VERSION 5.8 ;
BUSBITCHARS "[]" ;
DIVIDERCHAR "/" ;
UNITS
    DATABASE MICRONS 1000 ;
END UNITS

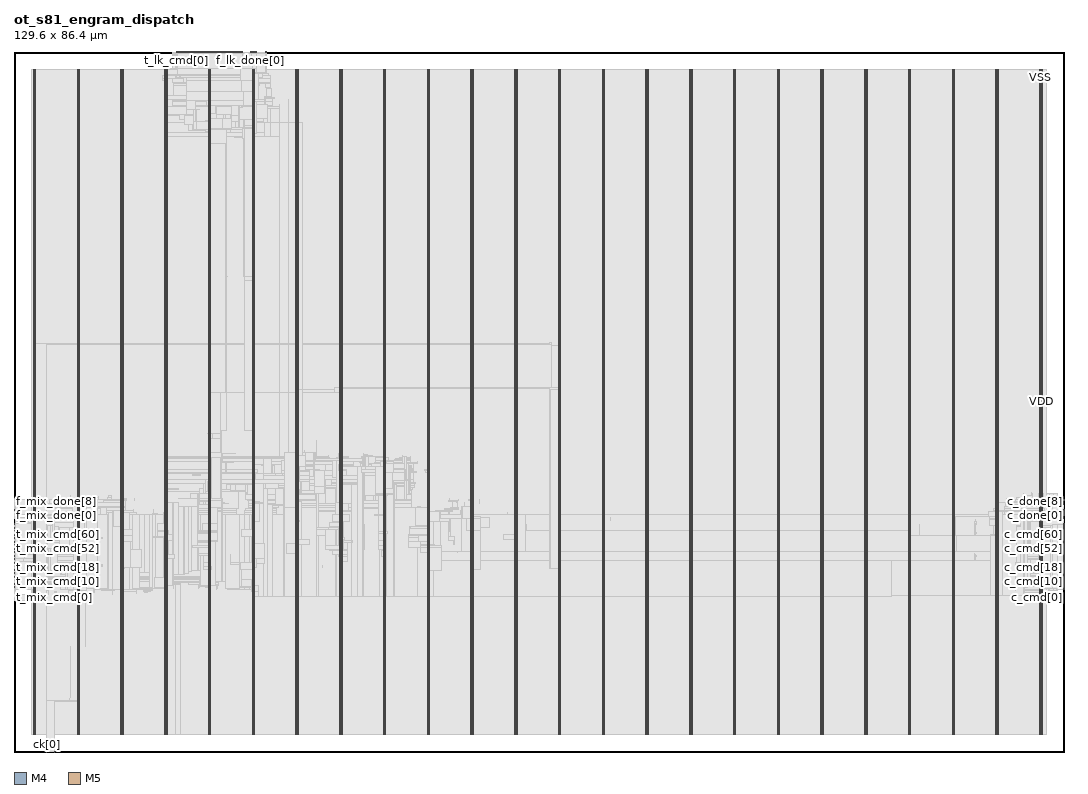
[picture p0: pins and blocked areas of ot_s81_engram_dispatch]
MACRO ot_s81_engram_dispatch
  FOREIGN ot_s81_engram_dispatch 0 0 ;
  CLASS BLOCK ;
  SIZE 129.6 BY 86.4 ;
  PIN c_cmd[0]
    DIRECTION INPUT ;
    USE SIGNAL ;
    PORT
      LAYER M4 ;
        RECT  129.516 20.064 129.6 20.088 ;
    END
  END c_cmd[0]
  PIN c_cmd[10]
    DIRECTION INPUT ;
    USE SIGNAL ;
    PORT
      LAYER M4 ;
        RECT  129.516 21.024 129.6 21.048 ;
    END
  END c_cmd[10]
  PIN c_cmd[11]
    DIRECTION INPUT ;
    USE SIGNAL ;
    PORT
      LAYER M4 ;
        RECT  129.516 21.12 129.6 21.144 ;
    END
  END c_cmd[11]
  PIN c_cmd[12]
    DIRECTION INPUT ;
    USE SIGNAL ;
    PORT
      LAYER M4 ;
        RECT  129.516 21.216 129.6 21.24 ;
    END
  END c_cmd[12]
  PIN c_cmd[13]
    DIRECTION INPUT ;
    USE SIGNAL ;
    PORT
      LAYER M4 ;
        RECT  129.516 21.312 129.6 21.336 ;
    END
  END c_cmd[13]
  PIN c_cmd[14]
    DIRECTION INPUT ;
    USE SIGNAL ;
    PORT
      LAYER M4 ;
        RECT  129.516 21.408 129.6 21.432 ;
    END
  END c_cmd[14]
  PIN c_cmd[15]
    DIRECTION INPUT ;
    USE SIGNAL ;
    PORT
      LAYER M4 ;
        RECT  129.516 21.504 129.6 21.528 ;
    END
  END c_cmd[15]
  PIN c_cmd[16]
    DIRECTION INPUT ;
    USE SIGNAL ;
    PORT
      LAYER M4 ;
        RECT  129.516 21.6 129.6 21.624 ;
    END
  END c_cmd[16]
  PIN c_cmd[17]
    DIRECTION INPUT ;
    USE SIGNAL ;
    PORT
      LAYER M4 ;
        RECT  129.516 21.696 129.6 21.72 ;
    END
  END c_cmd[17]
  PIN c_cmd[18]
    DIRECTION INPUT ;
    USE SIGNAL ;
    PORT
      LAYER M4 ;
        RECT  129.516 21.792 129.6 21.816 ;
    END
  END c_cmd[18]
  PIN c_cmd[19]
    DIRECTION INPUT ;
    USE SIGNAL ;
    PORT
      LAYER M4 ;
        RECT  129.516 21.888 129.6 21.912 ;
    END
  END c_cmd[19]
  PIN c_cmd[1]
    DIRECTION INPUT ;
    USE SIGNAL ;
    PORT
      LAYER M4 ;
        RECT  129.516 20.16 129.6 20.184 ;
    END
  END c_cmd[1]
  PIN c_cmd[20]
    DIRECTION INPUT ;
    USE SIGNAL ;
    PORT
      LAYER M4 ;
        RECT  129.516 21.984 129.6 22.008 ;
    END
  END c_cmd[20]
  PIN c_cmd[21]
    DIRECTION INPUT ;
    USE SIGNAL ;
    PORT
      LAYER M4 ;
        RECT  129.516 22.08 129.6 22.104 ;
    END
  END c_cmd[21]
  PIN c_cmd[22]
    DIRECTION INPUT ;
    USE SIGNAL ;
    PORT
      LAYER M4 ;
        RECT  129.516 22.176 129.6 22.2 ;
    END
  END c_cmd[22]
  PIN c_cmd[23]
    DIRECTION INPUT ;
    USE SIGNAL ;
    PORT
      LAYER M4 ;
        RECT  129.516 22.272 129.6 22.296 ;
    END
  END c_cmd[23]
  PIN c_cmd[24]
    DIRECTION INPUT ;
    USE SIGNAL ;
    PORT
      LAYER M4 ;
        RECT  129.516 22.368 129.6 22.392 ;
    END
  END c_cmd[24]
  PIN c_cmd[25]
    DIRECTION INPUT ;
    USE SIGNAL ;
    PORT
      LAYER M4 ;
        RECT  129.516 22.464 129.6 22.488 ;
    END
  END c_cmd[25]
  PIN c_cmd[26]
    DIRECTION INPUT ;
    USE SIGNAL ;
    PORT
      LAYER M4 ;
        RECT  129.516 22.56 129.6 22.584 ;
    END
  END c_cmd[26]
  PIN c_cmd[27]
    DIRECTION INPUT ;
    USE SIGNAL ;
    PORT
      LAYER M4 ;
        RECT  129.516 22.656 129.6 22.68 ;
    END
  END c_cmd[27]
  PIN c_cmd[28]
    DIRECTION INPUT ;
    USE SIGNAL ;
    PORT
      LAYER M4 ;
        RECT  129.516 22.752 129.6 22.776 ;
    END
  END c_cmd[28]
  PIN c_cmd[29]
    DIRECTION INPUT ;
    USE SIGNAL ;
    PORT
      LAYER M4 ;
        RECT  129.516 22.848 129.6 22.872 ;
    END
  END c_cmd[29]
  PIN c_cmd[2]
    DIRECTION INPUT ;
    USE SIGNAL ;
    PORT
      LAYER M4 ;
        RECT  129.516 20.256 129.6 20.28 ;
    END
  END c_cmd[2]
  PIN c_cmd[30]
    DIRECTION INPUT ;
    USE SIGNAL ;
    PORT
      LAYER M4 ;
        RECT  129.516 22.944 129.6 22.968 ;
    END
  END c_cmd[30]
  PIN c_cmd[31]
    DIRECTION INPUT ;
    USE SIGNAL ;
    PORT
      LAYER M4 ;
        RECT  129.516 23.04 129.6 23.064 ;
    END
  END c_cmd[31]
  PIN c_cmd[32]
    DIRECTION INPUT ;
    USE SIGNAL ;
    PORT
      LAYER M4 ;
        RECT  129.516 23.136 129.6 23.16 ;
    END
  END c_cmd[32]
  PIN c_cmd[33]
    DIRECTION INPUT ;
    USE SIGNAL ;
    PORT
      LAYER M4 ;
        RECT  129.516 23.232 129.6 23.256 ;
    END
  END c_cmd[33]
  PIN c_cmd[34]
    DIRECTION INPUT ;
    USE SIGNAL ;
    PORT
      LAYER M4 ;
        RECT  129.516 23.328 129.6 23.352 ;
    END
  END c_cmd[34]
  PIN c_cmd[35]
    DIRECTION INPUT ;
    USE SIGNAL ;
    PORT
      LAYER M4 ;
        RECT  129.516 23.424 129.6 23.448 ;
    END
  END c_cmd[35]
  PIN c_cmd[36]
    DIRECTION INPUT ;
    USE SIGNAL ;
    PORT
      LAYER M4 ;
        RECT  129.516 23.52 129.6 23.544 ;
    END
  END c_cmd[36]
  PIN c_cmd[37]
    DIRECTION INPUT ;
    USE SIGNAL ;
    PORT
      LAYER M4 ;
        RECT  129.516 23.616 129.6 23.64 ;
    END
  END c_cmd[37]
  PIN c_cmd[38]
    DIRECTION INPUT ;
    USE SIGNAL ;
    PORT
      LAYER M4 ;
        RECT  129.516 23.712 129.6 23.736 ;
    END
  END c_cmd[38]
  PIN c_cmd[39]
    DIRECTION INPUT ;
    USE SIGNAL ;
    PORT
      LAYER M4 ;
        RECT  129.516 23.808 129.6 23.832 ;
    END
  END c_cmd[39]
  PIN c_cmd[3]
    DIRECTION INPUT ;
    USE SIGNAL ;
    PORT
      LAYER M4 ;
        RECT  129.516 20.352 129.6 20.376 ;
    END
  END c_cmd[3]
  PIN c_cmd[40]
    DIRECTION INPUT ;
    USE SIGNAL ;
    PORT
      LAYER M4 ;
        RECT  129.516 23.904 129.6 23.928 ;
    END
  END c_cmd[40]
  PIN c_cmd[41]
    DIRECTION INPUT ;
    USE SIGNAL ;
    PORT
      LAYER M4 ;
        RECT  129.516 24 129.6 24.024 ;
    END
  END c_cmd[41]
  PIN c_cmd[42]
    DIRECTION INPUT ;
    USE SIGNAL ;
    PORT
      LAYER M4 ;
        RECT  129.516 24.096 129.6 24.12 ;
    END
  END c_cmd[42]
  PIN c_cmd[43]
    DIRECTION INPUT ;
    USE SIGNAL ;
    PORT
      LAYER M4 ;
        RECT  129.516 24.192 129.6 24.216 ;
    END
  END c_cmd[43]
  PIN c_cmd[44]
    DIRECTION INPUT ;
    USE SIGNAL ;
    PORT
      LAYER M4 ;
        RECT  129.516 24.288 129.6 24.312 ;
    END
  END c_cmd[44]
  PIN c_cmd[45]
    DIRECTION INPUT ;
    USE SIGNAL ;
    PORT
      LAYER M4 ;
        RECT  129.516 24.384 129.6 24.408 ;
    END
  END c_cmd[45]
  PIN c_cmd[46]
    DIRECTION INPUT ;
    USE SIGNAL ;
    PORT
      LAYER M4 ;
        RECT  129.516 24.48 129.6 24.504 ;
    END
  END c_cmd[46]
  PIN c_cmd[47]
    DIRECTION INPUT ;
    USE SIGNAL ;
    PORT
      LAYER M4 ;
        RECT  129.516 24.576 129.6 24.6 ;
    END
  END c_cmd[47]
  PIN c_cmd[48]
    DIRECTION INPUT ;
    USE SIGNAL ;
    PORT
      LAYER M4 ;
        RECT  129.516 24.672 129.6 24.696 ;
    END
  END c_cmd[48]
  PIN c_cmd[49]
    DIRECTION INPUT ;
    USE SIGNAL ;
    PORT
      LAYER M4 ;
        RECT  129.516 24.768 129.6 24.792 ;
    END
  END c_cmd[49]
  PIN c_cmd[4]
    DIRECTION INPUT ;
    USE SIGNAL ;
    PORT
      LAYER M4 ;
        RECT  129.516 20.448 129.6 20.472 ;
    END
  END c_cmd[4]
  PIN c_cmd[50]
    DIRECTION INPUT ;
    USE SIGNAL ;
    PORT
      LAYER M4 ;
        RECT  129.516 24.864 129.6 24.888 ;
    END
  END c_cmd[50]
  PIN c_cmd[51]
    DIRECTION INPUT ;
    USE SIGNAL ;
    PORT
      LAYER M4 ;
        RECT  129.516 24.96 129.6 24.984 ;
    END
  END c_cmd[51]
  PIN c_cmd[52]
    DIRECTION INPUT ;
    USE SIGNAL ;
    PORT
      LAYER M4 ;
        RECT  129.516 25.056 129.6 25.08 ;
    END
  END c_cmd[52]
  PIN c_cmd[53]
    DIRECTION INPUT ;
    USE SIGNAL ;
    PORT
      LAYER M4 ;
        RECT  129.516 25.152 129.6 25.176 ;
    END
  END c_cmd[53]
  PIN c_cmd[54]
    DIRECTION INPUT ;
    USE SIGNAL ;
    PORT
      LAYER M4 ;
        RECT  129.516 25.248 129.6 25.272 ;
    END
  END c_cmd[54]
  PIN c_cmd[55]
    DIRECTION INPUT ;
    USE SIGNAL ;
    PORT
      LAYER M4 ;
        RECT  129.516 25.344 129.6 25.368 ;
    END
  END c_cmd[55]
  PIN c_cmd[56]
    DIRECTION INPUT ;
    USE SIGNAL ;
    PORT
      LAYER M4 ;
        RECT  129.516 25.44 129.6 25.464 ;
    END
  END c_cmd[56]
  PIN c_cmd[57]
    DIRECTION INPUT ;
    USE SIGNAL ;
    PORT
      LAYER M4 ;
        RECT  129.516 25.536 129.6 25.56 ;
    END
  END c_cmd[57]
  PIN c_cmd[58]
    DIRECTION INPUT ;
    USE SIGNAL ;
    PORT
      LAYER M4 ;
        RECT  129.516 25.632 129.6 25.656 ;
    END
  END c_cmd[58]
  PIN c_cmd[59]
    DIRECTION INPUT ;
    USE SIGNAL ;
    PORT
      LAYER M4 ;
        RECT  129.516 25.728 129.6 25.752 ;
    END
  END c_cmd[59]
  PIN c_cmd[5]
    DIRECTION INPUT ;
    USE SIGNAL ;
    PORT
      LAYER M4 ;
        RECT  129.516 20.544 129.6 20.568 ;
    END
  END c_cmd[5]
  PIN c_cmd[60]
    DIRECTION INPUT ;
    USE SIGNAL ;
    PORT
      LAYER M4 ;
        RECT  129.516 25.824 129.6 25.848 ;
    END
  END c_cmd[60]
  PIN c_cmd[61]
    DIRECTION INPUT ;
    USE SIGNAL ;
    PORT
      LAYER M4 ;
        RECT  129.516 25.92 129.6 25.944 ;
    END
  END c_cmd[61]
  PIN c_cmd[62]
    DIRECTION INPUT ;
    USE SIGNAL ;
    PORT
      LAYER M4 ;
        RECT  129.516 26.016 129.6 26.04 ;
    END
  END c_cmd[62]
  PIN c_cmd[63]
    DIRECTION INPUT ;
    USE SIGNAL ;
    PORT
      LAYER M4 ;
        RECT  129.516 26.112 129.6 26.136 ;
    END
  END c_cmd[63]
  PIN c_cmd[64]
    DIRECTION INPUT ;
    USE SIGNAL ;
    PORT
      LAYER M4 ;
        RECT  129.516 26.208 129.6 26.232 ;
    END
  END c_cmd[64]
  PIN c_cmd[65]
    DIRECTION INPUT ;
    USE SIGNAL ;
    PORT
      LAYER M4 ;
        RECT  129.516 26.304 129.6 26.328 ;
    END
  END c_cmd[65]
  PIN c_cmd[66]
    DIRECTION INPUT ;
    USE SIGNAL ;
    PORT
      LAYER M4 ;
        RECT  129.516 26.4 129.6 26.424 ;
    END
  END c_cmd[66]
  PIN c_cmd[67]
    DIRECTION INPUT ;
    USE SIGNAL ;
    PORT
      LAYER M4 ;
        RECT  129.516 26.496 129.6 26.52 ;
    END
  END c_cmd[67]
  PIN c_cmd[68]
    DIRECTION INPUT ;
    USE SIGNAL ;
    PORT
      LAYER M4 ;
        RECT  129.516 26.592 129.6 26.616 ;
    END
  END c_cmd[68]
  PIN c_cmd[69]
    DIRECTION INPUT ;
    USE SIGNAL ;
    PORT
      LAYER M4 ;
        RECT  129.516 26.688 129.6 26.712 ;
    END
  END c_cmd[69]
  PIN c_cmd[6]
    DIRECTION INPUT ;
    USE SIGNAL ;
    PORT
      LAYER M4 ;
        RECT  129.516 20.64 129.6 20.664 ;
    END
  END c_cmd[6]
  PIN c_cmd[70]
    DIRECTION INPUT ;
    USE SIGNAL ;
    PORT
      LAYER M4 ;
        RECT  129.516 26.784 129.6 26.808 ;
    END
  END c_cmd[70]
  PIN c_cmd[71]
    DIRECTION INPUT ;
    USE SIGNAL ;
    PORT
      LAYER M4 ;
        RECT  129.516 26.88 129.6 26.904 ;
    END
  END c_cmd[71]
  PIN c_cmd[72]
    DIRECTION INPUT ;
    USE SIGNAL ;
    PORT
      LAYER M4 ;
        RECT  129.516 26.976 129.6 27 ;
    END
  END c_cmd[72]
  PIN c_cmd[73]
    DIRECTION INPUT ;
    USE SIGNAL ;
    PORT
      LAYER M4 ;
        RECT  129.516 27.072 129.6 27.096 ;
    END
  END c_cmd[73]
  PIN c_cmd[74]
    DIRECTION INPUT ;
    USE SIGNAL ;
    PORT
      LAYER M4 ;
        RECT  129.516 27.168 129.6 27.192 ;
    END
  END c_cmd[74]
  PIN c_cmd[75]
    DIRECTION INPUT ;
    USE SIGNAL ;
    PORT
      LAYER M4 ;
        RECT  129.516 27.264 129.6 27.288 ;
    END
  END c_cmd[75]
  PIN c_cmd[76]
    DIRECTION INPUT ;
    USE SIGNAL ;
    PORT
      LAYER M4 ;
        RECT  129.516 27.36 129.6 27.384 ;
    END
  END c_cmd[76]
  PIN c_cmd[77]
    DIRECTION INPUT ;
    USE SIGNAL ;
    PORT
      LAYER M4 ;
        RECT  129.516 27.456 129.6 27.48 ;
    END
  END c_cmd[77]
  PIN c_cmd[78]
    DIRECTION INPUT ;
    USE SIGNAL ;
    PORT
      LAYER M4 ;
        RECT  129.516 27.552 129.6 27.576 ;
    END
  END c_cmd[78]
  PIN c_cmd[79]
    DIRECTION INPUT ;
    USE SIGNAL ;
    PORT
      LAYER M4 ;
        RECT  129.516 27.648 129.6 27.672 ;
    END
  END c_cmd[79]
  PIN c_cmd[7]
    DIRECTION INPUT ;
    USE SIGNAL ;
    PORT
      LAYER M4 ;
        RECT  129.516 20.736 129.6 20.76 ;
    END
  END c_cmd[7]
  PIN c_cmd[80]
    DIRECTION INPUT ;
    USE SIGNAL ;
    PORT
      LAYER M4 ;
        RECT  129.516 27.744 129.6 27.768 ;
    END
  END c_cmd[80]
  PIN c_cmd[81]
    DIRECTION INPUT ;
    USE SIGNAL ;
    PORT
      LAYER M4 ;
        RECT  129.516 27.84 129.6 27.864 ;
    END
  END c_cmd[81]
  PIN c_cmd[82]
    DIRECTION INPUT ;
    USE SIGNAL ;
    PORT
      LAYER M4 ;
        RECT  129.516 27.936 129.6 27.96 ;
    END
  END c_cmd[82]
  PIN c_cmd[83]
    DIRECTION INPUT ;
    USE SIGNAL ;
    PORT
      LAYER M4 ;
        RECT  129.516 28.032 129.6 28.056 ;
    END
  END c_cmd[83]
  PIN c_cmd[84]
    DIRECTION INPUT ;
    USE SIGNAL ;
    PORT
      LAYER M4 ;
        RECT  129.516 28.128 129.6 28.152 ;
    END
  END c_cmd[84]
  PIN c_cmd[8]
    DIRECTION INPUT ;
    USE SIGNAL ;
    PORT
      LAYER M4 ;
        RECT  129.516 20.832 129.6 20.856 ;
    END
  END c_cmd[8]
  PIN c_cmd[9]
    DIRECTION INPUT ;
    USE SIGNAL ;
    PORT
      LAYER M4 ;
        RECT  129.516 20.928 129.6 20.952 ;
    END
  END c_cmd[9]
  PIN c_done[0]
    DIRECTION OUTPUT ;
    USE SIGNAL ;
    PORT
      LAYER M4 ;
        RECT  129.516 29.184 129.6 29.208 ;
    END
  END c_done[0]
  PIN c_done[1]
    DIRECTION OUTPUT ;
    USE SIGNAL ;
    PORT
      LAYER M4 ;
        RECT  129.516 29.28 129.6 29.304 ;
    END
  END c_done[1]
  PIN c_done[2]
    DIRECTION OUTPUT ;
    USE SIGNAL ;
    PORT
      LAYER M4 ;
        RECT  129.516 29.376 129.6 29.4 ;
    END
  END c_done[2]
  PIN c_done[3]
    DIRECTION OUTPUT ;
    USE SIGNAL ;
    PORT
      LAYER M4 ;
        RECT  129.516 29.472 129.6 29.496 ;
    END
  END c_done[3]
  PIN c_done[4]
    DIRECTION OUTPUT ;
    USE SIGNAL ;
    PORT
      LAYER M4 ;
        RECT  129.516 29.568 129.6 29.592 ;
    END
  END c_done[4]
  PIN c_done[5]
    DIRECTION OUTPUT ;
    USE SIGNAL ;
    PORT
      LAYER M4 ;
        RECT  129.516 29.664 129.6 29.688 ;
    END
  END c_done[5]
  PIN c_done[6]
    DIRECTION OUTPUT ;
    USE SIGNAL ;
    PORT
      LAYER M4 ;
        RECT  129.516 29.76 129.6 29.784 ;
    END
  END c_done[6]
  PIN c_done[7]
    DIRECTION OUTPUT ;
    USE SIGNAL ;
    PORT
      LAYER M4 ;
        RECT  129.516 29.856 129.6 29.88 ;
    END
  END c_done[7]
  PIN c_done[8]
    DIRECTION OUTPUT ;
    USE SIGNAL ;
    PORT
      LAYER M4 ;
        RECT  129.516 29.952 129.6 29.976 ;
    END
  END c_done[8]
  PIN c_st[0]
    DIRECTION OUTPUT ;
    USE SIGNAL ;
    PORT
      LAYER M4 ;
        RECT  129.516 31.008 129.6 31.032 ;
    END
  END c_st[0]
  PIN c_st[1]
    DIRECTION OUTPUT ;
    USE SIGNAL ;
    PORT
      LAYER M4 ;
        RECT  129.516 31.104 129.6 31.128 ;
    END
  END c_st[1]
  PIN ck[0]
    DIRECTION INPUT ;
    USE SIGNAL ;
    PORT
      LAYER M5 ;
        RECT  4.032 0 4.056 0.084 ;
    END
  END ck[0]
  PIN f_lk_done[0]
    DIRECTION INPUT ;
    USE SIGNAL ;
    PORT
      LAYER M5 ;
        RECT  29.184 86.316 29.208 86.4 ;
    END
  END f_lk_done[0]
  PIN f_lk_done[1]
    DIRECTION INPUT ;
    USE SIGNAL ;
    PORT
      LAYER M5 ;
        RECT  29.28 86.316 29.304 86.4 ;
    END
  END f_lk_done[1]
  PIN f_lk_done[2]
    DIRECTION INPUT ;
    USE SIGNAL ;
    PORT
      LAYER M5 ;
        RECT  29.376 86.316 29.4 86.4 ;
    END
  END f_lk_done[2]
  PIN f_lk_done[3]
    DIRECTION INPUT ;
    USE SIGNAL ;
    PORT
      LAYER M5 ;
        RECT  29.472 86.316 29.496 86.4 ;
    END
  END f_lk_done[3]
  PIN f_lk_done[4]
    DIRECTION INPUT ;
    USE SIGNAL ;
    PORT
      LAYER M5 ;
        RECT  29.568 86.316 29.592 86.4 ;
    END
  END f_lk_done[4]
  PIN f_lk_done[5]
    DIRECTION INPUT ;
    USE SIGNAL ;
    PORT
      LAYER M5 ;
        RECT  29.664 86.316 29.688 86.4 ;
    END
  END f_lk_done[5]
  PIN f_lk_done[6]
    DIRECTION INPUT ;
    USE SIGNAL ;
    PORT
      LAYER M5 ;
        RECT  29.76 86.316 29.784 86.4 ;
    END
  END f_lk_done[6]
  PIN f_lk_done[7]
    DIRECTION INPUT ;
    USE SIGNAL ;
    PORT
      LAYER M5 ;
        RECT  29.856 86.316 29.88 86.4 ;
    END
  END f_lk_done[7]
  PIN f_lk_done[8]
    DIRECTION INPUT ;
    USE SIGNAL ;
    PORT
      LAYER M5 ;
        RECT  29.952 86.316 29.976 86.4 ;
    END
  END f_lk_done[8]
  PIN f_lk_st[0]
    DIRECTION INPUT ;
    USE SIGNAL ;
    PORT
      LAYER M5 ;
        RECT  31.008 86.316 31.032 86.4 ;
    END
  END f_lk_st[0]
  PIN f_lk_st[1]
    DIRECTION INPUT ;
    USE SIGNAL ;
    PORT
      LAYER M5 ;
        RECT  31.104 86.316 31.128 86.4 ;
    END
  END f_lk_st[1]
  PIN f_mix_done[0]
    DIRECTION INPUT ;
    USE SIGNAL ;
    PORT
      LAYER M4 ;
        RECT  0 29.184 0.084 29.208 ;
    END
  END f_mix_done[0]
  PIN f_mix_done[1]
    DIRECTION INPUT ;
    USE SIGNAL ;
    PORT
      LAYER M4 ;
        RECT  0 29.28 0.084 29.304 ;
    END
  END f_mix_done[1]
  PIN f_mix_done[2]
    DIRECTION INPUT ;
    USE SIGNAL ;
    PORT
      LAYER M4 ;
        RECT  0 29.376 0.084 29.4 ;
    END
  END f_mix_done[2]
  PIN f_mix_done[3]
    DIRECTION INPUT ;
    USE SIGNAL ;
    PORT
      LAYER M4 ;
        RECT  0 29.472 0.084 29.496 ;
    END
  END f_mix_done[3]
  PIN f_mix_done[4]
    DIRECTION INPUT ;
    USE SIGNAL ;
    PORT
      LAYER M4 ;
        RECT  0 29.568 0.084 29.592 ;
    END
  END f_mix_done[4]
  PIN f_mix_done[5]
    DIRECTION INPUT ;
    USE SIGNAL ;
    PORT
      LAYER M4 ;
        RECT  0 29.664 0.084 29.688 ;
    END
  END f_mix_done[5]
  PIN f_mix_done[6]
    DIRECTION INPUT ;
    USE SIGNAL ;
    PORT
      LAYER M4 ;
        RECT  0 29.76 0.084 29.784 ;
    END
  END f_mix_done[6]
  PIN f_mix_done[7]
    DIRECTION INPUT ;
    USE SIGNAL ;
    PORT
      LAYER M4 ;
        RECT  0 29.856 0.084 29.88 ;
    END
  END f_mix_done[7]
  PIN f_mix_done[8]
    DIRECTION INPUT ;
    USE SIGNAL ;
    PORT
      LAYER M4 ;
        RECT  0 29.952 0.084 29.976 ;
    END
  END f_mix_done[8]
  PIN f_mix_st[0]
    DIRECTION INPUT ;
    USE SIGNAL ;
    PORT
      LAYER M4 ;
        RECT  0 31.008 0.084 31.032 ;
    END
  END f_mix_st[0]
  PIN f_mix_st[1]
    DIRECTION INPUT ;
    USE SIGNAL ;
    PORT
      LAYER M4 ;
        RECT  0 31.104 0.084 31.128 ;
    END
  END f_mix_st[1]
  PIN rst[0]
    DIRECTION INPUT ;
    USE SIGNAL ;
    PORT
      LAYER M5 ;
        RECT  4.992 0 5.016 0.084 ;
    END
  END rst[0]
  PIN t_lk_cmd[0]
    DIRECTION OUTPUT ;
    USE SIGNAL ;
    PORT
      LAYER M5 ;
        RECT  20.064 86.316 20.088 86.4 ;
    END
  END t_lk_cmd[0]
  PIN t_lk_cmd[10]
    DIRECTION OUTPUT ;
    USE SIGNAL ;
    PORT
      LAYER M5 ;
        RECT  21.024 86.316 21.048 86.4 ;
    END
  END t_lk_cmd[10]
  PIN t_lk_cmd[11]
    DIRECTION OUTPUT ;
    USE SIGNAL ;
    PORT
      LAYER M5 ;
        RECT  21.12 86.316 21.144 86.4 ;
    END
  END t_lk_cmd[11]
  PIN t_lk_cmd[12]
    DIRECTION OUTPUT ;
    USE SIGNAL ;
    PORT
      LAYER M5 ;
        RECT  21.216 86.316 21.24 86.4 ;
    END
  END t_lk_cmd[12]
  PIN t_lk_cmd[13]
    DIRECTION OUTPUT ;
    USE SIGNAL ;
    PORT
      LAYER M5 ;
        RECT  21.312 86.316 21.336 86.4 ;
    END
  END t_lk_cmd[13]
  PIN t_lk_cmd[14]
    DIRECTION OUTPUT ;
    USE SIGNAL ;
    PORT
      LAYER M5 ;
        RECT  21.408 86.316 21.432 86.4 ;
    END
  END t_lk_cmd[14]
  PIN t_lk_cmd[15]
    DIRECTION OUTPUT ;
    USE SIGNAL ;
    PORT
      LAYER M5 ;
        RECT  21.504 86.316 21.528 86.4 ;
    END
  END t_lk_cmd[15]
  PIN t_lk_cmd[16]
    DIRECTION OUTPUT ;
    USE SIGNAL ;
    PORT
      LAYER M5 ;
        RECT  21.6 86.316 21.624 86.4 ;
    END
  END t_lk_cmd[16]
  PIN t_lk_cmd[17]
    DIRECTION OUTPUT ;
    USE SIGNAL ;
    PORT
      LAYER M5 ;
        RECT  21.696 86.316 21.72 86.4 ;
    END
  END t_lk_cmd[17]
  PIN t_lk_cmd[18]
    DIRECTION OUTPUT ;
    USE SIGNAL ;
    PORT
      LAYER M5 ;
        RECT  21.792 86.316 21.816 86.4 ;
    END
  END t_lk_cmd[18]
  PIN t_lk_cmd[19]
    DIRECTION OUTPUT ;
    USE SIGNAL ;
    PORT
      LAYER M5 ;
        RECT  21.888 86.316 21.912 86.4 ;
    END
  END t_lk_cmd[19]
  PIN t_lk_cmd[1]
    DIRECTION OUTPUT ;
    USE SIGNAL ;
    PORT
      LAYER M5 ;
        RECT  20.16 86.316 20.184 86.4 ;
    END
  END t_lk_cmd[1]
  PIN t_lk_cmd[20]
    DIRECTION OUTPUT ;
    USE SIGNAL ;
    PORT
      LAYER M5 ;
        RECT  21.984 86.316 22.008 86.4 ;
    END
  END t_lk_cmd[20]
  PIN t_lk_cmd[21]
    DIRECTION OUTPUT ;
    USE SIGNAL ;
    PORT
      LAYER M5 ;
        RECT  22.08 86.316 22.104 86.4 ;
    END
  END t_lk_cmd[21]
  PIN t_lk_cmd[22]
    DIRECTION OUTPUT ;
    USE SIGNAL ;
    PORT
      LAYER M5 ;
        RECT  22.176 86.316 22.2 86.4 ;
    END
  END t_lk_cmd[22]
  PIN t_lk_cmd[23]
    DIRECTION OUTPUT ;
    USE SIGNAL ;
    PORT
      LAYER M5 ;
        RECT  22.272 86.316 22.296 86.4 ;
    END
  END t_lk_cmd[23]
  PIN t_lk_cmd[24]
    DIRECTION OUTPUT ;
    USE SIGNAL ;
    PORT
      LAYER M5 ;
        RECT  22.368 86.316 22.392 86.4 ;
    END
  END t_lk_cmd[24]
  PIN t_lk_cmd[25]
    DIRECTION OUTPUT ;
    USE SIGNAL ;
    PORT
      LAYER M5 ;
        RECT  22.464 86.316 22.488 86.4 ;
    END
  END t_lk_cmd[25]
  PIN t_lk_cmd[26]
    DIRECTION OUTPUT ;
    USE SIGNAL ;
    PORT
      LAYER M5 ;
        RECT  22.56 86.316 22.584 86.4 ;
    END
  END t_lk_cmd[26]
  PIN t_lk_cmd[27]
    DIRECTION OUTPUT ;
    USE SIGNAL ;
    PORT
      LAYER M5 ;
        RECT  22.656 86.316 22.68 86.4 ;
    END
  END t_lk_cmd[27]
  PIN t_lk_cmd[28]
    DIRECTION OUTPUT ;
    USE SIGNAL ;
    PORT
      LAYER M5 ;
        RECT  22.752 86.316 22.776 86.4 ;
    END
  END t_lk_cmd[28]
  PIN t_lk_cmd[29]
    DIRECTION OUTPUT ;
    USE SIGNAL ;
    PORT
      LAYER M5 ;
        RECT  22.848 86.316 22.872 86.4 ;
    END
  END t_lk_cmd[29]
  PIN t_lk_cmd[2]
    DIRECTION OUTPUT ;
    USE SIGNAL ;
    PORT
      LAYER M5 ;
        RECT  20.256 86.316 20.28 86.4 ;
    END
  END t_lk_cmd[2]
  PIN t_lk_cmd[30]
    DIRECTION OUTPUT ;
    USE SIGNAL ;
    PORT
      LAYER M5 ;
        RECT  22.944 86.316 22.968 86.4 ;
    END
  END t_lk_cmd[30]
  PIN t_lk_cmd[31]
    DIRECTION OUTPUT ;
    USE SIGNAL ;
    PORT
      LAYER M5 ;
        RECT  23.04 86.316 23.064 86.4 ;
    END
  END t_lk_cmd[31]
  PIN t_lk_cmd[32]
    DIRECTION OUTPUT ;
    USE SIGNAL ;
    PORT
      LAYER M5 ;
        RECT  23.136 86.316 23.16 86.4 ;
    END
  END t_lk_cmd[32]
  PIN t_lk_cmd[33]
    DIRECTION OUTPUT ;
    USE SIGNAL ;
    PORT
      LAYER M5 ;
        RECT  23.232 86.316 23.256 86.4 ;
    END
  END t_lk_cmd[33]
  PIN t_lk_cmd[34]
    DIRECTION OUTPUT ;
    USE SIGNAL ;
    PORT
      LAYER M5 ;
        RECT  23.328 86.316 23.352 86.4 ;
    END
  END t_lk_cmd[34]
  PIN t_lk_cmd[35]
    DIRECTION OUTPUT ;
    USE SIGNAL ;
    PORT
      LAYER M5 ;
        RECT  23.424 86.316 23.448 86.4 ;
    END
  END t_lk_cmd[35]
  PIN t_lk_cmd[36]
    DIRECTION OUTPUT ;
    USE SIGNAL ;
    PORT
      LAYER M5 ;
        RECT  23.52 86.316 23.544 86.4 ;
    END
  END t_lk_cmd[36]
  PIN t_lk_cmd[37]
    DIRECTION OUTPUT ;
    USE SIGNAL ;
    PORT
      LAYER M5 ;
        RECT  23.616 86.316 23.64 86.4 ;
    END
  END t_lk_cmd[37]
  PIN t_lk_cmd[38]
    DIRECTION OUTPUT ;
    USE SIGNAL ;
    PORT
      LAYER M5 ;
        RECT  23.712 86.316 23.736 86.4 ;
    END
  END t_lk_cmd[38]
  PIN t_lk_cmd[39]
    DIRECTION OUTPUT ;
    USE SIGNAL ;
    PORT
      LAYER M5 ;
        RECT  23.808 86.316 23.832 86.4 ;
    END
  END t_lk_cmd[39]
  PIN t_lk_cmd[3]
    DIRECTION OUTPUT ;
    USE SIGNAL ;
    PORT
      LAYER M5 ;
        RECT  20.352 86.316 20.376 86.4 ;
    END
  END t_lk_cmd[3]
  PIN t_lk_cmd[40]
    DIRECTION OUTPUT ;
    USE SIGNAL ;
    PORT
      LAYER M5 ;
        RECT  23.904 86.316 23.928 86.4 ;
    END
  END t_lk_cmd[40]
  PIN t_lk_cmd[41]
    DIRECTION OUTPUT ;
    USE SIGNAL ;
    PORT
      LAYER M5 ;
        RECT  24 86.316 24.024 86.4 ;
    END
  END t_lk_cmd[41]
  PIN t_lk_cmd[42]
    DIRECTION OUTPUT ;
    USE SIGNAL ;
    PORT
      LAYER M5 ;
        RECT  24.096 86.316 24.12 86.4 ;
    END
  END t_lk_cmd[42]
  PIN t_lk_cmd[43]
    DIRECTION OUTPUT ;
    USE SIGNAL ;
    PORT
      LAYER M5 ;
        RECT  24.192 86.316 24.216 86.4 ;
    END
  END t_lk_cmd[43]
  PIN t_lk_cmd[44]
    DIRECTION OUTPUT ;
    USE SIGNAL ;
    PORT
      LAYER M5 ;
        RECT  24.288 86.316 24.312 86.4 ;
    END
  END t_lk_cmd[44]
  PIN t_lk_cmd[45]
    DIRECTION OUTPUT ;
    USE SIGNAL ;
    PORT
      LAYER M5 ;
        RECT  24.384 86.316 24.408 86.4 ;
    END
  END t_lk_cmd[45]
  PIN t_lk_cmd[46]
    DIRECTION OUTPUT ;
    USE SIGNAL ;
    PORT
      LAYER M5 ;
        RECT  24.48 86.316 24.504 86.4 ;
    END
  END t_lk_cmd[46]
  PIN t_lk_cmd[47]
    DIRECTION OUTPUT ;
    USE SIGNAL ;
    PORT
      LAYER M5 ;
        RECT  24.576 86.316 24.6 86.4 ;
    END
  END t_lk_cmd[47]
  PIN t_lk_cmd[48]
    DIRECTION OUTPUT ;
    USE SIGNAL ;
    PORT
      LAYER M5 ;
        RECT  24.672 86.316 24.696 86.4 ;
    END
  END t_lk_cmd[48]
  PIN t_lk_cmd[49]
    DIRECTION OUTPUT ;
    USE SIGNAL ;
    PORT
      LAYER M5 ;
        RECT  24.768 86.316 24.792 86.4 ;
    END
  END t_lk_cmd[49]
  PIN t_lk_cmd[4]
    DIRECTION OUTPUT ;
    USE SIGNAL ;
    PORT
      LAYER M5 ;
        RECT  20.448 86.316 20.472 86.4 ;
    END
  END t_lk_cmd[4]
  PIN t_lk_cmd[50]
    DIRECTION OUTPUT ;
    USE SIGNAL ;
    PORT
      LAYER M5 ;
        RECT  24.864 86.316 24.888 86.4 ;
    END
  END t_lk_cmd[50]
  PIN t_lk_cmd[51]
    DIRECTION OUTPUT ;
    USE SIGNAL ;
    PORT
      LAYER M5 ;
        RECT  24.96 86.316 24.984 86.4 ;
    END
  END t_lk_cmd[51]
  PIN t_lk_cmd[52]
    DIRECTION OUTPUT ;
    USE SIGNAL ;
    PORT
      LAYER M5 ;
        RECT  25.056 86.316 25.08 86.4 ;
    END
  END t_lk_cmd[52]
  PIN t_lk_cmd[53]
    DIRECTION OUTPUT ;
    USE SIGNAL ;
    PORT
      LAYER M5 ;
        RECT  25.152 86.316 25.176 86.4 ;
    END
  END t_lk_cmd[53]
  PIN t_lk_cmd[54]
    DIRECTION OUTPUT ;
    USE SIGNAL ;
    PORT
      LAYER M5 ;
        RECT  25.248 86.316 25.272 86.4 ;
    END
  END t_lk_cmd[54]
  PIN t_lk_cmd[55]
    DIRECTION OUTPUT ;
    USE SIGNAL ;
    PORT
      LAYER M5 ;
        RECT  25.344 86.316 25.368 86.4 ;
    END
  END t_lk_cmd[55]
  PIN t_lk_cmd[56]
    DIRECTION OUTPUT ;
    USE SIGNAL ;
    PORT
      LAYER M5 ;
        RECT  25.44 86.316 25.464 86.4 ;
    END
  END t_lk_cmd[56]
  PIN t_lk_cmd[57]
    DIRECTION OUTPUT ;
    USE SIGNAL ;
    PORT
      LAYER M5 ;
        RECT  25.536 86.316 25.56 86.4 ;
    END
  END t_lk_cmd[57]
  PIN t_lk_cmd[58]
    DIRECTION OUTPUT ;
    USE SIGNAL ;
    PORT
      LAYER M5 ;
        RECT  25.632 86.316 25.656 86.4 ;
    END
  END t_lk_cmd[58]
  PIN t_lk_cmd[59]
    DIRECTION OUTPUT ;
    USE SIGNAL ;
    PORT
      LAYER M5 ;
        RECT  25.728 86.316 25.752 86.4 ;
    END
  END t_lk_cmd[59]
  PIN t_lk_cmd[5]
    DIRECTION OUTPUT ;
    USE SIGNAL ;
    PORT
      LAYER M5 ;
        RECT  20.544 86.316 20.568 86.4 ;
    END
  END t_lk_cmd[5]
  PIN t_lk_cmd[60]
    DIRECTION OUTPUT ;
    USE SIGNAL ;
    PORT
      LAYER M5 ;
        RECT  25.824 86.316 25.848 86.4 ;
    END
  END t_lk_cmd[60]
  PIN t_lk_cmd[61]
    DIRECTION OUTPUT ;
    USE SIGNAL ;
    PORT
      LAYER M5 ;
        RECT  25.92 86.316 25.944 86.4 ;
    END
  END t_lk_cmd[61]
  PIN t_lk_cmd[62]
    DIRECTION OUTPUT ;
    USE SIGNAL ;
    PORT
      LAYER M5 ;
        RECT  26.016 86.316 26.04 86.4 ;
    END
  END t_lk_cmd[62]
  PIN t_lk_cmd[63]
    DIRECTION OUTPUT ;
    USE SIGNAL ;
    PORT
      LAYER M5 ;
        RECT  26.112 86.316 26.136 86.4 ;
    END
  END t_lk_cmd[63]
  PIN t_lk_cmd[64]
    DIRECTION OUTPUT ;
    USE SIGNAL ;
    PORT
      LAYER M5 ;
        RECT  26.208 86.316 26.232 86.4 ;
    END
  END t_lk_cmd[64]
  PIN t_lk_cmd[65]
    DIRECTION OUTPUT ;
    USE SIGNAL ;
    PORT
      LAYER M5 ;
        RECT  26.304 86.316 26.328 86.4 ;
    END
  END t_lk_cmd[65]
  PIN t_lk_cmd[66]
    DIRECTION OUTPUT ;
    USE SIGNAL ;
    PORT
      LAYER M5 ;
        RECT  26.4 86.316 26.424 86.4 ;
    END
  END t_lk_cmd[66]
  PIN t_lk_cmd[67]
    DIRECTION OUTPUT ;
    USE SIGNAL ;
    PORT
      LAYER M5 ;
        RECT  26.496 86.316 26.52 86.4 ;
    END
  END t_lk_cmd[67]
  PIN t_lk_cmd[68]
    DIRECTION OUTPUT ;
    USE SIGNAL ;
    PORT
      LAYER M5 ;
        RECT  26.592 86.316 26.616 86.4 ;
    END
  END t_lk_cmd[68]
  PIN t_lk_cmd[69]
    DIRECTION OUTPUT ;
    USE SIGNAL ;
    PORT
      LAYER M5 ;
        RECT  26.688 86.316 26.712 86.4 ;
    END
  END t_lk_cmd[69]
  PIN t_lk_cmd[6]
    DIRECTION OUTPUT ;
    USE SIGNAL ;
    PORT
      LAYER M5 ;
        RECT  20.64 86.316 20.664 86.4 ;
    END
  END t_lk_cmd[6]
  PIN t_lk_cmd[70]
    DIRECTION OUTPUT ;
    USE SIGNAL ;
    PORT
      LAYER M5 ;
        RECT  26.784 86.316 26.808 86.4 ;
    END
  END t_lk_cmd[70]
  PIN t_lk_cmd[71]
    DIRECTION OUTPUT ;
    USE SIGNAL ;
    PORT
      LAYER M5 ;
        RECT  26.88 86.316 26.904 86.4 ;
    END
  END t_lk_cmd[71]
  PIN t_lk_cmd[72]
    DIRECTION OUTPUT ;
    USE SIGNAL ;
    PORT
      LAYER M5 ;
        RECT  26.976 86.316 27 86.4 ;
    END
  END t_lk_cmd[72]
  PIN t_lk_cmd[73]
    DIRECTION OUTPUT ;
    USE SIGNAL ;
    PORT
      LAYER M5 ;
        RECT  27.072 86.316 27.096 86.4 ;
    END
  END t_lk_cmd[73]
  PIN t_lk_cmd[74]
    DIRECTION OUTPUT ;
    USE SIGNAL ;
    PORT
      LAYER M5 ;
        RECT  27.168 86.316 27.192 86.4 ;
    END
  END t_lk_cmd[74]
  PIN t_lk_cmd[75]
    DIRECTION OUTPUT ;
    USE SIGNAL ;
    PORT
      LAYER M5 ;
        RECT  27.264 86.316 27.288 86.4 ;
    END
  END t_lk_cmd[75]
  PIN t_lk_cmd[76]
    DIRECTION OUTPUT ;
    USE SIGNAL ;
    PORT
      LAYER M5 ;
        RECT  27.36 86.316 27.384 86.4 ;
    END
  END t_lk_cmd[76]
  PIN t_lk_cmd[77]
    DIRECTION OUTPUT ;
    USE SIGNAL ;
    PORT
      LAYER M5 ;
        RECT  27.456 86.316 27.48 86.4 ;
    END
  END t_lk_cmd[77]
  PIN t_lk_cmd[78]
    DIRECTION OUTPUT ;
    USE SIGNAL ;
    PORT
      LAYER M5 ;
        RECT  27.552 86.316 27.576 86.4 ;
    END
  END t_lk_cmd[78]
  PIN t_lk_cmd[79]
    DIRECTION OUTPUT ;
    USE SIGNAL ;
    PORT
      LAYER M5 ;
        RECT  27.648 86.316 27.672 86.4 ;
    END
  END t_lk_cmd[79]
  PIN t_lk_cmd[7]
    DIRECTION OUTPUT ;
    USE SIGNAL ;
    PORT
      LAYER M5 ;
        RECT  20.736 86.316 20.76 86.4 ;
    END
  END t_lk_cmd[7]
  PIN t_lk_cmd[80]
    DIRECTION OUTPUT ;
    USE SIGNAL ;
    PORT
      LAYER M5 ;
        RECT  27.744 86.316 27.768 86.4 ;
    END
  END t_lk_cmd[80]
  PIN t_lk_cmd[81]
    DIRECTION OUTPUT ;
    USE SIGNAL ;
    PORT
      LAYER M5 ;
        RECT  27.84 86.316 27.864 86.4 ;
    END
  END t_lk_cmd[81]
  PIN t_lk_cmd[82]
    DIRECTION OUTPUT ;
    USE SIGNAL ;
    PORT
      LAYER M5 ;
        RECT  27.936 86.316 27.96 86.4 ;
    END
  END t_lk_cmd[82]
  PIN t_lk_cmd[83]
    DIRECTION OUTPUT ;
    USE SIGNAL ;
    PORT
      LAYER M5 ;
        RECT  28.032 86.316 28.056 86.4 ;
    END
  END t_lk_cmd[83]
  PIN t_lk_cmd[84]
    DIRECTION OUTPUT ;
    USE SIGNAL ;
    PORT
      LAYER M5 ;
        RECT  28.128 86.316 28.152 86.4 ;
    END
  END t_lk_cmd[84]
  PIN t_lk_cmd[8]
    DIRECTION OUTPUT ;
    USE SIGNAL ;
    PORT
      LAYER M5 ;
        RECT  20.832 86.316 20.856 86.4 ;
    END
  END t_lk_cmd[8]
  PIN t_lk_cmd[9]
    DIRECTION OUTPUT ;
    USE SIGNAL ;
    PORT
      LAYER M5 ;
        RECT  20.928 86.316 20.952 86.4 ;
    END
  END t_lk_cmd[9]
  PIN t_mix_cmd[0]
    DIRECTION OUTPUT ;
    USE SIGNAL ;
    PORT
      LAYER M4 ;
        RECT  0 20.064 0.084 20.088 ;
    END
  END t_mix_cmd[0]
  PIN t_mix_cmd[10]
    DIRECTION OUTPUT ;
    USE SIGNAL ;
    PORT
      LAYER M4 ;
        RECT  0 21.024 0.084 21.048 ;
    END
  END t_mix_cmd[10]
  PIN t_mix_cmd[11]
    DIRECTION OUTPUT ;
    USE SIGNAL ;
    PORT
      LAYER M4 ;
        RECT  0 21.12 0.084 21.144 ;
    END
  END t_mix_cmd[11]
  PIN t_mix_cmd[12]
    DIRECTION OUTPUT ;
    USE SIGNAL ;
    PORT
      LAYER M4 ;
        RECT  0 21.216 0.084 21.24 ;
    END
  END t_mix_cmd[12]
  PIN t_mix_cmd[13]
    DIRECTION OUTPUT ;
    USE SIGNAL ;
    PORT
      LAYER M4 ;
        RECT  0 21.312 0.084 21.336 ;
    END
  END t_mix_cmd[13]
  PIN t_mix_cmd[14]
    DIRECTION OUTPUT ;
    USE SIGNAL ;
    PORT
      LAYER M4 ;
        RECT  0 21.408 0.084 21.432 ;
    END
  END t_mix_cmd[14]
  PIN t_mix_cmd[15]
    DIRECTION OUTPUT ;
    USE SIGNAL ;
    PORT
      LAYER M4 ;
        RECT  0 21.504 0.084 21.528 ;
    END
  END t_mix_cmd[15]
  PIN t_mix_cmd[16]
    DIRECTION OUTPUT ;
    USE SIGNAL ;
    PORT
      LAYER M4 ;
        RECT  0 21.6 0.084 21.624 ;
    END
  END t_mix_cmd[16]
  PIN t_mix_cmd[17]
    DIRECTION OUTPUT ;
    USE SIGNAL ;
    PORT
      LAYER M4 ;
        RECT  0 21.696 0.084 21.72 ;
    END
  END t_mix_cmd[17]
  PIN t_mix_cmd[18]
    DIRECTION OUTPUT ;
    USE SIGNAL ;
    PORT
      LAYER M4 ;
        RECT  0 21.792 0.084 21.816 ;
    END
  END t_mix_cmd[18]
  PIN t_mix_cmd[19]
    DIRECTION OUTPUT ;
    USE SIGNAL ;
    PORT
      LAYER M4 ;
        RECT  0 21.888 0.084 21.912 ;
    END
  END t_mix_cmd[19]
  PIN t_mix_cmd[1]
    DIRECTION OUTPUT ;
    USE SIGNAL ;
    PORT
      LAYER M4 ;
        RECT  0 20.16 0.084 20.184 ;
    END
  END t_mix_cmd[1]
  PIN t_mix_cmd[20]
    DIRECTION OUTPUT ;
    USE SIGNAL ;
    PORT
      LAYER M4 ;
        RECT  0 21.984 0.084 22.008 ;
    END
  END t_mix_cmd[20]
  PIN t_mix_cmd[21]
    DIRECTION OUTPUT ;
    USE SIGNAL ;
    PORT
      LAYER M4 ;
        RECT  0 22.08 0.084 22.104 ;
    END
  END t_mix_cmd[21]
  PIN t_mix_cmd[22]
    DIRECTION OUTPUT ;
    USE SIGNAL ;
    PORT
      LAYER M4 ;
        RECT  0 22.176 0.084 22.2 ;
    END
  END t_mix_cmd[22]
  PIN t_mix_cmd[23]
    DIRECTION OUTPUT ;
    USE SIGNAL ;
    PORT
      LAYER M4 ;
        RECT  0 22.272 0.084 22.296 ;
    END
  END t_mix_cmd[23]
  PIN t_mix_cmd[24]
    DIRECTION OUTPUT ;
    USE SIGNAL ;
    PORT
      LAYER M4 ;
        RECT  0 22.368 0.084 22.392 ;
    END
  END t_mix_cmd[24]
  PIN t_mix_cmd[25]
    DIRECTION OUTPUT ;
    USE SIGNAL ;
    PORT
      LAYER M4 ;
        RECT  0 22.464 0.084 22.488 ;
    END
  END t_mix_cmd[25]
  PIN t_mix_cmd[26]
    DIRECTION OUTPUT ;
    USE SIGNAL ;
    PORT
      LAYER M4 ;
        RECT  0 22.56 0.084 22.584 ;
    END
  END t_mix_cmd[26]
  PIN t_mix_cmd[27]
    DIRECTION OUTPUT ;
    USE SIGNAL ;
    PORT
      LAYER M4 ;
        RECT  0 22.656 0.084 22.68 ;
    END
  END t_mix_cmd[27]
  PIN t_mix_cmd[28]
    DIRECTION OUTPUT ;
    USE SIGNAL ;
    PORT
      LAYER M4 ;
        RECT  0 22.752 0.084 22.776 ;
    END
  END t_mix_cmd[28]
  PIN t_mix_cmd[29]
    DIRECTION OUTPUT ;
    USE SIGNAL ;
    PORT
      LAYER M4 ;
        RECT  0 22.848 0.084 22.872 ;
    END
  END t_mix_cmd[29]
  PIN t_mix_cmd[2]
    DIRECTION OUTPUT ;
    USE SIGNAL ;
    PORT
      LAYER M4 ;
        RECT  0 20.256 0.084 20.28 ;
    END
  END t_mix_cmd[2]
  PIN t_mix_cmd[30]
    DIRECTION OUTPUT ;
    USE SIGNAL ;
    PORT
      LAYER M4 ;
        RECT  0 22.944 0.084 22.968 ;
    END
  END t_mix_cmd[30]
  PIN t_mix_cmd[31]
    DIRECTION OUTPUT ;
    USE SIGNAL ;
    PORT
      LAYER M4 ;
        RECT  0 23.04 0.084 23.064 ;
    END
  END t_mix_cmd[31]
  PIN t_mix_cmd[32]
    DIRECTION OUTPUT ;
    USE SIGNAL ;
    PORT
      LAYER M4 ;
        RECT  0 23.136 0.084 23.16 ;
    END
  END t_mix_cmd[32]
  PIN t_mix_cmd[33]
    DIRECTION OUTPUT ;
    USE SIGNAL ;
    PORT
      LAYER M4 ;
        RECT  0 23.232 0.084 23.256 ;
    END
  END t_mix_cmd[33]
  PIN t_mix_cmd[34]
    DIRECTION OUTPUT ;
    USE SIGNAL ;
    PORT
      LAYER M4 ;
        RECT  0 23.328 0.084 23.352 ;
    END
  END t_mix_cmd[34]
  PIN t_mix_cmd[35]
    DIRECTION OUTPUT ;
    USE SIGNAL ;
    PORT
      LAYER M4 ;
        RECT  0 23.424 0.084 23.448 ;
    END
  END t_mix_cmd[35]
  PIN t_mix_cmd[36]
    DIRECTION OUTPUT ;
    USE SIGNAL ;
    PORT
      LAYER M4 ;
        RECT  0 23.52 0.084 23.544 ;
    END
  END t_mix_cmd[36]
  PIN t_mix_cmd[37]
    DIRECTION OUTPUT ;
    USE SIGNAL ;
    PORT
      LAYER M4 ;
        RECT  0 23.616 0.084 23.64 ;
    END
  END t_mix_cmd[37]
  PIN t_mix_cmd[38]
    DIRECTION OUTPUT ;
    USE SIGNAL ;
    PORT
      LAYER M4 ;
        RECT  0 23.712 0.084 23.736 ;
    END
  END t_mix_cmd[38]
  PIN t_mix_cmd[39]
    DIRECTION OUTPUT ;
    USE SIGNAL ;
    PORT
      LAYER M4 ;
        RECT  0 23.808 0.084 23.832 ;
    END
  END t_mix_cmd[39]
  PIN t_mix_cmd[3]
    DIRECTION OUTPUT ;
    USE SIGNAL ;
    PORT
      LAYER M4 ;
        RECT  0 20.352 0.084 20.376 ;
    END
  END t_mix_cmd[3]
  PIN t_mix_cmd[40]
    DIRECTION OUTPUT ;
    USE SIGNAL ;
    PORT
      LAYER M4 ;
        RECT  0 23.904 0.084 23.928 ;
    END
  END t_mix_cmd[40]
  PIN t_mix_cmd[41]
    DIRECTION OUTPUT ;
    USE SIGNAL ;
    PORT
      LAYER M4 ;
        RECT  0 24 0.084 24.024 ;
    END
  END t_mix_cmd[41]
  PIN t_mix_cmd[42]
    DIRECTION OUTPUT ;
    USE SIGNAL ;
    PORT
      LAYER M4 ;
        RECT  0 24.096 0.084 24.12 ;
    END
  END t_mix_cmd[42]
  PIN t_mix_cmd[43]
    DIRECTION OUTPUT ;
    USE SIGNAL ;
    PORT
      LAYER M4 ;
        RECT  0 24.192 0.084 24.216 ;
    END
  END t_mix_cmd[43]
  PIN t_mix_cmd[44]
    DIRECTION OUTPUT ;
    USE SIGNAL ;
    PORT
      LAYER M4 ;
        RECT  0 24.288 0.084 24.312 ;
    END
  END t_mix_cmd[44]
  PIN t_mix_cmd[45]
    DIRECTION OUTPUT ;
    USE SIGNAL ;
    PORT
      LAYER M4 ;
        RECT  0 24.384 0.084 24.408 ;
    END
  END t_mix_cmd[45]
  PIN t_mix_cmd[46]
    DIRECTION OUTPUT ;
    USE SIGNAL ;
    PORT
      LAYER M4 ;
        RECT  0 24.48 0.084 24.504 ;
    END
  END t_mix_cmd[46]
  PIN t_mix_cmd[47]
    DIRECTION OUTPUT ;
    USE SIGNAL ;
    PORT
      LAYER M4 ;
        RECT  0 24.576 0.084 24.6 ;
    END
  END t_mix_cmd[47]
  PIN t_mix_cmd[48]
    DIRECTION OUTPUT ;
    USE SIGNAL ;
    PORT
      LAYER M4 ;
        RECT  0 24.672 0.084 24.696 ;
    END
  END t_mix_cmd[48]
  PIN t_mix_cmd[49]
    DIRECTION OUTPUT ;
    USE SIGNAL ;
    PORT
      LAYER M4 ;
        RECT  0 24.768 0.084 24.792 ;
    END
  END t_mix_cmd[49]
  PIN t_mix_cmd[4]
    DIRECTION OUTPUT ;
    USE SIGNAL ;
    PORT
      LAYER M4 ;
        RECT  0 20.448 0.084 20.472 ;
    END
  END t_mix_cmd[4]
  PIN t_mix_cmd[50]
    DIRECTION OUTPUT ;
    USE SIGNAL ;
    PORT
      LAYER M4 ;
        RECT  0 24.864 0.084 24.888 ;
    END
  END t_mix_cmd[50]
  PIN t_mix_cmd[51]
    DIRECTION OUTPUT ;
    USE SIGNAL ;
    PORT
      LAYER M4 ;
        RECT  0 24.96 0.084 24.984 ;
    END
  END t_mix_cmd[51]
  PIN t_mix_cmd[52]
    DIRECTION OUTPUT ;
    USE SIGNAL ;
    PORT
      LAYER M4 ;
        RECT  0 25.056 0.084 25.08 ;
    END
  END t_mix_cmd[52]
  PIN t_mix_cmd[53]
    DIRECTION OUTPUT ;
    USE SIGNAL ;
    PORT
      LAYER M4 ;
        RECT  0 25.152 0.084 25.176 ;
    END
  END t_mix_cmd[53]
  PIN t_mix_cmd[54]
    DIRECTION OUTPUT ;
    USE SIGNAL ;
    PORT
      LAYER M4 ;
        RECT  0 25.248 0.084 25.272 ;
    END
  END t_mix_cmd[54]
  PIN t_mix_cmd[55]
    DIRECTION OUTPUT ;
    USE SIGNAL ;
    PORT
      LAYER M4 ;
        RECT  0 25.344 0.084 25.368 ;
    END
  END t_mix_cmd[55]
  PIN t_mix_cmd[56]
    DIRECTION OUTPUT ;
    USE SIGNAL ;
    PORT
      LAYER M4 ;
        RECT  0 25.44 0.084 25.464 ;
    END
  END t_mix_cmd[56]
  PIN t_mix_cmd[57]
    DIRECTION OUTPUT ;
    USE SIGNAL ;
    PORT
      LAYER M4 ;
        RECT  0 25.536 0.084 25.56 ;
    END
  END t_mix_cmd[57]
  PIN t_mix_cmd[58]
    DIRECTION OUTPUT ;
    USE SIGNAL ;
    PORT
      LAYER M4 ;
        RECT  0 25.632 0.084 25.656 ;
    END
  END t_mix_cmd[58]
  PIN t_mix_cmd[59]
    DIRECTION OUTPUT ;
    USE SIGNAL ;
    PORT
      LAYER M4 ;
        RECT  0 25.728 0.084 25.752 ;
    END
  END t_mix_cmd[59]
  PIN t_mix_cmd[5]
    DIRECTION OUTPUT ;
    USE SIGNAL ;
    PORT
      LAYER M4 ;
        RECT  0 20.544 0.084 20.568 ;
    END
  END t_mix_cmd[5]
  PIN t_mix_cmd[60]
    DIRECTION OUTPUT ;
    USE SIGNAL ;
    PORT
      LAYER M4 ;
        RECT  0 25.824 0.084 25.848 ;
    END
  END t_mix_cmd[60]
  PIN t_mix_cmd[61]
    DIRECTION OUTPUT ;
    USE SIGNAL ;
    PORT
      LAYER M4 ;
        RECT  0 25.92 0.084 25.944 ;
    END
  END t_mix_cmd[61]
  PIN t_mix_cmd[62]
    DIRECTION OUTPUT ;
    USE SIGNAL ;
    PORT
      LAYER M4 ;
        RECT  0 26.016 0.084 26.04 ;
    END
  END t_mix_cmd[62]
  PIN t_mix_cmd[63]
    DIRECTION OUTPUT ;
    USE SIGNAL ;
    PORT
      LAYER M4 ;
        RECT  0 26.112 0.084 26.136 ;
    END
  END t_mix_cmd[63]
  PIN t_mix_cmd[64]
    DIRECTION OUTPUT ;
    USE SIGNAL ;
    PORT
      LAYER M4 ;
        RECT  0 26.208 0.084 26.232 ;
    END
  END t_mix_cmd[64]
  PIN t_mix_cmd[65]
    DIRECTION OUTPUT ;
    USE SIGNAL ;
    PORT
      LAYER M4 ;
        RECT  0 26.304 0.084 26.328 ;
    END
  END t_mix_cmd[65]
  PIN t_mix_cmd[66]
    DIRECTION OUTPUT ;
    USE SIGNAL ;
    PORT
      LAYER M4 ;
        RECT  0 26.4 0.084 26.424 ;
    END
  END t_mix_cmd[66]
  PIN t_mix_cmd[67]
    DIRECTION OUTPUT ;
    USE SIGNAL ;
    PORT
      LAYER M4 ;
        RECT  0 26.496 0.084 26.52 ;
    END
  END t_mix_cmd[67]
  PIN t_mix_cmd[68]
    DIRECTION OUTPUT ;
    USE SIGNAL ;
    PORT
      LAYER M4 ;
        RECT  0 26.592 0.084 26.616 ;
    END
  END t_mix_cmd[68]
  PIN t_mix_cmd[69]
    DIRECTION OUTPUT ;
    USE SIGNAL ;
    PORT
      LAYER M4 ;
        RECT  0 26.688 0.084 26.712 ;
    END
  END t_mix_cmd[69]
  PIN t_mix_cmd[6]
    DIRECTION OUTPUT ;
    USE SIGNAL ;
    PORT
      LAYER M4 ;
        RECT  0 20.64 0.084 20.664 ;
    END
  END t_mix_cmd[6]
  PIN t_mix_cmd[70]
    DIRECTION OUTPUT ;
    USE SIGNAL ;
    PORT
      LAYER M4 ;
        RECT  0 26.784 0.084 26.808 ;
    END
  END t_mix_cmd[70]
  PIN t_mix_cmd[71]
    DIRECTION OUTPUT ;
    USE SIGNAL ;
    PORT
      LAYER M4 ;
        RECT  0 26.88 0.084 26.904 ;
    END
  END t_mix_cmd[71]
  PIN t_mix_cmd[72]
    DIRECTION OUTPUT ;
    USE SIGNAL ;
    PORT
      LAYER M4 ;
        RECT  0 26.976 0.084 27 ;
    END
  END t_mix_cmd[72]
  PIN t_mix_cmd[73]
    DIRECTION OUTPUT ;
    USE SIGNAL ;
    PORT
      LAYER M4 ;
        RECT  0 27.072 0.084 27.096 ;
    END
  END t_mix_cmd[73]
  PIN t_mix_cmd[74]
    DIRECTION OUTPUT ;
    USE SIGNAL ;
    PORT
      LAYER M4 ;
        RECT  0 27.168 0.084 27.192 ;
    END
  END t_mix_cmd[74]
  PIN t_mix_cmd[75]
    DIRECTION OUTPUT ;
    USE SIGNAL ;
    PORT
      LAYER M4 ;
        RECT  0 27.264 0.084 27.288 ;
    END
  END t_mix_cmd[75]
  PIN t_mix_cmd[76]
    DIRECTION OUTPUT ;
    USE SIGNAL ;
    PORT
      LAYER M4 ;
        RECT  0 27.36 0.084 27.384 ;
    END
  END t_mix_cmd[76]
  PIN t_mix_cmd[77]
    DIRECTION OUTPUT ;
    USE SIGNAL ;
    PORT
      LAYER M4 ;
        RECT  0 27.456 0.084 27.48 ;
    END
  END t_mix_cmd[77]
  PIN t_mix_cmd[78]
    DIRECTION OUTPUT ;
    USE SIGNAL ;
    PORT
      LAYER M4 ;
        RECT  0 27.552 0.084 27.576 ;
    END
  END t_mix_cmd[78]
  PIN t_mix_cmd[79]
    DIRECTION OUTPUT ;
    USE SIGNAL ;
    PORT
      LAYER M4 ;
        RECT  0 27.648 0.084 27.672 ;
    END
  END t_mix_cmd[79]
  PIN t_mix_cmd[7]
    DIRECTION OUTPUT ;
    USE SIGNAL ;
    PORT
      LAYER M4 ;
        RECT  0 20.736 0.084 20.76 ;
    END
  END t_mix_cmd[7]
  PIN t_mix_cmd[80]
    DIRECTION OUTPUT ;
    USE SIGNAL ;
    PORT
      LAYER M4 ;
        RECT  0 27.744 0.084 27.768 ;
    END
  END t_mix_cmd[80]
  PIN t_mix_cmd[81]
    DIRECTION OUTPUT ;
    USE SIGNAL ;
    PORT
      LAYER M4 ;
        RECT  0 27.84 0.084 27.864 ;
    END
  END t_mix_cmd[81]
  PIN t_mix_cmd[82]
    DIRECTION OUTPUT ;
    USE SIGNAL ;
    PORT
      LAYER M4 ;
        RECT  0 27.936 0.084 27.96 ;
    END
  END t_mix_cmd[82]
  PIN t_mix_cmd[83]
    DIRECTION OUTPUT ;
    USE SIGNAL ;
    PORT
      LAYER M4 ;
        RECT  0 28.032 0.084 28.056 ;
    END
  END t_mix_cmd[83]
  PIN t_mix_cmd[84]
    DIRECTION OUTPUT ;
    USE SIGNAL ;
    PORT
      LAYER M4 ;
        RECT  0 28.128 0.084 28.152 ;
    END
  END t_mix_cmd[84]
  PIN t_mix_cmd[8]
    DIRECTION OUTPUT ;
    USE SIGNAL ;
    PORT
      LAYER M4 ;
        RECT  0 20.832 0.084 20.856 ;
    END
  END t_mix_cmd[8]
  PIN t_mix_cmd[9]
    DIRECTION OUTPUT ;
    USE SIGNAL ;
    PORT
      LAYER M4 ;
        RECT  0 20.928 0.084 20.952 ;
    END
  END t_mix_cmd[9]
  PIN VDD
    DIRECTION INOUT ;
    USE POWER ;
    PORT
      LAYER M5 ;
        RECT  126.792 2.151 126.912 84.249 ;
        RECT  121.392 2.151 121.512 84.249 ;
        RECT  115.992 2.151 116.112 84.249 ;
        RECT  110.592 2.151 110.712 84.249 ;
        RECT  105.192 2.151 105.312 84.249 ;
        RECT  99.792 2.151 99.912 84.249 ;
        RECT  94.392 2.151 94.512 84.249 ;
        RECT  88.992 2.151 89.112 84.249 ;
        RECT  83.592 2.151 83.712 84.249 ;
        RECT  78.192 2.151 78.312 84.249 ;
        RECT  72.792 2.151 72.912 84.249 ;
        RECT  67.392 2.151 67.512 84.249 ;
        RECT  61.992 2.151 62.112 84.249 ;
        RECT  56.592 2.151 56.712 84.249 ;
        RECT  51.192 2.151 51.312 84.249 ;
        RECT  45.792 2.151 45.912 84.249 ;
        RECT  40.392 2.151 40.512 84.249 ;
        RECT  34.992 2.151 35.112 84.249 ;
        RECT  29.592 2.151 29.712 84.249 ;
        RECT  24.192 2.151 24.312 84.249 ;
        RECT  18.792 2.151 18.912 84.249 ;
        RECT  13.392 2.151 13.512 84.249 ;
        RECT  7.992 2.151 8.112 84.249 ;
        RECT  2.592 2.151 2.712 84.249 ;
    END
  END VDD
  PIN VSS
    DIRECTION INOUT ;
    USE GROUND ;
    PORT
      LAYER M5 ;
        RECT  126.6 2.137 126.72 84.263 ;
        RECT  121.2 2.137 121.32 84.263 ;
        RECT  115.8 2.137 115.92 84.263 ;
        RECT  110.4 2.137 110.52 84.263 ;
        RECT  105 2.137 105.12 84.263 ;
        RECT  99.6 2.137 99.72 84.263 ;
        RECT  94.2 2.137 94.32 84.263 ;
        RECT  88.8 2.137 88.92 84.263 ;
        RECT  83.4 2.137 83.52 84.263 ;
        RECT  78 2.137 78.12 84.263 ;
        RECT  72.6 2.137 72.72 84.263 ;
        RECT  67.2 2.137 67.32 84.263 ;
        RECT  61.8 2.137 61.92 84.263 ;
        RECT  56.4 2.137 56.52 84.263 ;
        RECT  51 2.137 51.12 84.263 ;
        RECT  45.6 2.137 45.72 84.263 ;
        RECT  40.2 2.137 40.32 84.263 ;
        RECT  34.8 2.137 34.92 84.263 ;
        RECT  29.4 2.137 29.52 84.263 ;
        RECT  24 2.137 24.12 84.263 ;
        RECT  18.6 2.137 18.72 84.263 ;
        RECT  13.2 2.137 13.32 84.263 ;
        RECT  7.8 2.137 7.92 84.263 ;
        RECT  2.4 2.137 2.52 84.263 ;
    END
  END VSS
  # OT_OBS_CLOSED layer=M5 d_um=1.536 added=100
  OBS
    LAYER RVTN ;
     RECT  2.16 2.16 127.44 2.295 ;
     RECT  2.16 2.565 127.44 2.835 ;
     RECT  2.16 3.105 127.44 3.375 ;
     RECT  2.16 3.645 127.44 3.915 ;
     RECT  2.16 4.185 127.44 4.455 ;
     RECT  2.16 4.725 127.44 4.995 ;
     RECT  2.16 5.265 127.44 5.535 ;
     RECT  2.16 5.805 127.44 6.075 ;
     RECT  2.16 6.345 127.44 6.615 ;
     RECT  2.16 6.885 127.44 7.155 ;
     RECT  2.16 7.425 127.44 7.695 ;
     RECT  2.16 7.965 127.44 8.235 ;
     RECT  2.16 8.505 127.44 8.775 ;
     RECT  2.16 9.045 127.44 9.315 ;
     RECT  2.16 9.585 127.44 9.855 ;
     RECT  2.16 10.125 127.44 10.395 ;
     RECT  2.16 10.665 127.44 10.935 ;
     RECT  2.16 11.205 127.44 11.475 ;
     RECT  2.16 11.745 127.44 12.015 ;
     RECT  2.16 12.285 127.44 12.555 ;
     RECT  2.16 12.825 127.44 13.095 ;
     RECT  2.16 13.365 127.44 13.635 ;
     RECT  2.16 13.905 127.44 14.175 ;
     RECT  2.16 14.445 127.44 14.715 ;
     RECT  2.16 14.985 127.44 15.255 ;
     RECT  2.16 15.525 127.44 15.795 ;
     RECT  2.16 16.065 127.44 16.335 ;
     RECT  2.16 16.605 127.44 16.875 ;
     RECT  2.16 17.145 127.44 17.415 ;
     RECT  2.16 17.685 127.44 17.955 ;
     RECT  2.16 18.225 127.44 18.495 ;
     RECT  2.16 18.765 127.44 19.035 ;
     RECT  2.16 19.305 127.44 19.575 ;
     RECT  2.16 19.845 127.44 20.115 ;
     RECT  2.16 20.385 127.44 20.655 ;
     RECT  2.16 20.925 127.44 21.195 ;
     RECT  2.16 21.465 127.44 21.735 ;
     RECT  2.16 22.005 127.44 22.275 ;
     RECT  2.16 22.545 127.44 22.815 ;
     RECT  2.16 23.085 127.44 23.355 ;
     RECT  2.16 23.625 127.44 23.895 ;
     RECT  2.16 24.165 127.44 24.435 ;
     RECT  2.16 24.705 127.44 24.975 ;
     RECT  2.16 25.245 127.44 25.515 ;
     RECT  2.16 25.785 127.44 26.055 ;
     RECT  2.16 26.325 127.44 26.595 ;
     RECT  2.16 26.865 127.44 27.135 ;
     RECT  2.16 27.405 127.44 27.675 ;
     RECT  2.16 27.945 127.44 28.215 ;
     RECT  2.16 28.485 127.44 28.755 ;
     RECT  2.16 29.025 127.44 29.295 ;
     RECT  2.16 29.565 127.44 29.835 ;
     RECT  2.16 30.105 127.44 30.375 ;
     RECT  2.16 30.645 127.44 30.915 ;
     RECT  2.16 31.185 127.44 31.455 ;
     RECT  2.16 31.725 127.44 31.995 ;
     RECT  2.16 32.265 127.44 32.535 ;
     RECT  2.16 32.805 127.44 33.075 ;
     RECT  2.16 33.345 127.44 33.615 ;
     RECT  2.16 33.885 127.44 34.155 ;
     RECT  2.16 34.425 127.44 34.695 ;
     RECT  2.16 34.965 127.44 35.235 ;
     RECT  2.16 35.505 127.44 35.775 ;
     RECT  2.16 36.045 127.44 36.315 ;
     RECT  2.16 36.585 127.44 36.855 ;
     RECT  2.16 37.125 127.44 37.395 ;
     RECT  2.16 37.665 127.44 37.935 ;
     RECT  2.16 38.205 127.44 38.475 ;
     RECT  2.16 38.745 127.44 39.015 ;
     RECT  2.16 39.285 127.44 39.555 ;
     RECT  2.16 39.825 127.44 40.095 ;
     RECT  2.16 40.365 127.44 40.635 ;
     RECT  2.16 40.905 127.44 41.175 ;
     RECT  2.16 41.445 127.44 41.715 ;
     RECT  2.16 41.985 127.44 42.255 ;
     RECT  2.16 42.525 127.44 42.795 ;
     RECT  2.16 43.065 127.44 43.335 ;
     RECT  2.16 43.605 127.44 43.875 ;
     RECT  2.16 44.145 127.44 44.415 ;
     RECT  2.16 44.685 127.44 44.955 ;
     RECT  2.16 45.225 127.44 45.495 ;
     RECT  2.16 45.765 127.44 46.035 ;
     RECT  2.16 46.305 127.44 46.575 ;
     RECT  2.16 46.845 127.44 47.115 ;
     RECT  2.16 47.385 127.44 47.655 ;
     RECT  2.16 47.925 127.44 48.195 ;
     RECT  2.16 48.465 127.44 48.735 ;
     RECT  2.16 49.005 127.44 49.275 ;
     RECT  2.16 49.545 127.44 49.815 ;
     RECT  2.16 50.085 127.44 50.355 ;
     RECT  2.16 50.625 127.44 50.895 ;
     RECT  2.16 51.165 127.44 51.435 ;
     RECT  2.16 51.705 127.44 51.975 ;
     RECT  2.16 52.245 127.44 52.515 ;
     RECT  2.16 52.785 127.44 53.055 ;
     RECT  2.16 53.325 127.44 53.595 ;
     RECT  2.16 53.865 127.44 54.135 ;
     RECT  2.16 54.405 127.44 54.675 ;
     RECT  2.16 54.945 127.44 55.215 ;
     RECT  2.16 55.485 127.44 55.755 ;
     RECT  2.16 56.025 127.44 56.295 ;
     RECT  2.16 56.565 127.44 56.835 ;
     RECT  2.16 57.105 127.44 57.375 ;
     RECT  2.16 57.645 127.44 57.915 ;
     RECT  2.16 58.185 127.44 58.455 ;
     RECT  2.16 58.725 127.44 58.995 ;
     RECT  2.16 59.265 127.44 59.535 ;
     RECT  2.16 59.805 127.44 60.075 ;
     RECT  2.16 60.345 127.44 60.615 ;
     RECT  2.16 60.885 127.44 61.155 ;
     RECT  2.16 61.425 127.44 61.695 ;
     RECT  2.16 61.965 127.44 62.235 ;
     RECT  2.16 62.505 127.44 62.775 ;
     RECT  2.16 63.045 127.44 63.315 ;
     RECT  2.16 63.585 127.44 63.855 ;
     RECT  2.16 64.125 127.44 64.395 ;
     RECT  2.16 64.665 127.44 64.935 ;
     RECT  2.16 65.205 127.44 65.475 ;
     RECT  2.16 65.745 127.44 66.015 ;
     RECT  2.16 66.285 127.44 66.555 ;
     RECT  2.16 66.825 127.44 67.095 ;
     RECT  2.16 67.365 127.44 67.635 ;
     RECT  2.16 67.905 127.44 68.175 ;
     RECT  2.16 68.445 127.44 68.715 ;
     RECT  2.16 68.985 127.44 69.255 ;
     RECT  2.16 69.525 127.44 69.795 ;
     RECT  2.16 70.065 127.44 70.335 ;
     RECT  2.16 70.605 127.44 70.875 ;
     RECT  2.16 71.145 127.44 71.415 ;
     RECT  2.16 71.685 127.44 71.955 ;
     RECT  2.16 72.225 127.44 72.495 ;
     RECT  2.16 72.765 127.44 73.035 ;
     RECT  2.16 73.305 127.44 73.575 ;
     RECT  2.16 73.845 127.44 74.115 ;
     RECT  2.16 74.385 127.44 74.655 ;
     RECT  2.16 74.925 127.44 75.195 ;
     RECT  2.16 75.465 127.44 75.735 ;
     RECT  2.16 76.005 127.44 76.275 ;
     RECT  2.16 76.545 127.44 76.815 ;
     RECT  2.16 77.085 127.44 77.355 ;
     RECT  2.16 77.625 127.44 77.895 ;
     RECT  2.16 78.165 127.44 78.435 ;
     RECT  2.16 78.705 127.44 78.975 ;
     RECT  2.16 79.245 127.44 79.515 ;
     RECT  2.16 79.785 127.44 80.055 ;
     RECT  2.16 80.325 127.44 80.595 ;
     RECT  2.16 80.865 127.44 81.135 ;
     RECT  2.16 81.405 127.44 81.675 ;
     RECT  2.16 81.945 127.44 82.215 ;
     RECT  2.16 82.485 127.44 82.755 ;
     RECT  2.16 83.025 127.44 83.295 ;
     RECT  2.16 83.565 127.44 83.835 ;
     RECT  2.16 84.105 127.44 84.24 ;
    LAYER RVTP ;
     RECT  2.16 2.295 127.44 2.565 ;
     RECT  2.16 2.835 127.44 3.105 ;
     RECT  2.16 3.375 127.44 3.645 ;
     RECT  2.16 3.915 127.44 4.185 ;
     RECT  2.16 4.455 127.44 4.725 ;
     RECT  2.16 4.995 127.44 5.265 ;
     RECT  2.16 5.535 127.44 5.805 ;
     RECT  2.16 6.075 127.44 6.345 ;
     RECT  2.16 6.615 127.44 6.885 ;
     RECT  2.16 7.155 127.44 7.425 ;
     RECT  2.16 7.695 127.44 7.965 ;
     RECT  2.16 8.235 127.44 8.505 ;
     RECT  2.16 8.775 127.44 9.045 ;
     RECT  2.16 9.315 127.44 9.585 ;
     RECT  2.16 9.855 127.44 10.125 ;
     RECT  2.16 10.395 127.44 10.665 ;
     RECT  2.16 10.935 127.44 11.205 ;
     RECT  2.16 11.475 127.44 11.745 ;
     RECT  2.16 12.015 127.44 12.285 ;
     RECT  2.16 12.555 127.44 12.825 ;
     RECT  2.16 13.095 127.44 13.365 ;
     RECT  2.16 13.635 127.44 13.905 ;
     RECT  2.16 14.175 127.44 14.445 ;
     RECT  2.16 14.715 127.44 14.985 ;
     RECT  2.16 15.255 127.44 15.525 ;
     RECT  2.16 15.795 127.44 16.065 ;
     RECT  2.16 16.335 127.44 16.605 ;
     RECT  2.16 16.875 127.44 17.145 ;
     RECT  2.16 17.415 127.44 17.685 ;
     RECT  2.16 17.955 127.44 18.225 ;
     RECT  2.16 18.495 127.44 18.765 ;
     RECT  2.16 19.035 127.44 19.305 ;
     RECT  2.16 19.575 127.44 19.845 ;
     RECT  2.16 20.115 127.44 20.385 ;
     RECT  2.16 20.655 127.44 20.925 ;
     RECT  2.16 21.195 127.44 21.465 ;
     RECT  2.16 21.735 127.44 22.005 ;
     RECT  2.16 22.275 127.44 22.545 ;
     RECT  2.16 22.815 127.44 23.085 ;
     RECT  2.16 23.355 127.44 23.625 ;
     RECT  2.16 23.895 127.44 24.165 ;
     RECT  2.16 24.435 127.44 24.705 ;
     RECT  2.16 24.975 127.44 25.245 ;
     RECT  2.16 25.515 127.44 25.785 ;
     RECT  2.16 26.055 127.44 26.325 ;
     RECT  2.16 26.595 127.44 26.865 ;
     RECT  2.16 27.135 127.44 27.405 ;
     RECT  2.16 27.675 127.44 27.945 ;
     RECT  2.16 28.215 127.44 28.485 ;
     RECT  2.16 28.755 127.44 29.025 ;
     RECT  2.16 29.295 127.44 29.565 ;
     RECT  2.16 29.835 127.44 30.105 ;
     RECT  2.16 30.375 127.44 30.645 ;
     RECT  2.16 30.915 127.44 31.185 ;
     RECT  2.16 31.455 127.44 31.725 ;
     RECT  2.16 31.995 127.44 32.265 ;
     RECT  2.16 32.535 127.44 32.805 ;
     RECT  2.16 33.075 127.44 33.345 ;
     RECT  2.16 33.615 127.44 33.885 ;
     RECT  2.16 34.155 127.44 34.425 ;
     RECT  2.16 34.695 127.44 34.965 ;
     RECT  2.16 35.235 127.44 35.505 ;
     RECT  2.16 35.775 127.44 36.045 ;
     RECT  2.16 36.315 127.44 36.585 ;
     RECT  2.16 36.855 127.44 37.125 ;
     RECT  2.16 37.395 127.44 37.665 ;
     RECT  2.16 37.935 127.44 38.205 ;
     RECT  2.16 38.475 127.44 38.745 ;
     RECT  2.16 39.015 127.44 39.285 ;
     RECT  2.16 39.555 127.44 39.825 ;
     RECT  2.16 40.095 127.44 40.365 ;
     RECT  2.16 40.635 127.44 40.905 ;
     RECT  2.16 41.175 127.44 41.445 ;
     RECT  2.16 41.715 127.44 41.985 ;
     RECT  2.16 42.255 127.44 42.525 ;
     RECT  2.16 42.795 127.44 43.065 ;
     RECT  2.16 43.335 127.44 43.605 ;
     RECT  2.16 43.875 127.44 44.145 ;
     RECT  2.16 44.415 127.44 44.685 ;
     RECT  2.16 44.955 127.44 45.225 ;
     RECT  2.16 45.495 127.44 45.765 ;
     RECT  2.16 46.035 127.44 46.305 ;
     RECT  2.16 46.575 127.44 46.845 ;
     RECT  2.16 47.115 127.44 47.385 ;
     RECT  2.16 47.655 127.44 47.925 ;
     RECT  2.16 48.195 127.44 48.465 ;
     RECT  2.16 48.735 127.44 49.005 ;
     RECT  2.16 49.275 127.44 49.545 ;
     RECT  2.16 49.815 127.44 50.085 ;
     RECT  2.16 50.355 127.44 50.625 ;
     RECT  2.16 50.895 127.44 51.165 ;
     RECT  2.16 51.435 127.44 51.705 ;
     RECT  2.16 51.975 127.44 52.245 ;
     RECT  2.16 52.515 127.44 52.785 ;
     RECT  2.16 53.055 127.44 53.325 ;
     RECT  2.16 53.595 127.44 53.865 ;
     RECT  2.16 54.135 127.44 54.405 ;
     RECT  2.16 54.675 127.44 54.945 ;
     RECT  2.16 55.215 127.44 55.485 ;
     RECT  2.16 55.755 127.44 56.025 ;
     RECT  2.16 56.295 127.44 56.565 ;
     RECT  2.16 56.835 127.44 57.105 ;
     RECT  2.16 57.375 127.44 57.645 ;
     RECT  2.16 57.915 127.44 58.185 ;
     RECT  2.16 58.455 127.44 58.725 ;
     RECT  2.16 58.995 127.44 59.265 ;
     RECT  2.16 59.535 127.44 59.805 ;
     RECT  2.16 60.075 127.44 60.345 ;
     RECT  2.16 60.615 127.44 60.885 ;
     RECT  2.16 61.155 127.44 61.425 ;
     RECT  2.16 61.695 127.44 61.965 ;
     RECT  2.16 62.235 127.44 62.505 ;
     RECT  2.16 62.775 127.44 63.045 ;
     RECT  2.16 63.315 127.44 63.585 ;
     RECT  2.16 63.855 127.44 64.125 ;
     RECT  2.16 64.395 127.44 64.665 ;
     RECT  2.16 64.935 127.44 65.205 ;
     RECT  2.16 65.475 127.44 65.745 ;
     RECT  2.16 66.015 127.44 66.285 ;
     RECT  2.16 66.555 127.44 66.825 ;
     RECT  2.16 67.095 127.44 67.365 ;
     RECT  2.16 67.635 127.44 67.905 ;
     RECT  2.16 68.175 127.44 68.445 ;
     RECT  2.16 68.715 127.44 68.985 ;
     RECT  2.16 69.255 127.44 69.525 ;
     RECT  2.16 69.795 127.44 70.065 ;
     RECT  2.16 70.335 127.44 70.605 ;
     RECT  2.16 70.875 127.44 71.145 ;
     RECT  2.16 71.415 127.44 71.685 ;
     RECT  2.16 71.955 127.44 72.225 ;
     RECT  2.16 72.495 127.44 72.765 ;
     RECT  2.16 73.035 127.44 73.305 ;
     RECT  2.16 73.575 127.44 73.845 ;
     RECT  2.16 74.115 127.44 74.385 ;
     RECT  2.16 74.655 127.44 74.925 ;
     RECT  2.16 75.195 127.44 75.465 ;
     RECT  2.16 75.735 127.44 76.005 ;
     RECT  2.16 76.275 127.44 76.545 ;
     RECT  2.16 76.815 127.44 77.085 ;
     RECT  2.16 77.355 127.44 77.625 ;
     RECT  2.16 77.895 127.44 78.165 ;
     RECT  2.16 78.435 127.44 78.705 ;
     RECT  2.16 78.975 127.44 79.245 ;
     RECT  2.16 79.515 127.44 79.785 ;
     RECT  2.16 80.055 127.44 80.325 ;
     RECT  2.16 80.595 127.44 80.865 ;
     RECT  2.16 81.135 127.44 81.405 ;
     RECT  2.16 81.675 127.44 81.945 ;
     RECT  2.16 82.215 127.44 82.485 ;
     RECT  2.16 82.755 127.44 83.025 ;
     RECT  2.16 83.295 127.44 83.565 ;
     RECT  2.16 83.835 127.44 84.105 ;
    LAYER M1 ;
     RECT  2.16 2.151 127.44 84.249 ;
    LAYER M2 ;
     RECT  0.031 18.666 0.103 18.684 ;
     RECT  0.103 18.666 0.139 19.224 ;
     RECT  0.103 28.8 0.139 28.818 ;
     RECT  0.139 28.422 0.175 28.818 ;
     RECT  0.103 21.636 0.203 23.346 ;
     RECT  0.103 25.326 0.203 25.47 ;
     RECT  0.103 27.306 0.203 27.324 ;
     RECT  0.203 21.636 0.211 22.734 ;
     RECT  0.203 25.326 0.347 25.344 ;
     RECT  0.175 28.422 1.399 28.98 ;
     RECT  1.399 28.296 1.723 28.98 ;
     RECT  1.723 27.954 1.975 28.98 ;
     RECT  1.975 27.954 2.011 29.052 ;
     RECT  0.139 18.666 2.16 19.494 ;
     RECT  0.103 20.358 2.16 20.376 ;
     RECT  0.211 21.366 2.16 22.734 ;
     RECT  1.759 23.706 2.16 23.724 ;
     RECT  1.723 26.334 2.16 26.352 ;
     RECT  2.011 27.954 2.16 29.214 ;
     RECT  1.759 30.006 2.16 30.024 ;
     RECT  2.16 2.151 18.571 84.249 ;
     RECT  18.571 2.151 19.967 84.366 ;
     RECT  19.967 2.151 20.543 84.294 ;
     RECT  20.543 2.151 127.44 84.249 ;
     RECT  127.44 19.818 127.751 31.914 ;
     RECT  127.751 19.89 128.255 31.914 ;
     RECT  128.255 19.89 128.291 30.564 ;
     RECT  128.291 19.89 128.687 25.272 ;
     RECT  128.291 26.1 128.723 28.854 ;
     RECT  128.687 19.89 128.795 22.914 ;
     RECT  128.723 28.026 128.795 28.854 ;
     RECT  128.291 29.61 128.795 30.564 ;
     RECT  128.255 31.626 128.795 31.914 ;
     RECT  128.795 19.89 128.831 22.878 ;
     RECT  128.687 23.67 128.831 25.272 ;
     RECT  128.723 26.1 128.831 27.234 ;
     RECT  128.795 29.736 128.831 30.564 ;
     RECT  128.795 31.896 128.831 31.914 ;
     RECT  128.831 20.898 128.867 22.878 ;
     RECT  128.867 22.86 128.903 22.878 ;
     RECT  128.831 26.37 129.443 27.234 ;
     RECT  128.831 24.21 129.479 25.002 ;
     RECT  128.867 20.898 129.515 21.834 ;
     RECT  129.479 24.21 129.515 24.228 ;
     RECT  129.479 24.984 129.515 25.002 ;
     RECT  129.443 26.64 129.515 27.234 ;
     RECT  128.795 28.026 129.515 28.674 ;
     RECT  128.831 30.456 129.515 30.474 ;
    LAYER M3 ;
     RECT  2.415 2.143 2.505 2.413 ;
     RECT  7.815 2.143 7.905 2.413 ;
     RECT  13.215 2.143 13.305 2.413 ;
     RECT  18.615 2.143 18.705 2.413 ;
     RECT  24.015 2.143 24.105 2.413 ;
     RECT  29.415 2.143 29.505 2.413 ;
     RECT  34.815 2.143 34.905 2.413 ;
     RECT  40.215 2.143 40.305 2.413 ;
     RECT  45.615 2.143 45.705 2.413 ;
     RECT  51.015 2.143 51.105 2.413 ;
     RECT  56.415 2.143 56.505 2.413 ;
     RECT  61.815 2.143 61.905 2.413 ;
     RECT  67.215 2.143 67.305 2.413 ;
     RECT  72.615 2.143 72.705 2.413 ;
     RECT  78.015 2.143 78.105 2.413 ;
     RECT  83.415 2.143 83.505 2.413 ;
     RECT  88.815 2.143 88.905 2.413 ;
     RECT  94.215 2.143 94.305 2.413 ;
     RECT  99.615 2.143 99.705 2.413 ;
     RECT  105.015 2.143 105.105 2.413 ;
     RECT  110.415 2.143 110.505 2.413 ;
     RECT  115.815 2.143 115.905 2.413 ;
     RECT  121.215 2.143 121.305 2.413 ;
     RECT  126.615 2.143 126.705 2.413 ;
     RECT  6.84 6.283 6.858 6.575 ;
     RECT  6.948 6.691 6.966 13.055 ;
     RECT  2.415 2.413 2.697 18.805 ;
     RECT  0.036 18.661 0.054 18.931 ;
     RECT  7.815 2.413 8.097 18.931 ;
     RECT  8.82 13.063 8.838 18.931 ;
     RECT  2.415 18.805 2.754 19.075 ;
     RECT  6.804 18.931 6.822 19.103 ;
     RECT  2.415 19.075 2.862 19.111 ;
     RECT  4.032 18.931 4.05 19.111 ;
     RECT  108.144 19.201 108.342 19.277 ;
     RECT  108.144 19.277 108.162 19.325 ;
     RECT  2.376 19.111 4.05 19.345 ;
     RECT  124.56 19.201 124.578 19.345 ;
     RECT  2.304 19.345 4.05 19.471 ;
     RECT  13.215 2.413 13.497 19.579 ;
     RECT  125.352 19.291 125.37 19.579 ;
     RECT  124.2 19.345 124.578 19.651 ;
     RECT  125.316 19.579 125.37 19.651 ;
     RECT  126.615 2.413 126.897 19.651 ;
     RECT  5.04 19.651 5.058 19.741 ;
     RECT  16.236 19.651 16.434 19.741 ;
     RECT  5.04 19.741 5.238 19.769 ;
     RECT  13.215 19.579 13.554 19.777 ;
     RECT  16.128 19.741 16.434 19.777 ;
     RECT  107.604 19.741 107.802 19.805 ;
     RECT  13.215 19.777 14.13 19.813 ;
     RECT  15.12 19.579 15.138 19.813 ;
     RECT  16.128 19.777 16.83 19.813 ;
     RECT  5.22 19.769 5.238 19.841 ;
     RECT  107.604 19.805 107.622 19.853 ;
     RECT  2.304 19.471 4.266 19.885 ;
     RECT  6.768 19.471 6.786 19.885 ;
     RECT  7.815 18.931 8.838 19.885 ;
     RECT  12.168 19.471 12.186 19.885 ;
     RECT  123.768 19.651 126.897 19.912 ;
     RECT  11.88 19.885 12.402 19.921 ;
     RECT  16.02 19.813 16.83 19.921 ;
     RECT  0.036 18.931 0.234 19.997 ;
     RECT  16.02 19.921 17.118 20.011 ;
     RECT  6.768 19.885 8.838 20.047 ;
     RECT  9.864 19.651 9.882 20.047 ;
     RECT  10.8 19.921 12.402 20.047 ;
     RECT  13.215 19.813 15.138 20.047 ;
     RECT  16.02 20.011 17.154 20.047 ;
     RECT  123.696 19.912 126.897 20.083 ;
     RECT  6.732 20.047 8.838 20.107 ;
     RECT  26.316 20.047 27.378 20.107 ;
     RECT  9.864 20.047 12.402 20.119 ;
     RECT  13.215 20.047 17.154 20.119 ;
     RECT  26.316 20.107 27.81 20.119 ;
     RECT  127.728 19.813 127.746 20.149 ;
     RECT  5.724 20.107 8.838 20.155 ;
     RECT  9.864 20.119 17.19 20.155 ;
     RECT  26.316 20.119 27.882 20.155 ;
     RECT  28.62 20.047 28.638 20.155 ;
     RECT  105.015 2.413 105.297 20.155 ;
     RECT  9.864 20.155 17.478 20.191 ;
     RECT  18.615 2.413 18.897 20.191 ;
     RECT  25.02 20.011 25.038 20.191 ;
     RECT  26.064 20.155 28.638 20.191 ;
     RECT  29.415 2.413 29.697 20.191 ;
     RECT  5.724 20.155 9.09 20.281 ;
     RECT  9.864 20.191 18.897 20.281 ;
     RECT  106.344 20.155 106.362 20.281 ;
     RECT  105.015 20.155 105.462 20.309 ;
     RECT  107.496 20.107 107.514 20.309 ;
     RECT  22.788 20.191 22.806 20.317 ;
     RECT  24.015 2.413 24.297 20.317 ;
     RECT  109.044 20.299 109.062 20.345 ;
     RECT  122.544 20.047 122.562 20.389 ;
     RECT  123.408 20.083 126.897 20.389 ;
     RECT  34.815 2.413 35.097 20.443 ;
     RECT  45.615 2.413 45.897 20.443 ;
     RECT  56.415 2.413 56.697 20.443 ;
     RECT  67.215 2.413 67.497 20.443 ;
     RECT  78.015 2.413 78.297 20.443 ;
     RECT  88.815 2.413 89.097 20.443 ;
     RECT  99.615 2.413 99.897 20.443 ;
     RECT  22.788 20.317 22.842 20.461 ;
     RECT  23.58 20.317 24.297 20.461 ;
     RECT  102.6 20.299 102.618 20.477 ;
     RECT  127.692 20.149 127.746 20.477 ;
     RECT  34.704 20.443 35.097 20.489 ;
     RECT  45.504 20.443 45.897 20.489 ;
     RECT  56.304 20.443 56.697 20.489 ;
     RECT  67.104 20.443 67.497 20.489 ;
     RECT  77.904 20.443 78.297 20.489 ;
     RECT  88.704 20.443 89.097 20.489 ;
     RECT  99.504 20.443 99.897 20.489 ;
     RECT  109.224 20.395 109.242 20.489 ;
     RECT  0.108 19.997 0.234 20.539 ;
     RECT  26.064 20.191 29.697 20.539 ;
     RECT  30.744 20.347 30.762 20.539 ;
     RECT  2.268 19.885 4.266 20.551 ;
     RECT  5.724 20.281 18.897 20.551 ;
     RECT  19.728 20.119 19.746 20.551 ;
     RECT  22.788 20.461 24.297 20.551 ;
     RECT  25.02 20.191 25.11 20.551 ;
     RECT  106.344 20.281 106.542 20.551 ;
     RECT  107.316 20.461 107.334 20.551 ;
     RECT  127.728 20.477 127.746 20.573 ;
     RECT  2.268 20.551 4.59 20.587 ;
     RECT  22.788 20.551 25.11 20.587 ;
     RECT  121.215 2.413 121.497 20.587 ;
     RECT  122.544 20.389 126.897 20.587 ;
     RECT  128.808 19.885 128.826 20.635 ;
     RECT  2.268 20.587 4.662 20.659 ;
     RECT  22.788 20.587 25.254 20.659 ;
     RECT  0.108 20.539 0.342 20.669 ;
     RECT  106.344 20.551 107.334 20.669 ;
     RECT  22.428 20.659 25.254 20.695 ;
     RECT  121.215 20.587 126.897 20.695 ;
     RECT  2.268 20.659 4.914 20.731 ;
     RECT  5.724 20.551 19.746 20.731 ;
     RECT  128.232 20.635 128.826 20.731 ;
     RECT  2.268 20.731 4.986 20.821 ;
     RECT  5.724 20.731 20.43 20.821 ;
     RECT  106.344 20.669 106.614 20.821 ;
     RECT  106.2 20.821 106.614 20.861 ;
     RECT  2.268 20.821 20.43 20.893 ;
     RECT  118.62 20.827 118.638 20.929 ;
     RECT  121.14 20.695 126.897 20.957 ;
     RECT  2.268 20.893 20.502 20.965 ;
     RECT  21.528 20.695 25.254 20.965 ;
     RECT  26.064 20.539 30.762 20.965 ;
     RECT  2.268 20.965 25.254 21.001 ;
     RECT  26.064 20.965 30.978 21.001 ;
     RECT  106.596 20.861 106.614 21.029 ;
     RECT  118.584 20.929 118.638 21.029 ;
     RECT  128.232 20.731 129.51 21.245 ;
     RECT  129.42 21.245 129.51 21.263 ;
     RECT  2.268 21.001 30.978 21.271 ;
     RECT  108.72 21.271 108.738 21.361 ;
     RECT  115.815 2.413 116.097 21.361 ;
     RECT  121.14 20.957 121.734 21.361 ;
     RECT  108.72 21.361 108.918 21.389 ;
     RECT  2.268 21.271 31.446 21.397 ;
     RECT  128.232 21.245 128.25 21.403 ;
     RECT  2.268 21.397 31.518 21.433 ;
     RECT  110.415 2.413 110.697 21.433 ;
     RECT  115.812 21.361 116.097 21.433 ;
     RECT  107.424 21.199 107.442 21.469 ;
     RECT  108.9 21.389 108.918 21.485 ;
     RECT  115.632 21.433 116.097 21.485 ;
     RECT  2.268 21.433 31.59 21.496 ;
     RECT  110.415 21.433 110.826 21.505 ;
     RECT  2.268 21.496 31.662 21.533 ;
     RECT  120.348 21.361 121.734 21.533 ;
     RECT  109.044 21.505 110.826 21.541 ;
     RECT  128.196 21.403 128.25 21.595 ;
     RECT  2.268 21.533 31.374 21.629 ;
     RECT  2.34 21.629 31.374 21.659 ;
     RECT  102.672 21.541 102.69 21.659 ;
     RECT  107.424 21.469 107.622 21.659 ;
     RECT  109.044 21.541 111.402 21.659 ;
     RECT  118.62 21.029 118.638 21.659 ;
     RECT  121.104 21.533 121.734 21.811 ;
     RECT  122.508 20.957 126.897 21.811 ;
     RECT  109.044 21.659 109.638 21.839 ;
     RECT  129.492 21.263 129.51 21.839 ;
     RECT  128.16 21.595 128.25 21.883 ;
     RECT  106.2 21.739 106.218 21.929 ;
     RECT  109.044 21.839 109.53 21.929 ;
     RECT  120.348 21.533 120.366 21.965 ;
     RECT  127.656 21.883 128.25 21.979 ;
     RECT  112.464 21.901 112.878 22.013 ;
     RECT  112.464 22.013 112.482 22.061 ;
     RECT  34.815 20.489 35.097 22.072 ;
     RECT  45.615 20.489 45.897 22.072 ;
     RECT  56.415 20.489 56.697 22.072 ;
     RECT  67.215 20.489 67.497 22.072 ;
     RECT  78.015 20.489 78.297 22.072 ;
     RECT  88.815 20.489 89.097 22.072 ;
     RECT  99.615 20.489 99.897 22.072 ;
     RECT  121.104 21.811 126.897 22.075 ;
     RECT  127.62 21.979 128.25 22.075 ;
     RECT  109.224 21.929 109.53 22.109 ;
     RECT  121.104 22.075 128.25 22.109 ;
     RECT  118.584 22.081 118.602 22.199 ;
     RECT  106.596 22.081 106.614 22.205 ;
     RECT  45.504 22.072 45.897 22.208 ;
     RECT  56.304 22.072 56.697 22.208 ;
     RECT  67.104 22.072 67.497 22.208 ;
     RECT  77.904 22.072 78.297 22.208 ;
     RECT  88.704 22.072 89.097 22.208 ;
     RECT  99.504 22.072 99.897 22.208 ;
     RECT  121.215 22.109 128.25 22.267 ;
     RECT  109.332 22.109 109.53 22.469 ;
     RECT  110.415 21.659 111.186 22.469 ;
     RECT  34.704 22.072 35.097 22.477 ;
     RECT  0.108 20.669 0.234 22.493 ;
     RECT  110.415 22.469 111.006 22.505 ;
     RECT  109.512 22.469 109.53 22.541 ;
     RECT  2.34 21.659 31.122 22.549 ;
     RECT  31.86 22.513 31.878 22.549 ;
     RECT  72.615 2.413 72.897 22.549 ;
     RECT  33.12 22.513 33.138 22.585 ;
     RECT  34.632 22.477 35.097 22.621 ;
     RECT  36.396 22.477 36.414 22.621 ;
     RECT  2.34 22.549 31.878 22.651 ;
     RECT  65.16 22.441 65.61 22.685 ;
     RECT  65.592 22.685 65.61 22.739 ;
     RECT  72.36 22.549 72.897 22.739 ;
     RECT  38.268 22.711 38.286 22.783 ;
     RECT  70.128 22.747 70.146 22.784 ;
     RECT  33.12 22.585 33.318 22.819 ;
     RECT  34.632 22.621 36.414 22.819 ;
     RECT  38.088 22.783 38.286 22.819 ;
     RECT  39.384 22.549 39.402 22.819 ;
     RECT  32.688 22.819 36.414 22.855 ;
     RECT  121.215 22.267 128.862 22.855 ;
     RECT  32.652 22.855 36.414 22.891 ;
     RECT  2.304 22.651 31.878 23.017 ;
     RECT  32.652 22.891 37.062 23.017 ;
     RECT  38.088 22.819 39.402 23.053 ;
     RECT  121.215 22.855 128.898 23.069 ;
     RECT  43.596 21.127 43.614 23.089 ;
     RECT  38.088 23.053 39.474 23.125 ;
     RECT  40.215 2.413 40.497 23.125 ;
     RECT  112.14 23.083 112.158 23.131 ;
     RECT  43.596 23.089 43.722 23.161 ;
     RECT  2.304 23.017 37.242 23.251 ;
     RECT  38.088 23.125 40.497 23.251 ;
     RECT  0.108 22.493 0.162 23.275 ;
     RECT  42.084 23.089 42.102 23.279 ;
     RECT  112.14 23.131 112.338 23.279 ;
     RECT  121.215 23.069 128.826 23.287 ;
     RECT  2.304 23.251 40.497 23.323 ;
     RECT  41.256 23.251 41.274 23.323 ;
     RECT  0.108 23.275 0.198 23.351 ;
     RECT  43.2 23.161 43.722 23.359 ;
     RECT  51.015 2.413 51.297 23.359 ;
     RECT  2.304 23.323 41.274 23.395 ;
     RECT  45.615 22.208 45.897 23.395 ;
     RECT  45.576 23.395 46.206 23.431 ;
     RECT  50.76 23.359 51.297 23.431 ;
     RECT  50.616 23.431 51.297 23.521 ;
     RECT  0.144 23.351 0.198 23.549 ;
     RECT  45.576 23.431 46.782 23.557 ;
     RECT  118.62 22.891 118.638 23.557 ;
     RECT  1.26 23.419 1.278 23.611 ;
     RECT  2.304 23.395 41.958 23.611 ;
     RECT  1.26 23.611 41.958 23.621 ;
     RECT  42.732 23.359 43.722 23.621 ;
     RECT  48.456 23.359 48.474 23.629 ;
     RECT  50.112 23.521 51.297 23.629 ;
     RECT  42.876 23.621 43.722 23.693 ;
     RECT  120.564 23.287 128.826 23.693 ;
     RECT  45.576 23.557 46.854 23.701 ;
     RECT  118.584 23.557 118.638 23.701 ;
     RECT  48.456 23.629 51.297 23.819 ;
     RECT  120.564 23.693 128.718 23.891 ;
     RECT  42.912 23.693 43.722 23.899 ;
     RECT  45.18 23.701 46.854 23.899 ;
     RECT  47.664 23.791 47.682 23.899 ;
     RECT  0.324 23.803 0.342 23.933 ;
     RECT  42.912 23.899 43.83 23.935 ;
     RECT  45 23.899 47.682 23.935 ;
     RECT  48.456 23.819 49.05 23.935 ;
     RECT  37.44 23.621 41.958 24.061 ;
     RECT  52.02 23.935 52.038 24.089 ;
     RECT  49.86 23.819 51.297 24.097 ;
     RECT  120.564 23.891 128.25 24.125 ;
     RECT  1.26 23.621 36.378 24.139 ;
     RECT  118.584 23.701 118.674 24.169 ;
     RECT  42.912 23.935 43.938 24.187 ;
     RECT  49.86 24.097 51.93 24.233 ;
     RECT  118.584 24.169 118.746 24.269 ;
     RECT  118.584 24.269 118.674 24.395 ;
     RECT  37.44 24.061 42.102 24.403 ;
     RECT  37.44 24.403 42.174 24.439 ;
     RECT  37.26 24.439 42.174 24.475 ;
     RECT  129.492 23.803 129.51 24.475 ;
     RECT  118.584 24.395 118.602 24.503 ;
     RECT  121.068 24.125 128.25 24.503 ;
     RECT  1.152 24.139 36.378 24.511 ;
     RECT  37.188 24.475 42.174 24.511 ;
     RECT  42.912 24.187 44.01 24.511 ;
     RECT  45 23.935 49.05 24.511 ;
     RECT  49.86 24.233 51.858 24.665 ;
     RECT  129.456 24.475 129.51 24.667 ;
     RECT  56.415 22.208 56.697 24.763 ;
     RECT  67.215 22.208 67.497 24.763 ;
     RECT  78.015 22.208 78.297 24.763 ;
     RECT  88.815 22.208 89.097 24.763 ;
     RECT  99.615 22.208 99.897 24.763 ;
     RECT  110.415 22.505 110.697 24.763 ;
     RECT  121.104 24.503 128.25 24.763 ;
     RECT  129.42 24.667 129.51 24.763 ;
     RECT  1.152 24.511 49.05 24.781 ;
     RECT  54.72 24.601 54.738 24.809 ;
     RECT  56.304 24.763 56.697 24.809 ;
     RECT  67.104 24.763 67.497 24.809 ;
     RECT  77.904 24.763 78.297 24.809 ;
     RECT  88.704 24.763 89.097 24.809 ;
     RECT  99.504 24.763 99.897 24.809 ;
     RECT  110.304 24.763 110.697 24.809 ;
     RECT  121.104 24.763 129.51 24.809 ;
     RECT  1.152 24.781 49.194 24.899 ;
     RECT  1.152 24.899 48.942 24.941 ;
     RECT  113.436 24.871 113.454 24.941 ;
     RECT  113.256 24.955 113.274 25.007 ;
     RECT  121.215 24.809 129.51 25.007 ;
     RECT  49.968 24.665 51.858 25.037 ;
     RECT  49.968 25.037 51.297 25.043 ;
     RECT  54.684 24.943 54.702 25.043 ;
     RECT  0.324 25.147 0.342 25.243 ;
     RECT  52.776 25.321 52.794 25.387 ;
     RECT  52.74 25.387 52.794 25.411 ;
     RECT  0.108 25.243 0.342 25.469 ;
     RECT  0.108 25.469 0.27 25.475 ;
     RECT  0.18 25.475 0.27 25.613 ;
     RECT  0.252 25.613 0.27 25.661 ;
     RECT  54.288 25.555 54.306 25.681 ;
     RECT  121.215 25.007 129.438 25.681 ;
     RECT  118.62 25.249 118.638 25.717 ;
     RECT  61.815 2.413 62.097 25.753 ;
     RECT  118.62 25.717 118.674 25.789 ;
     RECT  118.62 25.789 118.746 25.819 ;
     RECT  53.82 25.681 54.306 25.825 ;
     RECT  59.652 25.753 59.67 25.825 ;
     RECT  1.728 24.941 48.942 25.861 ;
     RECT  50.004 25.043 51.297 25.861 ;
     RECT  52.272 25.411 52.794 25.861 ;
     RECT  53.82 25.825 54.954 25.861 ;
     RECT  59.652 25.825 60.102 25.861 ;
     RECT  61.2 25.753 62.097 25.861 ;
     RECT  118.584 25.819 118.746 25.889 ;
     RECT  1.728 25.861 51.297 25.915 ;
     RECT  112.896 25.819 112.914 25.951 ;
     RECT  52.272 25.861 54.954 25.979 ;
     RECT  59.652 25.861 62.097 25.979 ;
     RECT  61.596 25.979 62.097 25.987 ;
     RECT  112.716 25.951 112.914 25.987 ;
     RECT  112.716 25.987 112.986 25.997 ;
     RECT  112.968 25.997 112.986 26.087 ;
     RECT  1.404 25.915 51.297 26.131 ;
     RECT  59.652 25.979 60.678 26.131 ;
     RECT  52.272 25.979 54.738 26.141 ;
     RECT  120.492 25.681 129.438 26.203 ;
     RECT  52.272 26.141 53.37 26.221 ;
     RECT  59.508 26.131 60.678 26.221 ;
     RECT  1.404 26.131 51.354 26.293 ;
     RECT  52.092 26.221 53.37 26.293 ;
     RECT  58.248 26.203 58.266 26.293 ;
     RECT  58.248 26.293 58.482 26.329 ;
     RECT  59.256 26.221 60.678 26.329 ;
     RECT  61.596 25.987 62.73 26.365 ;
     RECT  67.215 24.809 67.497 26.392 ;
     RECT  78.015 24.809 78.297 26.392 ;
     RECT  88.815 24.809 89.097 26.392 ;
     RECT  99.615 24.809 99.897 26.392 ;
     RECT  110.415 24.809 110.697 26.485 ;
     RECT  0.144 26.395 0.162 26.491 ;
     RECT  56.415 24.809 56.697 26.491 ;
     RECT  115.815 21.485 116.097 26.491 ;
     RECT  110.304 26.485 110.697 26.525 ;
     RECT  77.904 26.392 78.297 26.528 ;
     RECT  88.704 26.392 89.097 26.528 ;
     RECT  99.504 26.392 99.897 26.528 ;
     RECT  115.815 26.491 116.334 26.573 ;
     RECT  1.404 26.293 53.37 26.591 ;
     RECT  106.596 26.395 106.614 26.621 ;
     RECT  53.244 26.591 53.37 26.663 ;
     RECT  58.248 26.329 60.678 26.663 ;
     RECT  0.144 26.491 0.234 26.669 ;
     RECT  56.304 26.491 56.697 26.671 ;
     RECT  53.316 26.663 53.37 26.699 ;
     RECT  114.588 26.599 114.606 26.699 ;
     RECT  115.815 26.573 116.298 26.699 ;
     RECT  115.815 26.699 116.226 26.765 ;
     RECT  61.596 26.365 62.946 26.779 ;
     RECT  120.492 26.203 129.51 26.789 ;
     RECT  56.304 26.671 57.186 26.797 ;
     RECT  58.248 26.663 58.734 26.797 ;
     RECT  118.584 25.889 118.638 26.797 ;
     RECT  54.108 26.141 54.738 26.869 ;
     RECT  61.524 26.779 62.946 26.941 ;
     RECT  67.104 26.392 67.497 26.941 ;
     RECT  118.584 26.797 118.71 26.941 ;
     RECT  66.6 26.941 67.497 27.131 ;
     RECT  118.584 26.941 118.746 27.131 ;
     RECT  59.472 26.663 60.678 27.139 ;
     RECT  61.524 26.941 63.378 27.139 ;
     RECT  1.404 26.591 52.038 27.203 ;
     RECT  56.304 26.797 58.734 27.211 ;
     RECT  59.472 27.139 63.378 27.239 ;
     RECT  53.388 26.869 54.738 27.245 ;
     RECT  0.144 26.669 0.198 27.292 ;
     RECT  55.656 27.211 58.734 27.301 ;
     RECT  110.376 26.525 110.697 27.341 ;
     RECT  53.856 27.245 54.738 27.451 ;
     RECT  55.512 27.301 58.734 27.451 ;
     RECT  53.856 27.451 58.734 27.481 ;
     RECT  59.472 27.239 63.198 27.481 ;
     RECT  30.672 27.203 52.038 27.485 ;
     RECT  0.108 27.292 0.198 27.581 ;
     RECT  1.404 27.203 29.79 27.599 ;
     RECT  30.744 27.485 52.038 27.679 ;
     RECT  27.792 27.599 29.79 27.779 ;
     RECT  53.856 27.481 63.198 27.869 ;
     RECT  56.088 27.869 63.198 27.917 ;
     RECT  53.856 27.869 55.206 27.941 ;
     RECT  120.852 26.789 129.51 27.949 ;
     RECT  118.584 27.131 118.71 28.021 ;
     RECT  56.415 27.917 63.198 28.049 ;
     RECT  0.144 27.581 0.198 28.123 ;
     RECT  56.415 28.049 63.162 28.139 ;
     RECT  111.708 26.587 111.726 28.139 ;
     RECT  67.215 27.131 67.497 28.147 ;
     RECT  61.632 28.139 63.162 28.157 ;
     RECT  118.584 28.021 118.818 28.211 ;
     RECT  111.78 28.147 111.798 28.247 ;
     RECT  0.144 28.123 0.234 28.253 ;
     RECT  53.064 27.841 53.082 28.255 ;
     RECT  28.224 27.779 29.79 28.291 ;
     RECT  30.744 27.679 52.11 28.291 ;
     RECT  1.404 27.599 27.054 28.319 ;
     RECT  66.672 28.147 67.497 28.319 ;
     RECT  28.224 28.291 52.11 28.397 ;
     RECT  52.956 28.255 53.082 28.409 ;
     RECT  118.584 28.211 118.782 28.409 ;
     RECT  33.624 28.397 52.11 28.411 ;
     RECT  61.632 28.157 63.126 28.445 ;
     RECT  33.624 28.411 52.254 28.451 ;
     RECT  53.856 27.941 54.738 28.453 ;
     RECT  33.624 28.451 51.93 28.481 ;
     RECT  118.62 28.409 118.71 28.481 ;
     RECT  28.224 28.397 32.526 28.589 ;
     RECT  56.415 28.139 60.57 28.651 ;
     RECT  120.456 27.949 129.51 28.679 ;
     RECT  118.62 28.481 118.638 28.715 ;
     RECT  53.1 28.453 54.738 28.789 ;
     RECT  55.8 28.651 60.57 28.789 ;
     RECT  0.144 28.253 0.198 28.795 ;
     RECT  1.764 28.319 27.054 28.795 ;
     RECT  53.1 28.789 60.57 28.823 ;
     RECT  61.815 28.445 63.126 28.823 ;
     RECT  53.1 28.823 53.694 28.829 ;
     RECT  28.332 28.589 32.382 28.859 ;
     RECT  61.815 28.823 62.874 28.859 ;
     RECT  120.456 28.679 128.826 28.859 ;
     RECT  54.468 28.823 60.57 28.949 ;
     RECT  62.856 28.859 62.874 28.949 ;
     RECT  73.62 28.561 73.638 28.949 ;
     RECT  1.764 28.795 27.414 28.985 ;
     RECT  58.392 28.949 60.57 29.021 ;
     RECT  59.616 29.021 60.57 29.027 ;
     RECT  18.468 28.985 27.414 29.029 ;
     RECT  54.468 28.949 55.386 29.057 ;
     RECT  56.268 28.949 57.51 29.057 ;
     RECT  120.456 28.859 122.238 29.065 ;
     RECT  56.415 29.057 57.51 29.069 ;
     RECT  0.108 28.795 0.198 29.213 ;
     RECT  123.12 28.859 128.826 29.213 ;
     RECT  1.764 28.985 17.658 29.219 ;
     RECT  57.492 29.069 57.51 29.219 ;
     RECT  60.192 29.027 60.57 29.219 ;
     RECT  58.716 29.021 58.734 29.327 ;
     RECT  1.764 29.219 15.066 29.363 ;
     RECT  15.84 29.219 16.146 29.363 ;
     RECT  16.92 29.219 17.658 29.363 ;
     RECT  60.408 29.219 60.57 29.363 ;
     RECT  52.128 29.299 52.146 29.371 ;
     RECT  17.064 29.363 17.658 29.489 ;
     RECT  0.144 29.213 0.198 29.501 ;
     RECT  28.404 28.859 32.382 29.525 ;
     RECT  18.468 29.029 27.486 29.549 ;
     RECT  11.376 29.363 15.066 29.561 ;
     RECT  60.876 29.371 60.894 29.597 ;
     RECT  52.092 29.371 52.146 29.605 ;
     RECT  52.02 29.605 52.146 29.611 ;
     RECT  52.02 29.611 52.578 29.641 ;
     RECT  53.676 28.829 53.694 29.641 ;
     RECT  120.312 29.065 122.238 29.641 ;
     RECT  123.12 29.213 127.206 29.641 ;
     RECT  120.312 29.641 127.206 29.645 ;
     RECT  128.232 29.213 128.826 29.755 ;
     RECT  18.54 29.549 27.486 29.759 ;
     RECT  33.624 28.481 51.297 29.759 ;
     RECT  55.152 29.057 55.314 29.759 ;
     RECT  11.376 29.561 14.742 29.795 ;
     RECT  120.852 29.645 127.206 29.795 ;
     RECT  33.624 29.759 40.497 29.803 ;
     RECT  28.476 29.525 32.382 29.831 ;
     RECT  52.02 29.641 54.162 29.831 ;
     RECT  28.548 29.831 32.382 29.867 ;
     RECT  53.136 29.831 54.162 29.875 ;
     RECT  14.724 29.795 14.742 29.903 ;
     RECT  17.172 29.489 17.19 29.939 ;
     RECT  56.415 29.069 56.697 30.001 ;
     RECT  1.764 29.363 10.638 30.029 ;
     RECT  28.62 29.867 32.382 30.029 ;
     RECT  53.136 29.875 54.81 30.029 ;
     RECT  120.852 29.795 121.497 30.029 ;
     RECT  122.22 29.795 127.206 30.029 ;
     RECT  18.615 29.759 27.486 30.037 ;
     RECT  53.856 30.029 54.81 30.065 ;
     RECT  0.108 29.947 0.126 30.077 ;
     RECT  2.304 30.029 10.638 30.101 ;
     RECT  28.692 30.029 32.382 30.101 ;
     RECT  2.304 30.101 8.946 30.137 ;
     RECT  53.928 30.065 54.81 30.137 ;
     RECT  28.944 30.101 32.382 30.145 ;
     RECT  9.792 30.101 10.638 30.181 ;
     RECT  11.376 29.795 13.77 30.181 ;
     RECT  33.588 29.803 40.497 30.181 ;
     RECT  41.256 29.759 51.297 30.209 ;
     RECT  41.256 30.209 50.166 30.221 ;
     RECT  49.86 30.221 50.166 30.299 ;
     RECT  9.792 30.181 13.77 30.335 ;
     RECT  122.22 30.029 127.098 30.335 ;
     RECT  2.34 30.137 8.946 30.365 ;
     RECT  28.944 30.145 32.598 30.379 ;
     RECT  33.336 30.181 40.497 30.379 ;
     RECT  2.34 30.365 8.766 30.407 ;
     RECT  128.232 29.755 129.51 30.479 ;
     RECT  122.436 30.335 127.026 30.605 ;
     RECT  41.256 30.221 49.05 30.641 ;
     RECT  28.944 30.379 40.497 30.649 ;
     RECT  41.256 30.641 49.014 30.649 ;
     RECT  2.34 30.407 5.13 30.713 ;
     RECT  122.436 30.605 126.99 30.797 ;
     RECT  6.012 30.407 8.766 30.839 ;
     RECT  55.584 30.235 55.602 30.839 ;
     RECT  122.508 30.797 126.99 30.839 ;
     RECT  54.144 30.137 54.738 30.859 ;
     RECT  6.84 30.839 8.766 30.875 ;
     RECT  122.544 30.839 126.99 30.893 ;
     RECT  2.34 30.713 3.546 30.911 ;
     RECT  122.544 30.893 122.706 30.911 ;
     RECT  53.604 30.859 54.738 30.983 ;
     RECT  9.9 30.335 13.77 30.991 ;
     RECT  28.944 30.649 49.014 30.991 ;
     RECT  56.34 30.001 56.697 30.991 ;
     RECT  2.34 30.911 2.697 31.003 ;
     RECT  6.012 30.839 6.03 31.019 ;
     RECT  7.815 30.875 8.766 31.019 ;
     RECT  4.356 30.713 5.13 31.109 ;
     RECT  9.9 30.991 13.914 31.109 ;
     RECT  56.124 30.991 56.697 31.109 ;
     RECT  123.552 30.893 126.99 31.109 ;
     RECT  128.232 30.479 128.826 31.109 ;
     RECT  2.304 31.003 2.697 31.145 ;
     RECT  4.356 31.109 4.374 31.145 ;
     RECT  7.815 31.019 8.73 31.145 ;
     RECT  54.864 30.991 54.882 31.145 ;
     RECT  57.492 30.721 57.51 31.145 ;
     RECT  28.836 30.991 49.014 31.153 ;
     RECT  9.9 31.109 12.078 31.181 ;
     RECT  13.215 31.109 13.914 31.289 ;
     RECT  14.832 30.991 14.85 31.289 ;
     RECT  53.748 30.983 53.766 31.289 ;
     RECT  122.544 30.911 122.562 31.289 ;
     RECT  6.84 30.875 7.002 31.379 ;
     RECT  9.9 31.181 10.458 31.379 ;
     RECT  123.696 31.109 126.99 31.379 ;
     RECT  2.34 31.145 2.697 31.415 ;
     RECT  5.148 31.261 5.166 31.415 ;
     RECT  9.9 31.379 10.422 31.415 ;
     RECT  11.484 31.181 12.078 31.415 ;
     RECT  123.696 31.379 125.658 31.415 ;
     RECT  10.404 31.415 10.422 31.487 ;
     RECT  126.504 31.379 126.99 31.531 ;
     RECT  6.984 31.379 7.002 31.649 ;
     RECT  11.628 31.415 12.078 31.649 ;
     RECT  124.488 31.415 125.658 31.649 ;
     RECT  128.772 31.109 128.826 31.649 ;
     RECT  3.564 31.531 3.582 31.685 ;
     RECT  11.628 31.649 11.646 31.685 ;
     RECT  124.488 31.649 124.578 31.685 ;
     RECT  28.548 31.153 49.014 31.801 ;
     RECT  124.56 31.685 124.578 31.919 ;
     RECT  125.568 31.649 125.658 31.919 ;
     RECT  126.504 31.531 127.098 31.919 ;
     RECT  128.808 31.649 128.826 31.919 ;
     RECT  28.512 31.801 49.014 31.955 ;
     RECT  126.615 31.919 127.098 31.955 ;
     RECT  125.568 31.919 125.586 31.991 ;
     RECT  28.512 31.955 31.158 32.027 ;
     RECT  18.615 30.037 27.738 32.197 ;
     RECT  28.512 32.027 31.014 32.197 ;
     RECT  32.508 31.955 49.014 32.225 ;
     RECT  32.652 32.225 49.014 32.341 ;
     RECT  32.652 32.341 49.23 32.611 ;
     RECT  32.652 32.611 49.374 32.909 ;
     RECT  18.615 32.197 31.014 33.079 ;
     RECT  18.615 33.079 31.374 33.115 ;
     RECT  18.615 33.115 31.662 33.151 ;
     RECT  32.652 32.909 38.466 33.151 ;
     RECT  39.24 32.909 49.374 33.151 ;
     RECT  39.24 33.151 49.518 33.305 ;
     RECT  18.615 33.151 38.466 33.575 ;
     RECT  39.24 33.305 49.266 33.611 ;
     RECT  30.852 33.575 38.466 33.691 ;
     RECT  39.24 33.611 46.026 33.691 ;
     RECT  30.852 33.691 46.026 34.079 ;
     RECT  30.852 34.079 32.31 34.349 ;
     RECT  18.615 33.575 29.754 34.357 ;
     RECT  18.615 34.357 29.79 34.501 ;
     RECT  51.015 30.209 51.297 34.501 ;
     RECT  46.8 33.611 49.266 34.507 ;
     RECT  33.084 34.079 46.026 34.619 ;
     RECT  46.8 34.507 49.662 34.655 ;
     RECT  46.8 34.655 49.302 34.735 ;
     RECT  50.76 34.501 51.297 34.771 ;
     RECT  33.084 34.619 38.502 34.781 ;
     RECT  18.615 34.501 30.114 34.889 ;
     RECT  39.348 34.619 46.026 34.897 ;
     RECT  46.764 34.735 49.302 34.897 ;
     RECT  50.616 34.771 51.297 34.925 ;
     RECT  39.348 34.897 49.302 35.033 ;
     RECT  30.852 34.349 32.166 35.323 ;
     RECT  30.528 35.323 32.166 35.401 ;
     RECT  39.348 35.033 41.958 35.401 ;
     RECT  33.084 34.781 38.466 35.437 ;
     RECT  30.528 35.401 32.202 35.473 ;
     RECT  33.012 35.437 38.466 35.473 ;
     RECT  30.528 35.473 38.466 35.545 ;
     RECT  39.312 35.401 41.958 35.545 ;
     RECT  42.768 35.033 49.302 35.581 ;
     RECT  42.768 35.581 49.77 35.609 ;
     RECT  44.532 35.609 49.77 35.699 ;
     RECT  44.676 35.699 49.77 35.735 ;
     RECT  42.768 35.609 43.686 35.779 ;
     RECT  18.615 34.889 29.697 35.815 ;
     RECT  30.528 35.545 41.958 35.815 ;
     RECT  42.696 35.779 43.686 35.815 ;
     RECT  49.752 35.735 49.77 35.879 ;
     RECT  44.676 35.735 48.942 36.005 ;
     RECT  46.98 36.005 48.942 36.077 ;
     RECT  18.615 35.815 43.686 36.239 ;
     RECT  39.816 36.239 41.85 36.275 ;
     RECT  47.052 36.077 48.942 36.275 ;
     RECT  39.816 36.275 41.346 36.311 ;
     RECT  47.628 36.275 48.942 36.311 ;
     RECT  40.032 36.311 41.346 36.347 ;
     RECT  44.676 36.005 46.242 36.347 ;
     RECT  18.615 36.239 38.934 36.383 ;
     RECT  47.988 36.311 48.942 36.383 ;
     RECT  18.615 36.383 38.826 36.419 ;
     RECT  40.068 36.347 41.346 36.419 ;
     RECT  42.912 36.239 43.686 36.475 ;
     RECT  44.676 36.347 45.897 36.475 ;
     RECT  33.696 36.419 38.826 36.509 ;
     RECT  42.912 36.475 45.897 36.509 ;
     RECT  47.988 36.383 48.15 36.509 ;
     RECT  48.924 36.383 48.942 36.509 ;
     RECT  43.164 36.509 44.262 36.545 ;
     RECT  47.988 36.509 48.006 36.545 ;
     RECT  33.696 36.509 37.35 36.557 ;
     RECT  33.84 36.557 37.35 36.581 ;
     RECT  38.772 36.509 38.79 36.617 ;
     RECT  43.164 36.545 43.686 36.689 ;
     RECT  34.815 36.581 35.946 36.779 ;
     RECT  43.164 36.689 43.362 36.779 ;
     RECT  43.164 36.779 43.182 36.815 ;
     RECT  40.068 36.419 40.497 36.851 ;
     RECT  34.815 36.779 35.91 36.941 ;
     RECT  37.224 36.581 37.35 36.941 ;
     RECT  35.892 36.941 35.91 37.229 ;
     RECT  37.332 36.941 37.35 38.471 ;
     RECT  40.215 36.851 40.497 44.311 ;
     RECT  39.924 44.311 40.497 44.455 ;
     RECT  34.815 36.941 35.097 44.731 ;
     RECT  39.6 44.455 40.497 44.957 ;
     RECT  34.815 44.731 35.622 45.005 ;
     RECT  66.384 50.155 66.402 50.347 ;
     RECT  66.06 50.347 66.402 50.549 ;
     RECT  18.615 36.419 32.778 75.929 ;
     RECT  18.615 75.929 30.942 76.469 ;
     RECT  18.615 76.469 30.87 77.729 ;
     RECT  30.78 77.729 30.87 78.269 ;
     RECT  30.852 78.269 30.87 79.387 ;
     RECT  31.68 75.929 32.778 79.387 ;
     RECT  18.615 77.729 30.006 79.709 ;
     RECT  30.852 79.387 32.778 79.709 ;
     RECT  19.62 79.709 30.006 79.819 ;
     RECT  30.852 79.709 31.95 79.819 ;
     RECT  32.76 79.709 32.778 79.979 ;
     RECT  19.62 79.819 31.95 80.249 ;
     RECT  19.62 80.249 30.186 80.381 ;
     RECT  33.84 36.581 33.858 80.519 ;
     RECT  18.615 79.709 18.897 80.527 ;
     RECT  19.62 80.381 30.15 80.527 ;
     RECT  30.924 80.249 31.95 80.671 ;
     RECT  30.924 80.671 32.13 80.789 ;
     RECT  30.924 80.789 31.806 80.933 ;
     RECT  18.615 80.527 30.15 81.059 ;
     RECT  31.104 80.933 31.806 81.869 ;
     RECT  31.104 81.869 31.698 81.985 ;
     RECT  19.728 81.059 30.15 82.291 ;
     RECT  31.032 81.985 31.698 82.525 ;
     RECT  19.728 82.291 30.258 82.561 ;
     RECT  30.996 82.525 31.698 82.561 ;
     RECT  19.728 82.561 31.698 82.651 ;
     RECT  18.615 81.059 18.897 82.921 ;
     RECT  18.36 82.921 18.897 83.101 ;
     RECT  19.62 82.651 31.698 83.101 ;
     RECT  18.36 83.101 31.698 83.489 ;
     RECT  18.36 83.489 31.41 83.561 ;
     RECT  18.576 83.561 31.41 83.759 ;
     RECT  18.576 83.759 31.194 83.939 ;
     RECT  2.415 31.415 2.697 83.987 ;
     RECT  7.815 31.145 8.097 83.987 ;
     RECT  13.215 31.289 13.497 83.987 ;
     RECT  34.815 45.005 35.097 83.987 ;
     RECT  40.215 44.957 40.497 83.987 ;
     RECT  45.615 36.509 45.897 83.987 ;
     RECT  51.015 34.925 51.297 83.987 ;
     RECT  56.415 31.109 56.697 83.987 ;
     RECT  61.815 28.859 62.097 83.987 ;
     RECT  67.215 28.319 67.497 83.987 ;
     RECT  72.615 22.739 72.897 83.987 ;
     RECT  78.015 26.528 78.297 83.987 ;
     RECT  83.415 2.413 83.697 83.987 ;
     RECT  88.815 26.528 89.097 83.987 ;
     RECT  94.215 2.413 94.497 83.987 ;
     RECT  99.615 26.528 99.897 83.987 ;
     RECT  105.015 20.309 105.297 83.987 ;
     RECT  110.415 27.341 110.697 83.987 ;
     RECT  115.815 26.765 116.097 83.987 ;
     RECT  121.215 30.029 121.497 83.987 ;
     RECT  126.615 31.955 126.897 83.987 ;
     RECT  18.576 83.939 22.842 84.029 ;
     RECT  23.58 83.939 31.194 84.029 ;
     RECT  18.576 84.029 20.718 84.173 ;
     RECT  21.456 84.029 22.23 84.209 ;
     RECT  24.015 84.029 30.186 84.209 ;
     RECT  21.816 84.209 22.23 84.221 ;
     RECT  25.452 84.209 30.186 84.221 ;
     RECT  30.96 84.029 30.978 84.221 ;
     RECT  2.415 83.987 2.505 84.257 ;
     RECT  7.815 83.987 7.905 84.257 ;
     RECT  13.215 83.987 13.305 84.257 ;
     RECT  24.015 84.209 24.498 84.257 ;
     RECT  34.815 83.987 34.905 84.257 ;
     RECT  40.215 83.987 40.305 84.257 ;
     RECT  45.615 83.987 45.705 84.257 ;
     RECT  51.015 83.987 51.105 84.257 ;
     RECT  56.415 83.987 56.505 84.257 ;
     RECT  61.815 83.987 61.905 84.257 ;
     RECT  67.215 83.987 67.305 84.257 ;
     RECT  72.615 83.987 72.705 84.257 ;
     RECT  78.015 83.987 78.105 84.257 ;
     RECT  83.415 83.987 83.505 84.257 ;
     RECT  88.815 83.987 88.905 84.257 ;
     RECT  94.215 83.987 94.305 84.257 ;
     RECT  99.615 83.987 99.705 84.257 ;
     RECT  105.015 83.987 105.105 84.257 ;
     RECT  110.415 83.987 110.505 84.257 ;
     RECT  115.815 83.987 115.905 84.257 ;
     RECT  121.215 83.987 121.305 84.257 ;
     RECT  126.615 83.987 126.705 84.257 ;
     RECT  26.892 84.221 30.186 84.269 ;
     RECT  18.576 84.173 20.538 84.299 ;
     RECT  26.028 84.221 26.046 84.317 ;
     RECT  26.892 84.269 27.09 84.365 ;
     RECT  28.404 84.269 30.114 84.365 ;
     RECT  18.576 84.299 18.594 84.371 ;
     RECT  19.584 84.299 20.538 84.413 ;
     RECT  24.444 84.257 24.498 84.413 ;
     RECT  28.44 84.365 29.754 84.413 ;
     RECT  26.928 84.365 27.09 84.461 ;
     RECT  28.44 84.413 29.286 84.461 ;
     RECT  24.48 84.413 24.498 84.509 ;
     RECT  19.584 84.413 19.962 84.941 ;
     RECT  27.072 84.461 27.09 84.941 ;
     RECT  19.62 84.941 19.962 84.989 ;
     RECT  21.816 84.221 21.834 84.989 ;
     RECT  19.62 84.989 19.89 85.517 ;
     RECT  19.62 85.517 19.638 86.285 ;
     RECT  28.44 84.461 28.998 86.285 ;
    LAYER M4 ;
     RECT  0.025 19.968 0.06 19.992 ;
     RECT  0.084 29.184 0.097 29.208 ;
     RECT  0.06 29.208 0.097 29.28 ;
     RECT  0.084 29.28 0.097 29.304 ;
     RECT  0.06 29.304 0.097 29.376 ;
     RECT  0.084 29.376 0.097 29.4 ;
     RECT  0.06 29.4 0.097 29.472 ;
     RECT  0.084 29.472 0.097 29.496 ;
     RECT  0.06 29.496 0.097 29.568 ;
     RECT  0.084 29.568 0.097 29.592 ;
     RECT  0.06 29.592 0.097 29.664 ;
     RECT  0.084 29.664 0.097 29.688 ;
     RECT  0.06 29.688 0.097 29.76 ;
     RECT  0.084 29.76 0.097 29.784 ;
     RECT  0.06 29.784 0.097 29.856 ;
     RECT  0.084 29.856 0.097 29.88 ;
     RECT  0.06 29.88 0.097 29.952 ;
     RECT  0.084 29.952 0.097 29.976 ;
     RECT  0.084 31.008 0.097 31.032 ;
     RECT  0.06 31.032 0.097 31.104 ;
     RECT  0.084 31.104 0.097 31.128 ;
     RECT  0.06 19.968 0.133 20.064 ;
     RECT  0.084 20.064 0.133 20.088 ;
     RECT  0.06 20.088 0.133 20.16 ;
     RECT  0.084 20.16 0.133 20.184 ;
     RECT  0.06 20.184 0.133 20.256 ;
     RECT  0.084 20.256 0.133 20.28 ;
     RECT  0.06 20.28 0.133 20.352 ;
     RECT  0.084 20.352 0.133 20.376 ;
     RECT  0.06 20.376 0.133 20.448 ;
     RECT  0.084 20.448 0.133 20.472 ;
     RECT  0.06 20.472 0.133 20.544 ;
     RECT  0.084 20.544 0.133 20.568 ;
     RECT  0.06 20.568 0.133 20.64 ;
     RECT  0.084 20.64 0.133 20.664 ;
     RECT  0.06 20.664 0.133 20.736 ;
     RECT  0.084 20.736 0.133 20.76 ;
     RECT  0.06 20.76 0.133 20.832 ;
     RECT  0.084 20.832 0.133 20.856 ;
     RECT  0.06 20.856 0.133 20.928 ;
     RECT  0.084 20.928 0.133 20.952 ;
     RECT  0.06 20.952 0.133 21.024 ;
     RECT  0.084 21.024 0.133 21.048 ;
     RECT  0.06 21.048 0.133 21.12 ;
     RECT  0.084 21.12 0.133 21.144 ;
     RECT  0.06 21.144 0.133 21.216 ;
     RECT  0.084 21.216 0.133 21.24 ;
     RECT  0.06 21.24 0.133 21.312 ;
     RECT  0.084 21.312 0.133 21.336 ;
     RECT  0.06 21.336 0.133 21.408 ;
     RECT  0.084 21.408 0.133 21.432 ;
     RECT  0.06 21.432 0.133 21.504 ;
     RECT  0.084 21.504 0.133 21.528 ;
     RECT  0.06 21.528 0.133 21.6 ;
     RECT  0.084 21.6 0.133 21.624 ;
     RECT  0.06 21.624 0.133 21.696 ;
     RECT  0.084 21.696 0.133 21.72 ;
     RECT  0.06 21.72 0.133 21.792 ;
     RECT  0.084 21.792 0.133 21.816 ;
     RECT  0.06 21.816 0.133 21.888 ;
     RECT  0.084 21.888 0.133 21.912 ;
     RECT  0.06 21.912 0.133 21.984 ;
     RECT  0.084 21.984 0.133 22.008 ;
     RECT  0.06 22.008 0.133 22.08 ;
     RECT  0.084 22.08 0.133 22.104 ;
     RECT  0.06 22.104 0.133 22.176 ;
     RECT  0.084 22.176 0.133 22.2 ;
     RECT  0.06 22.2 0.133 22.272 ;
     RECT  0.084 22.272 0.133 22.296 ;
     RECT  0.06 22.296 0.133 22.368 ;
     RECT  0.084 22.368 0.133 22.392 ;
     RECT  0.06 22.392 0.133 22.464 ;
     RECT  0.084 22.464 0.133 22.488 ;
     RECT  0.06 22.488 0.133 22.56 ;
     RECT  0.084 22.56 0.133 22.584 ;
     RECT  0.06 22.584 0.133 22.656 ;
     RECT  0.084 22.656 0.133 22.68 ;
     RECT  0.06 22.68 0.133 22.752 ;
     RECT  0.084 22.752 0.133 22.776 ;
     RECT  0.06 22.776 0.133 22.848 ;
     RECT  0.084 22.848 0.133 22.872 ;
     RECT  0.06 22.872 0.133 22.944 ;
     RECT  0.084 22.944 0.133 22.968 ;
     RECT  0.06 22.968 0.133 23.04 ;
     RECT  0.084 23.04 0.133 23.064 ;
     RECT  0.06 23.064 0.133 23.136 ;
     RECT  0.084 23.136 0.133 23.16 ;
     RECT  0.06 23.16 0.133 23.232 ;
     RECT  0.084 23.232 0.133 23.256 ;
     RECT  0.06 23.256 0.133 23.328 ;
     RECT  0.084 23.328 0.133 23.352 ;
     RECT  0.06 23.352 0.133 23.424 ;
     RECT  0.084 23.424 0.133 23.448 ;
     RECT  0.06 23.448 0.133 23.52 ;
     RECT  0.084 23.52 0.133 23.544 ;
     RECT  0.06 23.544 0.133 23.616 ;
     RECT  0.084 23.616 0.133 23.64 ;
     RECT  0.06 23.64 0.133 23.712 ;
     RECT  0.084 23.712 0.133 23.736 ;
     RECT  0.06 23.736 0.133 23.808 ;
     RECT  0.084 23.808 0.133 23.832 ;
     RECT  0.06 23.832 0.133 23.904 ;
     RECT  0.084 23.904 0.133 23.928 ;
     RECT  0.06 23.928 0.133 24 ;
     RECT  0.084 24 0.133 24.024 ;
     RECT  0.06 24.024 0.133 24.096 ;
     RECT  0.084 24.096 0.133 24.12 ;
     RECT  0.06 24.12 0.133 24.192 ;
     RECT  0.084 24.192 0.133 24.216 ;
     RECT  0.06 24.216 0.133 24.288 ;
     RECT  0.084 24.288 0.133 24.312 ;
     RECT  0.06 24.312 0.133 24.384 ;
     RECT  0.084 24.384 0.133 24.408 ;
     RECT  0.06 24.408 0.133 24.48 ;
     RECT  0.084 24.48 0.133 24.504 ;
     RECT  0.06 24.504 0.133 24.576 ;
     RECT  0.084 24.576 0.133 24.6 ;
     RECT  0.06 24.6 0.133 24.672 ;
     RECT  0.084 24.672 0.133 24.696 ;
     RECT  0.06 24.696 0.133 24.768 ;
     RECT  0.084 24.768 0.133 24.792 ;
     RECT  0.06 24.792 0.133 24.864 ;
     RECT  0.084 24.864 0.133 24.888 ;
     RECT  0.06 24.888 0.133 24.96 ;
     RECT  0.084 24.96 0.133 24.984 ;
     RECT  0.06 24.984 0.133 25.056 ;
     RECT  0.084 25.056 0.133 25.08 ;
     RECT  0.06 25.08 0.133 25.152 ;
     RECT  0.084 25.152 0.133 25.176 ;
     RECT  0.06 25.176 0.133 25.248 ;
     RECT  0.084 25.248 0.133 25.272 ;
     RECT  0.06 25.272 0.133 25.344 ;
     RECT  0.084 25.344 0.133 25.368 ;
     RECT  0.06 25.368 0.133 25.44 ;
     RECT  0.084 25.44 0.133 25.464 ;
     RECT  0.06 25.464 0.133 25.536 ;
     RECT  0.084 25.536 0.133 25.56 ;
     RECT  0.06 25.56 0.133 25.632 ;
     RECT  0.084 25.632 0.133 25.656 ;
     RECT  0.06 25.656 0.133 25.728 ;
     RECT  0.084 25.728 0.133 25.752 ;
     RECT  0.06 25.752 0.133 25.824 ;
     RECT  0.084 25.824 0.133 25.848 ;
     RECT  0.06 25.848 0.133 25.92 ;
     RECT  0.084 25.92 0.133 25.944 ;
     RECT  0.06 25.944 0.133 26.016 ;
     RECT  0.084 26.016 0.133 26.04 ;
     RECT  0.06 26.04 0.133 26.112 ;
     RECT  0.084 26.112 0.133 26.136 ;
     RECT  0.06 26.136 0.133 26.208 ;
     RECT  0.084 26.208 0.133 26.232 ;
     RECT  0.06 26.232 0.133 26.304 ;
     RECT  0.084 26.304 0.133 26.328 ;
     RECT  0.06 26.328 0.133 26.4 ;
     RECT  0.084 26.4 0.133 26.424 ;
     RECT  0.06 26.424 0.133 26.496 ;
     RECT  0.084 26.496 0.133 26.52 ;
     RECT  0.06 26.52 0.133 26.592 ;
     RECT  0.084 26.592 0.133 26.616 ;
     RECT  0.06 26.616 0.133 26.688 ;
     RECT  0.084 26.688 0.133 26.712 ;
     RECT  0.06 26.712 0.133 26.784 ;
     RECT  0.084 26.784 0.133 26.808 ;
     RECT  0.06 26.808 0.133 26.88 ;
     RECT  0.084 26.88 0.133 26.904 ;
     RECT  0.06 26.904 0.133 26.976 ;
     RECT  0.084 26.976 0.133 27 ;
     RECT  0.06 27 0.133 27.072 ;
     RECT  0.084 27.072 0.133 27.096 ;
     RECT  0.06 27.096 0.133 27.168 ;
     RECT  0.084 27.168 0.133 27.192 ;
     RECT  0.06 27.192 0.133 27.264 ;
     RECT  0.084 27.264 0.133 27.288 ;
     RECT  0.06 27.288 0.133 27.36 ;
     RECT  0.084 27.36 0.133 27.384 ;
     RECT  0.06 27.384 0.133 27.456 ;
     RECT  0.084 27.456 0.133 27.48 ;
     RECT  0.06 27.48 0.133 27.552 ;
     RECT  0.084 27.552 0.133 27.576 ;
     RECT  0.06 27.576 0.133 27.648 ;
     RECT  0.084 27.648 0.133 27.672 ;
     RECT  0.06 27.672 0.133 27.744 ;
     RECT  0.084 27.744 0.133 27.768 ;
     RECT  0.06 27.768 0.133 27.84 ;
     RECT  0.084 27.84 0.133 27.864 ;
     RECT  0.06 27.864 0.133 27.936 ;
     RECT  0.084 27.936 0.133 27.96 ;
     RECT  0.06 27.96 0.133 28.032 ;
     RECT  0.084 28.032 0.133 28.056 ;
     RECT  0.06 28.056 0.133 28.128 ;
     RECT  0.084 28.128 0.133 28.152 ;
     RECT  0.097 29.184 0.137 31.128 ;
     RECT  0.137 29.28 0.173 31.128 ;
     RECT  0.133 19.968 0.205 28.2 ;
     RECT  0.205 19.968 0.209 28.248 ;
     RECT  0.209 20.064 2.221 28.248 ;
     RECT  0.173 29.376 2.221 31.128 ;
     RECT  2.221 20.064 2.408 31.128 ;
     RECT  2.408 2.148 2.512 84.252 ;
     RECT  2.512 2.418 2.704 83.982 ;
     RECT  2.704 20.064 2.729 28.488 ;
     RECT  2.704 29.76 3.017 30.072 ;
     RECT  2.729 20.064 3.053 28.248 ;
     RECT  3.017 29.76 3.341 29.784 ;
     RECT  3.053 20.064 3.377 28.2 ;
     RECT  3.377 20.064 4.025 28.008 ;
     RECT  4.025 20.64 4.061 20.664 ;
     RECT  4.025 21.984 4.097 28.008 ;
     RECT  4.097 22.032 4.169 28.008 ;
     RECT  4.169 22.032 4.277 25.176 ;
     RECT  4.277 22.032 4.457 25.08 ;
     RECT  4.169 26.256 4.565 28.008 ;
     RECT  4.565 26.304 4.813 28.008 ;
     RECT  4.813 26.304 4.997 28.872 ;
     RECT  4.457 22.368 5.357 25.08 ;
     RECT  5.357 22.368 5.465 23.256 ;
     RECT  4.997 28.848 5.465 28.872 ;
     RECT  4.997 26.304 5.537 27.864 ;
     RECT  5.357 24.432 5.605 25.08 ;
     RECT  5.537 26.304 5.605 27.672 ;
     RECT  5.641 20.832 5.749 20.856 ;
     RECT  5.465 22.368 5.785 23.016 ;
     RECT  5.785 21.936 5.893 23.016 ;
     RECT  5.749 20.112 6.361 20.856 ;
     RECT  5.893 21.888 6.361 23.016 ;
     RECT  6.361 20.112 6.649 23.016 ;
     RECT  5.605 24.432 6.829 27.672 ;
     RECT  6.181 29.664 6.865 29.688 ;
     RECT  6.865 29.232 7.189 29.688 ;
     RECT  7.189 29.232 7.196 30.36 ;
     RECT  6.649 20.112 7.333 23.352 ;
     RECT  6.829 24.336 7.333 27.672 ;
     RECT  7.333 20.112 7.369 27.672 ;
     RECT  7.196 29.232 7.369 30.552 ;
     RECT  4.981 6.288 7.808 6.312 ;
     RECT  7.369 20.112 7.808 30.552 ;
     RECT  4.021 50.352 7.808 50.376 ;
     RECT  7.808 2.148 7.912 84.252 ;
     RECT  7.912 2.418 8.104 83.982 ;
     RECT  8.104 19.92 8.915 30.36 ;
     RECT  8.915 20.16 8.957 30.36 ;
     RECT  8.957 20.16 10.285 30.216 ;
     RECT  10.285 20.16 10.325 31.176 ;
     RECT  10.325 30.816 11.009 31.176 ;
     RECT  10.325 20.16 11.509 29.256 ;
     RECT  11.509 20.064 11.653 29.256 ;
     RECT  11.653 20.064 12.168 29.592 ;
     RECT  12.168 20.064 13.208 29.784 ;
     RECT  11.009 30.816 13.208 30.84 ;
     RECT  8.104 50.352 13.208 50.376 ;
     RECT  13.208 2.148 13.312 84.252 ;
     RECT  13.312 2.418 13.504 83.982 ;
     RECT  13.504 20.064 14.285 29.592 ;
     RECT  14.285 20.064 14.645 29.256 ;
     RECT  14.645 20.16 15.473 29.256 ;
     RECT  15.473 20.304 15.545 29.256 ;
     RECT  15.545 22.176 16.076 29.256 ;
     RECT  16.076 22.176 16.163 29.352 ;
     RECT  15.545 20.304 16.729 21.048 ;
     RECT  16.163 22.176 16.729 29.256 ;
     RECT  16.729 20.304 17.053 29.256 ;
     RECT  17.053 20.16 17.489 29.256 ;
     RECT  17.489 20.304 18.457 29.256 ;
     RECT  18.457 20.304 18.608 29.544 ;
     RECT  13.504 50.352 18.608 50.376 ;
     RECT  18.608 2.148 18.712 84.252 ;
     RECT  18.712 2.418 18.904 84.252 ;
     RECT  18.904 20.592 18.965 31.128 ;
     RECT  18.965 20.592 19.613 30.84 ;
     RECT  19.613 21.216 19.721 30.84 ;
     RECT  19.573 84.912 19.861 84.936 ;
     RECT  19.609 86.256 19.861 86.28 ;
     RECT  18.904 83.664 19.897 83.88 ;
     RECT  19.897 83.232 19.969 83.88 ;
     RECT  19.861 84.912 19.969 86.28 ;
     RECT  19.969 83.232 20.099 86.28 ;
     RECT  19.721 21.888 20.261 30.84 ;
     RECT  18.904 32.448 20.261 32.472 ;
     RECT  20.099 83.232 20.387 85.512 ;
     RECT  18.904 78.624 20.401 78.648 ;
     RECT  20.387 83.232 20.905 84.984 ;
     RECT  20.261 21.888 20.981 30.312 ;
     RECT  20.401 78.048 21.061 78.648 ;
     RECT  20.981 21.936 21.089 30.312 ;
     RECT  21.061 77.52 21.253 78.648 ;
     RECT  20.905 82.608 21.373 84.984 ;
     RECT  21.089 22.08 21.485 30.312 ;
     RECT  21.253 77.52 21.589 79.224 ;
     RECT  21.373 82.464 21.589 84.984 ;
     RECT  20.329 31.296 21.841 31.32 ;
     RECT  21.485 22.224 21.881 30.312 ;
     RECT  21.589 82.08 21.923 84.984 ;
     RECT  21.589 76.704 22.021 79.224 ;
     RECT  21.697 80.352 22.021 80.376 ;
     RECT  21.829 86.208 22.115 86.232 ;
     RECT  21.923 82.08 22.252 84.216 ;
     RECT  22.021 76.704 22.421 80.376 ;
     RECT  22.252 82.08 22.453 83.352 ;
     RECT  22.421 76.704 22.493 79.32 ;
     RECT  22.493 76.704 22.529 78.024 ;
     RECT  22.421 80.352 22.633 80.376 ;
     RECT  22.453 81.936 22.633 83.352 ;
     RECT  21.881 22.464 22.705 30.312 ;
     RECT  21.841 31.296 22.705 31.896 ;
     RECT  22.705 22.464 22.745 31.896 ;
     RECT  22.813 20.496 22.849 20.52 ;
     RECT  22.493 79.296 22.853 79.32 ;
     RECT  22.633 80.352 22.925 83.352 ;
     RECT  22.745 30.576 22.957 31.896 ;
     RECT  22.093 34.176 22.997 34.2 ;
     RECT  22.849 20.496 23.029 21.432 ;
     RECT  22.745 22.464 23.029 29.256 ;
     RECT  22.957 30.576 23.425 32.52 ;
     RECT  23.425 30.576 23.605 33.096 ;
     RECT  22.529 76.704 23.605 77.784 ;
     RECT  23.605 76.56 23.677 77.784 ;
     RECT  22.925 80.352 23.785 82.776 ;
     RECT  23.413 83.808 23.989 83.832 ;
     RECT  23.029 20.496 24.008 29.256 ;
     RECT  23.605 30.576 24.008 33.576 ;
     RECT  23.857 39.312 24.008 39.336 ;
     RECT  18.904 50.352 24.008 50.376 ;
     RECT  23.677 76.56 24.008 77.976 ;
     RECT  23.785 79.776 24.008 82.776 ;
     RECT  23.989 83.808 24.008 84.408 ;
     RECT  24.008 2.148 24.085 84.408 ;
     RECT  24.085 2.148 24.112 84.504 ;
     RECT  23.557 86.208 24.181 86.232 ;
     RECT  24.112 2.418 24.304 84.504 ;
     RECT  24.304 30.624 24.365 33.144 ;
     RECT  24.304 35.76 24.419 36.936 ;
     RECT  24.181 86.16 24.467 86.232 ;
     RECT  24.304 80.832 24.509 84.504 ;
     RECT  24.365 30.624 24.581 33.096 ;
     RECT  24.509 80.832 24.659 84.36 ;
     RECT  24.304 20.592 24.869 29.64 ;
     RECT  24.304 75.168 24.869 78.744 ;
     RECT  24.304 38.736 24.941 39.336 ;
     RECT  24.304 34.128 25.013 34.392 ;
     RECT  24.869 77.808 25.043 78.744 ;
     RECT  25.013 34.272 25.085 34.392 ;
     RECT  24.419 35.808 25.121 36.936 ;
     RECT  24.869 75.168 25.157 76.584 ;
     RECT  25.157 75.168 25.283 76.488 ;
     RECT  24.581 30.624 25.549 31.32 ;
     RECT  25.484 38.544 25.571 38.568 ;
     RECT  25.283 75.552 25.612 76.488 ;
     RECT  24.869 21.072 25.621 29.64 ;
     RECT  25.549 30.624 25.621 31.416 ;
     RECT  25.085 34.368 25.621 34.392 ;
     RECT  25.621 21.072 25.661 31.416 ;
     RECT  25.661 21.072 25.705 31.272 ;
     RECT  25.121 35.808 25.729 36.888 ;
     RECT  25.705 30.624 25.769 31.272 ;
     RECT  25.729 35.712 25.769 36.888 ;
     RECT  25.621 34.368 25.805 34.44 ;
     RECT  24.304 79.776 25.861 79.848 ;
     RECT  24.659 80.88 25.861 84.36 ;
     RECT  25.043 77.808 25.909 78.648 ;
     RECT  25.612 75.792 25.913 76.488 ;
     RECT  25.769 30.624 25.949 30.84 ;
     RECT  25.705 21.072 26.053 29.256 ;
     RECT  25.805 34.416 26.057 34.44 ;
     RECT  25.769 35.712 26.089 35.736 ;
     RECT  25.861 79.776 26.137 84.36 ;
     RECT  25.913 76.464 26.149 76.488 ;
     RECT  25.909 77.568 26.149 78.648 ;
     RECT  26.089 34.656 26.237 35.736 ;
     RECT  26.149 39.648 26.237 39.672 ;
     RECT  26.149 58.128 26.237 58.68 ;
     RECT  24.581 32.4 26.273 33.096 ;
     RECT  26.237 58.656 26.381 58.68 ;
     RECT  25.949 30.624 26.489 30.648 ;
     RECT  24.467 86.208 26.579 86.232 ;
     RECT  26.149 76.464 26.741 78.648 ;
     RECT  26.273 32.4 26.773 33.048 ;
     RECT  26.137 79.824 26.773 84.36 ;
     RECT  26.741 76.8 26.867 77.832 ;
     RECT  26.237 35.712 27.101 35.736 ;
     RECT  26.773 79.824 27.101 84.936 ;
     RECT  27.101 79.824 27.133 84.456 ;
     RECT  27.133 79.152 27.203 84.456 ;
     RECT  26.773 32.304 27.313 33.048 ;
     RECT  25.769 36.864 27.317 36.888 ;
     RECT  26.867 76.896 27.317 77.832 ;
     RECT  27.317 76.992 27.709 77.832 ;
     RECT  27.203 79.152 27.709 84.36 ;
     RECT  26.053 20.16 27.781 29.256 ;
     RECT  27.709 76.992 27.821 84.36 ;
     RECT  27.821 79.584 28.019 84.36 ;
     RECT  28.019 80.928 28.145 84.36 ;
     RECT  27.277 75.792 28.211 75.816 ;
     RECT  28.019 79.584 28.217 79.848 ;
     RECT  28.145 81.504 28.307 84.36 ;
     RECT  28.217 79.824 28.348 79.848 ;
     RECT  27.821 76.992 28.357 78.12 ;
     RECT  27.781 20.112 28.393 29.256 ;
     RECT  28.357 58.656 28.421 58.68 ;
     RECT  28.357 76.944 28.441 78.12 ;
     RECT  27.313 32.256 28.537 33.048 ;
     RECT  28.021 86.256 28.573 86.28 ;
     RECT  28.537 31.968 28.789 33.048 ;
     RECT  28.393 20.112 29.113 29.304 ;
     RECT  28.573 85.488 29.219 86.28 ;
     RECT  28.307 82.032 29.257 84.36 ;
     RECT  29.113 20.112 29.269 29.352 ;
     RECT  29.219 85.488 29.315 85.512 ;
     RECT  29.269 19.776 29.408 29.352 ;
     RECT  28.789 31.776 29.408 33.048 ;
     RECT  28.453 39.648 29.408 39.672 ;
     RECT  25.525 44.352 29.408 44.376 ;
     RECT  24.304 50.352 29.408 50.376 ;
     RECT  28.421 58.128 29.408 58.68 ;
     RECT  28.441 77.28 29.408 78.12 ;
     RECT  29.257 82.032 29.408 84.456 ;
     RECT  29.408 2.148 29.507 84.456 ;
     RECT  29.507 2.148 29.512 84.408 ;
     RECT  29.512 2.418 29.704 84.408 ;
     RECT  29.704 83.232 29.765 84.408 ;
     RECT  29.704 76.368 29.891 76.392 ;
     RECT  29.765 83.232 30.125 84.36 ;
     RECT  30.125 83.232 30.197 84.264 ;
     RECT  30.197 83.232 30.701 84.216 ;
     RECT  29.704 34.368 30.769 34.392 ;
     RECT  29.704 35.424 30.769 36.168 ;
     RECT  29.704 77.808 30.769 78.264 ;
     RECT  29.704 19.248 30.845 33.144 ;
     RECT  29.704 79.824 30.901 80.376 ;
     RECT  30.901 79.824 30.988 80.52 ;
     RECT  30.701 83.808 31.043 84.216 ;
     RECT  31.043 83.808 31.139 83.832 ;
     RECT  30.988 79.824 31.196 79.944 ;
     RECT  30.845 19.248 31.277 32.472 ;
     RECT  30.769 77.664 31.283 78.264 ;
     RECT  31.196 79.392 31.283 79.944 ;
     RECT  31.283 79.392 31.493 79.416 ;
     RECT  30.769 34.368 31.781 36.168 ;
     RECT  31.277 19.248 31.925 30.6 ;
     RECT  31.781 34.368 31.961 35.448 ;
     RECT  31.925 30.48 32.033 30.6 ;
     RECT  32.033 30.528 32.317 30.6 ;
     RECT  31.277 31.776 32.317 32.472 ;
     RECT  31.961 34.368 33.061 34.392 ;
     RECT  31.961 35.424 33.061 35.448 ;
     RECT  31.925 19.248 33.308 29.256 ;
     RECT  32.317 30.528 33.308 32.472 ;
     RECT  33.061 34.368 33.349 35.976 ;
     RECT  33.308 19.248 33.388 32.472 ;
     RECT  33.349 34.368 33.395 36.936 ;
     RECT  33.395 35.28 33.437 36.936 ;
     RECT  33.388 31.632 34.009 32.472 ;
     RECT  34.009 31.632 34.045 32.568 ;
     RECT  34.045 31.632 34.261 32.808 ;
     RECT  33.388 19.248 34.693 30.6 ;
     RECT  34.261 31.632 34.693 33.096 ;
     RECT  34.693 19.248 34.729 33.096 ;
     RECT  34.693 34.128 34.729 34.152 ;
     RECT  34.729 19.248 34.808 34.152 ;
     RECT  33.437 35.28 34.808 35.304 ;
     RECT  33.437 36.528 34.808 36.936 ;
     RECT  29.704 44.352 34.808 44.376 ;
     RECT  29.704 50.352 34.808 50.376 ;
     RECT  31.283 77.664 34.808 77.688 ;
     RECT  34.808 2.148 34.912 84.252 ;
     RECT  34.912 2.418 35.104 83.982 ;
     RECT  35.104 31.968 35.219 36.936 ;
     RECT  35.219 31.968 35.363 33.432 ;
     RECT  35.104 19.248 35.453 30.888 ;
     RECT  35.363 31.968 35.525 33.384 ;
     RECT  35.104 77.664 35.603 77.688 ;
     RECT  35.104 44.352 35.633 45 ;
     RECT  35.219 34.8 36.028 36.936 ;
     RECT  35.525 32.256 36.421 33.384 ;
     RECT  36.028 34.8 36.421 34.824 ;
     RECT  36.421 32.256 36.533 34.824 ;
     RECT  36.533 34.032 36.997 34.824 ;
     RECT  36.028 36 36.997 36.936 ;
     RECT  36.533 32.256 37.093 32.904 ;
     RECT  36.997 34.032 37.139 36.936 ;
     RECT  37.093 31.824 37.177 32.904 ;
     RECT  37.139 36 37.253 36.936 ;
     RECT  37.139 34.032 37.289 34.824 ;
     RECT  35.453 19.248 37.357 30.216 ;
     RECT  37.177 31.248 37.357 32.904 ;
     RECT  37.357 19.248 37.541 32.904 ;
     RECT  37.289 34.128 37.715 34.824 ;
     RECT  37.541 30.672 38.477 32.904 ;
     RECT  37.253 36 38.761 36.024 ;
     RECT  37.715 34.128 39.301 34.776 ;
     RECT  38.761 35.952 39.301 36.024 ;
     RECT  39.301 34.128 39.337 36.024 ;
     RECT  35.633 44.352 39.589 44.76 ;
     RECT  37.541 19.248 39.637 29.64 ;
     RECT  38.477 30.672 39.637 32.472 ;
     RECT  39.637 19.248 39.841 32.472 ;
     RECT  39.337 33.936 39.841 36.024 ;
     RECT  39.841 19.248 40.208 36.024 ;
     RECT  39.589 44.352 40.208 44.952 ;
     RECT  35.104 50.352 40.208 50.376 ;
     RECT  40.208 2.148 40.312 84.252 ;
     RECT  40.312 2.418 40.504 83.982 ;
     RECT  40.504 30.672 40.601 35.256 ;
     RECT  40.504 19.248 41.605 29.64 ;
     RECT  40.601 30.672 41.605 33.048 ;
     RECT  41.605 19.248 42.397 33.048 ;
     RECT  40.601 34.08 42.397 35.256 ;
     RECT  41.821 36.24 42.901 36.264 ;
     RECT  42.397 19.248 43.009 35.256 ;
     RECT  42.901 36.24 43.009 36.504 ;
     RECT  43.009 19.248 43.157 36.504 ;
     RECT  43.157 31.104 43.373 36.504 ;
     RECT  43.373 34.08 43.733 36.504 ;
     RECT  43.733 34.08 44.093 35.496 ;
     RECT  44.093 34.08 44.137 35.256 ;
     RECT  43.733 36.48 44.273 36.504 ;
     RECT  43.373 31.104 44.413 32.856 ;
     RECT  44.413 31.104 44.627 33.288 ;
     RECT  43.157 19.248 45.097 30.072 ;
     RECT  44.627 31.104 45.097 31.992 ;
     RECT  44.137 34.416 45.241 35.256 ;
     RECT  44.627 33.264 45.421 33.288 ;
     RECT  45.097 19.248 45.608 31.992 ;
     RECT  45.421 33.264 45.608 33.384 ;
     RECT  45.241 34.416 45.608 35.832 ;
     RECT  40.504 44.928 45.608 44.952 ;
     RECT  40.504 50.352 45.608 50.376 ;
     RECT  45.608 2.148 45.712 84.252 ;
     RECT  45.712 2.418 45.904 83.982 ;
     RECT  45.904 19.248 46.001 35.832 ;
     RECT  46.001 19.248 46.787 34.536 ;
     RECT  46.001 35.568 46.793 35.832 ;
     RECT  46.787 34.224 46.835 34.536 ;
     RECT  46.787 19.248 46.973 33.144 ;
     RECT  46.973 31.2 47.153 33 ;
     RECT  46.793 35.568 47.977 35.592 ;
     RECT  46.835 34.224 48.188 34.488 ;
     RECT  47.977 35.568 48.188 36.504 ;
     RECT  47.153 31.2 48.229 32.76 ;
     RECT  48.188 34.224 48.229 36.504 ;
     RECT  48.229 31.2 48.467 36.504 ;
     RECT  48.467 31.2 48.485 35.592 ;
     RECT  48.485 31.824 48.665 35.592 ;
     RECT  48.665 31.968 48.851 35.304 ;
     RECT  48.851 32.448 48.917 35.304 ;
     RECT  48.917 32.448 48.947 32.472 ;
     RECT  48.917 33.552 48.988 35.304 ;
     RECT  48.988 34.512 49.061 35.304 ;
     RECT  49.061 34.512 49.673 34.536 ;
     RECT  46.973 19.248 49.745 30.216 ;
     RECT  49.745 19.248 51.008 29.592 ;
     RECT  45.904 44.928 51.008 44.952 ;
     RECT  45.904 50.352 51.008 50.376 ;
     RECT  51.008 2.148 51.112 84.252 ;
     RECT  51.112 2.418 51.304 83.982 ;
     RECT  51.304 19.248 51.833 29.64 ;
     RECT  51.833 24.72 52.589 29.64 ;
     RECT  53.593 30.864 54.601 30.888 ;
     RECT  54.601 30.768 54.709 30.888 ;
     RECT  54.709 30.672 54.713 30.888 ;
     RECT  54.713 30.672 54.755 30.792 ;
     RECT  54.755 30.672 54.793 30.696 ;
     RECT  52.589 24.72 55.285 29.352 ;
     RECT  51.833 19.248 56.408 23.688 ;
     RECT  55.285 24.72 56.408 30.264 ;
     RECT  51.304 44.928 56.408 44.952 ;
     RECT  51.304 50.352 56.408 50.376 ;
     RECT  56.408 2.148 56.512 84.252 ;
     RECT  56.512 2.418 56.704 83.982 ;
     RECT  56.704 19.248 61.808 23.688 ;
     RECT  56.704 24.72 61.808 29.352 ;
     RECT  56.704 44.928 61.808 44.952 ;
     RECT  56.704 50.352 61.808 50.376 ;
     RECT  61.808 2.148 61.912 84.252 ;
     RECT  61.912 2.418 62.104 83.982 ;
     RECT  62.104 24.72 63.101 29.352 ;
     RECT  63.101 24.72 63.173 28.152 ;
     RECT  62.104 50.352 66.089 50.376 ;
     RECT  62.104 44.928 66.133 44.952 ;
     RECT  66.133 44.784 66.179 44.952 ;
     RECT  62.104 19.248 67.208 23.688 ;
     RECT  63.173 24.72 67.208 27.336 ;
     RECT  63.101 29.28 67.208 29.352 ;
     RECT  66.179 44.784 67.208 44.808 ;
     RECT  66.373 50.16 67.208 50.184 ;
     RECT  67.208 2.148 67.312 84.252 ;
     RECT  67.312 2.418 67.504 83.982 ;
     RECT  67.504 19.248 72.608 23.688 ;
     RECT  67.504 24.72 72.608 27.336 ;
     RECT  67.504 29.28 72.608 29.352 ;
     RECT  72.608 2.148 72.712 84.252 ;
     RECT  72.712 2.418 72.904 83.982 ;
     RECT  72.904 19.248 78.008 23.688 ;
     RECT  72.904 24.72 78.008 27.336 ;
     RECT  72.904 29.28 78.008 29.352 ;
     RECT  78.008 2.148 78.112 84.252 ;
     RECT  78.112 2.418 78.304 83.982 ;
     RECT  78.304 19.248 83.408 23.688 ;
     RECT  78.304 24.72 83.408 27.336 ;
     RECT  78.304 29.28 83.408 29.352 ;
     RECT  83.408 2.148 83.512 84.252 ;
     RECT  83.512 2.418 83.704 83.982 ;
     RECT  83.704 19.248 88.808 23.688 ;
     RECT  83.704 24.72 88.808 27.336 ;
     RECT  83.704 29.28 88.808 29.352 ;
     RECT  88.808 2.148 88.912 84.252 ;
     RECT  88.912 2.418 89.104 83.982 ;
     RECT  89.104 19.248 94.208 23.688 ;
     RECT  89.104 24.72 94.208 27.336 ;
     RECT  89.104 29.28 94.208 29.352 ;
     RECT  94.208 2.148 94.312 84.252 ;
     RECT  94.312 2.418 94.504 83.982 ;
     RECT  94.504 19.248 99.608 23.688 ;
     RECT  94.504 24.72 99.608 27.336 ;
     RECT  94.504 29.28 99.608 29.352 ;
     RECT  99.608 2.148 99.712 84.252 ;
     RECT  99.712 2.418 99.904 83.982 ;
     RECT  99.904 19.248 105.008 23.688 ;
     RECT  99.904 24.72 105.008 27.336 ;
     RECT  99.904 29.28 105.008 29.352 ;
     RECT  105.008 2.148 105.112 84.252 ;
     RECT  105.112 2.418 105.304 83.982 ;
     RECT  105.304 19.248 108.353 23.688 ;
     RECT  108.353 19.296 110.408 23.688 ;
     RECT  105.304 24.72 110.408 27.336 ;
     RECT  105.304 29.28 110.408 29.352 ;
     RECT  110.408 2.148 110.512 84.252 ;
     RECT  110.512 2.418 110.704 83.982 ;
     RECT  110.704 19.296 115.808 23.688 ;
     RECT  110.704 24.72 115.808 26.664 ;
     RECT  110.704 29.28 115.808 29.352 ;
     RECT  115.808 2.148 115.912 84.252 ;
     RECT  115.912 2.418 116.104 83.982 ;
     RECT  116.104 24.72 116.281 26.76 ;
     RECT  116.104 29.088 120.301 29.352 ;
     RECT  116.104 19.296 120.553 23.688 ;
     RECT  116.281 24.72 120.553 26.664 ;
     RECT  120.553 19.296 121.208 26.664 ;
     RECT  120.301 29.088 121.208 29.64 ;
     RECT  121.208 2.148 121.312 84.252 ;
     RECT  121.312 2.418 121.504 83.982 ;
     RECT  121.504 19.296 122.033 29.64 ;
     RECT  121.504 30.768 122.533 30.792 ;
     RECT  122.533 30.768 122.573 30.888 ;
     RECT  122.573 30.864 123.329 30.888 ;
     RECT  122.033 19.296 124.657 29.304 ;
     RECT  124.657 19.296 124.733 29.736 ;
     RECT  124.733 20.304 125.057 29.736 ;
     RECT  125.057 20.304 125.093 23.736 ;
     RECT  125.057 24.72 125.165 29.736 ;
     RECT  125.165 24.72 125.201 29.112 ;
     RECT  125.201 24.864 125.345 29.112 ;
     RECT  124.733 19.296 125.381 19.32 ;
     RECT  125.093 20.592 125.489 23.736 ;
     RECT  125.345 25.44 125.489 29.112 ;
     RECT  125.489 22.704 126.421 23.736 ;
     RECT  125.489 20.592 126.608 21.72 ;
     RECT  126.421 22.704 126.608 24.456 ;
     RECT  125.489 25.44 126.608 28.488 ;
     RECT  126.608 2.148 126.712 84.252 ;
     RECT  126.712 2.418 126.904 83.982 ;
     RECT  126.904 21.696 127.969 27.72 ;
     RECT  127.969 21.696 128.149 27.96 ;
     RECT  126.904 20.16 128.185 20.568 ;
     RECT  128.149 21.6 128.185 27.96 ;
     RECT  128.185 20.16 128.221 27.96 ;
     RECT  126.904 29.184 128.221 29.592 ;
     RECT  128.221 20.16 128.797 28.056 ;
     RECT  128.761 31.104 128.797 31.128 ;
     RECT  128.797 20.064 129.481 28.056 ;
     RECT  129.481 20.064 129.516 20.088 ;
     RECT  129.481 20.088 129.564 20.16 ;
     RECT  129.481 20.16 129.516 20.184 ;
     RECT  129.481 20.184 129.564 20.256 ;
     RECT  129.481 20.256 129.516 20.28 ;
     RECT  129.481 20.28 129.564 20.352 ;
     RECT  129.481 20.352 129.516 20.376 ;
     RECT  129.481 20.376 129.564 20.448 ;
     RECT  129.481 20.448 129.516 20.472 ;
     RECT  129.481 20.472 129.564 20.544 ;
     RECT  129.481 20.544 129.516 20.568 ;
     RECT  129.481 20.568 129.564 20.64 ;
     RECT  129.481 20.64 129.516 20.664 ;
     RECT  129.481 20.664 129.564 20.736 ;
     RECT  129.481 20.736 129.516 20.76 ;
     RECT  129.481 20.76 129.564 20.832 ;
     RECT  129.481 20.832 129.516 20.856 ;
     RECT  129.481 20.856 129.564 20.928 ;
     RECT  129.481 20.928 129.516 20.952 ;
     RECT  129.481 20.952 129.564 21.024 ;
     RECT  129.481 21.024 129.516 21.048 ;
     RECT  129.481 21.048 129.564 21.12 ;
     RECT  129.481 21.12 129.516 21.144 ;
     RECT  129.481 21.144 129.564 21.216 ;
     RECT  129.481 21.216 129.516 21.24 ;
     RECT  129.481 21.24 129.564 21.312 ;
     RECT  129.481 21.312 129.516 21.336 ;
     RECT  129.481 21.336 129.564 21.408 ;
     RECT  129.481 21.408 129.516 21.432 ;
     RECT  129.481 21.432 129.564 21.504 ;
     RECT  129.481 21.504 129.516 21.528 ;
     RECT  129.481 21.528 129.564 21.6 ;
     RECT  129.481 21.6 129.516 21.624 ;
     RECT  129.481 21.624 129.564 21.696 ;
     RECT  129.481 21.696 129.516 21.72 ;
     RECT  129.481 21.72 129.564 21.792 ;
     RECT  129.481 21.792 129.516 21.816 ;
     RECT  129.481 21.816 129.564 21.888 ;
     RECT  129.481 21.888 129.516 21.912 ;
     RECT  129.481 21.912 129.564 21.984 ;
     RECT  129.481 21.984 129.516 22.008 ;
     RECT  129.481 22.008 129.564 22.08 ;
     RECT  129.481 22.08 129.516 22.104 ;
     RECT  129.481 22.104 129.564 22.176 ;
     RECT  129.481 22.176 129.516 22.2 ;
     RECT  129.481 22.2 129.564 22.272 ;
     RECT  129.481 22.272 129.516 22.296 ;
     RECT  129.481 22.296 129.564 22.368 ;
     RECT  129.481 22.368 129.516 22.392 ;
     RECT  129.481 22.392 129.564 22.464 ;
     RECT  129.481 22.464 129.516 22.488 ;
     RECT  129.481 22.488 129.564 22.56 ;
     RECT  129.481 22.56 129.516 22.584 ;
     RECT  129.481 22.584 129.564 22.656 ;
     RECT  129.481 22.656 129.516 22.68 ;
     RECT  129.481 22.68 129.564 22.752 ;
     RECT  129.481 22.752 129.516 22.776 ;
     RECT  129.481 22.776 129.564 22.848 ;
     RECT  129.481 22.848 129.516 22.872 ;
     RECT  129.481 22.872 129.564 22.944 ;
     RECT  129.481 22.944 129.516 22.968 ;
     RECT  129.481 22.968 129.564 23.04 ;
     RECT  129.481 23.04 129.516 23.064 ;
     RECT  129.481 23.064 129.564 23.136 ;
     RECT  129.481 23.136 129.516 23.16 ;
     RECT  129.481 23.16 129.564 23.232 ;
     RECT  129.481 23.232 129.516 23.256 ;
     RECT  129.481 23.256 129.564 23.328 ;
     RECT  129.481 23.328 129.516 23.352 ;
     RECT  129.481 23.352 129.564 23.424 ;
     RECT  129.481 23.424 129.516 23.448 ;
     RECT  129.481 23.448 129.564 23.52 ;
     RECT  129.481 23.52 129.516 23.544 ;
     RECT  129.481 23.544 129.564 23.616 ;
     RECT  129.481 23.616 129.516 23.64 ;
     RECT  129.481 23.64 129.564 23.712 ;
     RECT  129.481 23.712 129.516 23.736 ;
     RECT  129.481 23.736 129.564 23.808 ;
     RECT  129.481 23.808 129.516 23.832 ;
     RECT  129.481 23.832 129.564 23.904 ;
     RECT  129.481 23.904 129.516 23.928 ;
     RECT  129.481 23.928 129.564 24 ;
     RECT  129.481 24 129.516 24.024 ;
     RECT  129.481 24.024 129.564 24.096 ;
     RECT  129.481 24.096 129.516 24.12 ;
     RECT  129.481 24.12 129.564 24.192 ;
     RECT  129.481 24.192 129.516 24.216 ;
     RECT  129.481 24.216 129.564 24.288 ;
     RECT  129.481 24.288 129.516 24.312 ;
     RECT  129.481 24.312 129.564 24.384 ;
     RECT  129.481 24.384 129.516 24.408 ;
     RECT  129.481 24.408 129.564 24.48 ;
     RECT  129.481 24.48 129.516 24.504 ;
     RECT  129.481 24.504 129.564 24.576 ;
     RECT  129.481 24.576 129.516 24.6 ;
     RECT  129.481 24.6 129.564 24.672 ;
     RECT  129.481 24.672 129.516 24.696 ;
     RECT  129.481 24.696 129.564 24.768 ;
     RECT  129.481 24.768 129.516 24.792 ;
     RECT  129.481 24.792 129.564 24.864 ;
     RECT  129.481 24.864 129.516 24.888 ;
     RECT  129.481 24.888 129.564 24.96 ;
     RECT  129.481 24.96 129.516 24.984 ;
     RECT  129.481 24.984 129.564 25.056 ;
     RECT  129.481 25.056 129.516 25.08 ;
     RECT  129.481 25.08 129.564 25.152 ;
     RECT  129.481 25.152 129.516 25.176 ;
     RECT  129.481 25.176 129.564 25.248 ;
     RECT  129.481 25.248 129.516 25.272 ;
     RECT  129.481 25.272 129.564 25.344 ;
     RECT  129.481 25.344 129.516 25.368 ;
     RECT  129.481 25.368 129.564 25.44 ;
     RECT  129.481 25.44 129.516 25.464 ;
     RECT  129.481 25.464 129.564 25.536 ;
     RECT  129.481 25.536 129.516 25.56 ;
     RECT  129.481 25.56 129.564 25.632 ;
     RECT  129.481 25.632 129.516 25.656 ;
     RECT  129.481 25.656 129.564 25.728 ;
     RECT  129.481 25.728 129.516 25.752 ;
     RECT  129.481 25.752 129.564 25.824 ;
     RECT  129.481 25.824 129.516 25.848 ;
     RECT  129.481 25.848 129.564 25.92 ;
     RECT  129.481 25.92 129.516 25.944 ;
     RECT  129.481 25.944 129.564 26.016 ;
     RECT  129.481 26.016 129.516 26.04 ;
     RECT  129.481 26.04 129.564 26.112 ;
     RECT  129.481 26.112 129.516 26.136 ;
     RECT  129.481 26.136 129.564 26.208 ;
     RECT  129.481 26.208 129.516 26.232 ;
     RECT  129.481 26.232 129.564 26.304 ;
     RECT  129.481 26.304 129.516 26.328 ;
     RECT  129.481 26.328 129.564 26.4 ;
     RECT  129.481 26.4 129.516 26.424 ;
     RECT  129.481 26.424 129.564 26.496 ;
     RECT  129.481 26.496 129.516 26.52 ;
     RECT  129.481 26.52 129.564 26.592 ;
     RECT  129.481 26.592 129.516 26.616 ;
     RECT  129.481 26.616 129.564 26.688 ;
     RECT  129.481 26.688 129.516 26.712 ;
     RECT  129.481 26.712 129.564 26.784 ;
     RECT  129.481 26.784 129.516 26.808 ;
     RECT  129.481 26.808 129.564 26.88 ;
     RECT  129.481 26.88 129.516 26.904 ;
     RECT  129.481 26.904 129.564 26.976 ;
     RECT  129.481 26.976 129.516 27 ;
     RECT  129.481 27 129.564 27.072 ;
     RECT  129.481 27.072 129.516 27.096 ;
     RECT  129.481 27.096 129.564 27.168 ;
     RECT  129.481 27.168 129.516 27.192 ;
     RECT  129.481 27.192 129.564 27.264 ;
     RECT  129.481 27.264 129.516 27.288 ;
     RECT  129.481 27.288 129.564 27.36 ;
     RECT  129.481 27.36 129.516 27.384 ;
     RECT  129.481 27.384 129.564 27.456 ;
     RECT  129.481 27.456 129.516 27.48 ;
     RECT  129.481 27.48 129.564 27.552 ;
     RECT  129.481 27.552 129.516 27.576 ;
     RECT  129.481 27.576 129.564 27.648 ;
     RECT  129.481 27.648 129.516 27.672 ;
     RECT  129.481 27.672 129.564 27.744 ;
     RECT  129.481 27.744 129.516 27.768 ;
     RECT  129.481 27.768 129.564 27.84 ;
     RECT  129.481 27.84 129.516 27.864 ;
     RECT  129.481 27.864 129.564 27.936 ;
     RECT  129.481 27.936 129.516 27.96 ;
     RECT  129.481 27.96 129.564 28.032 ;
     RECT  129.481 28.032 129.516 28.056 ;
     RECT  129.481 28.056 129.564 28.128 ;
     RECT  129.481 28.128 129.516 28.152 ;
     RECT  128.221 29.184 129.516 29.208 ;
     RECT  128.221 29.208 129.564 29.28 ;
     RECT  128.221 29.28 129.516 29.304 ;
     RECT  128.221 29.304 129.564 29.376 ;
     RECT  128.221 29.376 129.516 29.4 ;
     RECT  128.221 29.4 129.564 29.472 ;
     RECT  128.221 29.472 129.516 29.496 ;
     RECT  128.221 29.496 129.564 29.568 ;
     RECT  128.221 29.568 129.516 29.592 ;
     RECT  128.221 29.592 129.564 29.664 ;
     RECT  128.221 29.664 129.516 29.688 ;
     RECT  128.221 29.688 129.564 29.76 ;
     RECT  128.221 29.76 129.516 29.784 ;
     RECT  128.221 29.784 129.564 29.856 ;
     RECT  128.221 29.856 129.516 29.88 ;
     RECT  128.221 29.88 129.564 29.952 ;
     RECT  128.221 29.952 129.516 29.976 ;
     RECT  128.797 31.008 129.516 31.032 ;
     RECT  128.797 31.032 129.564 31.104 ;
     RECT  128.797 31.104 129.516 31.128 ;
    LAYER M5 ;
     RECT  2.4 2.137 2.52 2.151 ;
     RECT  7.8 2.137 7.92 2.151 ;
     RECT  13.2 2.137 13.32 2.151 ;
     RECT  18.6 2.137 18.72 2.151 ;
     RECT  24 2.137 24.12 2.151 ;
     RECT  29.4 2.137 29.52 2.151 ;
     RECT  34.8 2.137 34.92 2.151 ;
     RECT  40.2 2.137 40.32 2.151 ;
     RECT  45.6 2.137 45.72 2.151 ;
     RECT  51 2.137 51.12 2.151 ;
     RECT  56.4 2.137 56.52 2.151 ;
     RECT  61.8 2.137 61.92 2.151 ;
     RECT  67.2 2.137 67.32 2.151 ;
     RECT  72.6 2.137 72.72 2.151 ;
     RECT  78 2.137 78.12 2.151 ;
     RECT  83.4 2.137 83.52 2.151 ;
     RECT  88.8 2.137 88.92 2.151 ;
     RECT  94.2 2.137 94.32 2.151 ;
     RECT  99.6 2.137 99.72 2.151 ;
     RECT  105 2.137 105.12 2.151 ;
     RECT  110.4 2.137 110.52 2.151 ;
     RECT  115.8 2.137 115.92 2.151 ;
     RECT  121.2 2.137 121.32 2.151 ;
     RECT  126.6 2.137 126.72 2.151 ;
     RECT  4.056 0.016 4.992 0.084 ;
     RECT  4.032 0.084 5.016 6.323 ;
     RECT  29.4 2.151 29.712 19.237 ;
     RECT  29.4 19.237 30.216 19.765 ;
     RECT  7.8 2.151 8.112 19.909 ;
     RECT  27.888 20.341 27.912 20.389 ;
     RECT  29.28 19.765 30.216 20.579 ;
     RECT  0.144 20.629 0.168 21.011 ;
     RECT  29.28 20.579 29.712 21.251 ;
     RECT  17.28 20.341 17.304 21.539 ;
     RECT  27.888 20.389 28.056 22.499 ;
     RECT  24 2.151 24.312 22.549 ;
     RECT  56.4 2.151 56.712 22.549 ;
     RECT  13.2 2.151 13.512 22.597 ;
     RECT  13.2 22.597 13.608 22.693 ;
     RECT  13.2 22.693 13.656 22.741 ;
     RECT  29.4 21.251 29.712 22.741 ;
     RECT  23.328 22.549 24.408 22.835 ;
     RECT  38.064 22.789 38.088 23.027 ;
     RECT  10.848 22.885 10.872 23.171 ;
     RECT  123.648 19.909 123.672 23.173 ;
     RECT  123.648 23.173 124.248 23.363 ;
     RECT  23.328 22.835 24.312 23.411 ;
     RECT  27.888 22.499 27.912 23.411 ;
     RECT  40.2 2.151 40.512 23.509 ;
     RECT  1.152 23.557 1.176 23.891 ;
     RECT  0.144 23.557 0.168 23.939 ;
     RECT  29.4 22.741 29.88 23.939 ;
     RECT  18.6 2.151 18.912 23.941 ;
     RECT  45.6 2.151 45.912 24.085 ;
     RECT  40.2 23.509 41.16 24.133 ;
     RECT  26.736 23.173 26.76 24.371 ;
     RECT  18.6 23.941 19.752 24.419 ;
     RECT  40.08 24.133 41.16 24.421 ;
     RECT  22.8 24.277 22.824 24.467 ;
     RECT  1.248 24.373 1.272 24.515 ;
     RECT  123.744 23.363 124.248 24.563 ;
     RECT  51 2.151 51.312 24.565 ;
     RECT  39.36 24.421 41.16 24.901 ;
     RECT  45.408 24.085 45.912 24.901 ;
     RECT  38.88 24.901 41.16 24.947 ;
     RECT  15.696 22.741 15.72 24.995 ;
     RECT  18.6 24.419 19.032 24.995 ;
     RECT  38.88 24.947 40.632 25.045 ;
     RECT  45.312 24.901 45.912 25.045 ;
     RECT  50.112 24.565 51.312 25.285 ;
     RECT  52.752 22.453 52.776 25.285 ;
     RECT  21.984 25.189 22.008 25.427 ;
     RECT  50.112 25.285 52.776 25.427 ;
     RECT  45.024 25.045 45.912 25.429 ;
     RECT  38.448 25.045 40.632 25.475 ;
     RECT  50.112 25.427 51.912 25.619 ;
     RECT  30.912 23.317 30.936 25.715 ;
     RECT  33.648 24.469 33.672 25.715 ;
     RECT  13.2 22.741 14.376 25.957 ;
     RECT  24 23.411 24.312 25.957 ;
     RECT  48.72 25.285 48.744 25.957 ;
     RECT  50.112 25.619 51.312 25.957 ;
     RECT  48.72 25.957 51.312 26.003 ;
     RECT  22.704 25.909 22.728 26.099 ;
     RECT  23.904 25.957 25.128 26.099 ;
     RECT  41.712 25.813 41.736 26.099 ;
     RECT  54.288 25.573 54.312 26.101 ;
     RECT  18.6 24.995 18.912 26.149 ;
     RECT  44.976 25.429 45.912 26.149 ;
     RECT  7.8 19.909 8.904 26.195 ;
     RECT  36.432 25.621 36.456 26.243 ;
     RECT  38.448 25.475 38.472 26.243 ;
     RECT  40.032 25.475 40.632 26.245 ;
     RECT  40.032 26.245 40.776 26.435 ;
     RECT  10.848 26.293 10.872 26.483 ;
     RECT  48.72 26.003 49.944 26.483 ;
     RECT  2.4 2.151 2.712 26.581 ;
     RECT  17.136 26.485 17.16 26.627 ;
     RECT  53.568 26.101 54.312 26.627 ;
     RECT  13.2 25.957 14.664 26.675 ;
     RECT  49.92 26.483 49.944 26.723 ;
     RECT  115.8 2.151 116.112 26.725 ;
     RECT  18.6 26.149 19.608 26.819 ;
     RECT  40.032 26.435 40.632 26.819 ;
     RECT  48.72 26.483 48.744 26.819 ;
     RECT  60.432 26.197 60.456 26.819 ;
     RECT  44.976 26.149 46.008 26.965 ;
     RECT  22.656 27.013 22.68 27.061 ;
     RECT  24 26.099 25.128 27.061 ;
     RECT  2.304 26.581 2.712 27.109 ;
     RECT  18.6 26.819 19.032 27.157 ;
     RECT  2.304 27.109 2.808 27.251 ;
     RECT  22.656 27.061 25.128 27.251 ;
     RECT  44.976 26.965 46.104 27.251 ;
     RECT  53.568 26.627 53.832 27.251 ;
     RECT  22.752 27.251 25.128 27.299 ;
     RECT  56.4 22.549 57.528 27.301 ;
     RECT  2.4 27.251 2.808 27.347 ;
     RECT  17.664 27.157 19.032 27.395 ;
     RECT  14.64 26.675 14.664 27.443 ;
     RECT  28.08 26.581 28.104 27.491 ;
     RECT  38.784 27.493 38.808 27.731 ;
     RECT  48.816 27.541 48.936 27.779 ;
     RECT  123.744 24.563 123.768 27.781 ;
     RECT  48.912 27.779 48.936 27.827 ;
     RECT  40.08 26.819 40.632 27.829 ;
     RECT  13.2 26.675 13.512 27.877 ;
     RECT  123.744 27.781 124.248 27.971 ;
     RECT  43.296 25.045 43.32 28.019 ;
     RECT  17.664 27.395 18.912 28.211 ;
     RECT  37.296 26.725 37.32 28.211 ;
     RECT  23.232 27.299 25.128 28.259 ;
     RECT  38.88 27.829 40.632 28.355 ;
     RECT  39.312 28.355 40.632 28.405 ;
     RECT  29.4 23.939 29.712 28.453 ;
     RECT  34.8 2.151 35.112 28.453 ;
     RECT  34.8 28.453 35.208 28.595 ;
     RECT  55.824 27.301 57.528 28.789 ;
     RECT  53.808 27.251 53.832 28.835 ;
     RECT  55.296 28.789 57.528 28.835 ;
     RECT  58.704 27.733 58.728 28.931 ;
     RECT  56.4 28.835 57.528 29.123 ;
     RECT  115.8 26.725 116.232 29.123 ;
     RECT  124.224 27.971 124.248 29.171 ;
     RECT  44.976 27.251 45.912 29.173 ;
     RECT  44.544 29.173 45.912 29.315 ;
     RECT  16.128 28.261 16.152 29.363 ;
     RECT  39.312 28.405 41.352 29.363 ;
     RECT  7.8 26.195 8.664 29.605 ;
     RECT  52.464 28.405 52.488 29.651 ;
     RECT  12.24 27.877 13.512 29.795 ;
     RECT  24 28.259 25.128 30.181 ;
     RECT  49.584 27.973 49.608 30.227 ;
     RECT  7.248 29.605 8.664 30.275 ;
     RECT  55.296 28.835 55.32 30.275 ;
     RECT  7.248 30.275 8.112 30.563 ;
     RECT  29.4 28.453 30.264 30.661 ;
     RECT  33.36 30.181 33.384 30.709 ;
     RECT  29.4 30.661 30.744 30.803 ;
     RECT  54.72 30.661 54.744 30.803 ;
     RECT  39.648 29.363 40.512 30.851 ;
     RECT  29.4 30.803 30.264 30.899 ;
     RECT  22.944 30.949 22.968 31.045 ;
     RECT  24 30.181 25.656 31.045 ;
     RECT  22.944 31.045 25.656 31.283 ;
     RECT  22.944 31.283 25.56 31.331 ;
     RECT  44.976 29.315 45.912 31.621 ;
     RECT  33.312 30.709 33.384 31.667 ;
     RECT  44.592 31.621 45.912 31.669 ;
     RECT  44.592 31.669 46.008 31.717 ;
     RECT  44.592 31.717 46.104 31.813 ;
     RECT  22.944 31.331 24.408 31.907 ;
     RECT  44.592 31.813 46.872 31.907 ;
     RECT  23.664 31.907 24.408 32.195 ;
     RECT  34.8 28.595 35.112 32.197 ;
     RECT  34.8 32.197 35.352 32.293 ;
     RECT  34.8 32.293 35.544 32.435 ;
     RECT  48.816 31.957 48.84 32.437 ;
     RECT  45.6 31.907 46.872 32.483 ;
     RECT  37.104 31.813 37.128 32.773 ;
     RECT  38.304 31.861 38.328 32.773 ;
     RECT  23.904 32.195 24.408 33.395 ;
     RECT  34.8 32.435 35.352 33.443 ;
     RECT  48.816 32.437 48.936 33.541 ;
     RECT  48.24 33.541 48.936 33.587 ;
     RECT  40.2 30.851 40.512 34.069 ;
     RECT  43.248 31.093 43.272 34.165 ;
     RECT  44.592 31.907 44.616 34.165 ;
     RECT  43.248 34.165 44.616 34.453 ;
     RECT  45.6 32.483 46.776 34.501 ;
     RECT  37.104 32.773 38.328 34.691 ;
     RECT  33.36 31.667 33.384 34.741 ;
     RECT  40.2 34.069 41.016 34.741 ;
     RECT  37.104 34.691 37.704 34.835 ;
     RECT  40.08 34.741 41.016 34.835 ;
     RECT  42.912 34.453 44.616 34.835 ;
     RECT  48.24 33.587 48.264 34.883 ;
     RECT  42.912 34.835 43.368 35.219 ;
     RECT  44.592 34.835 44.616 35.267 ;
     RECT  34.8 33.443 35.208 35.269 ;
     RECT  37.104 34.835 37.128 35.363 ;
     RECT  40.08 34.835 40.512 35.459 ;
     RECT  45.6 34.501 46.824 35.603 ;
     RECT  43.296 35.219 43.368 35.747 ;
     RECT  33.072 34.741 33.384 35.987 ;
     RECT  24 33.395 24.408 36.325 ;
     RECT  25.536 31.331 25.56 36.325 ;
     RECT  43.296 35.747 43.32 36.515 ;
     RECT  48.432 35.557 48.456 36.515 ;
     RECT  34.8 35.269 35.976 36.563 ;
     RECT  24 36.325 25.56 36.947 ;
     RECT  33.36 35.987 33.384 36.947 ;
     RECT  24 36.947 24.312 38.725 ;
     RECT  24 38.725 24.552 39.347 ;
     RECT  25.536 36.947 25.56 39.637 ;
     RECT  29.4 30.899 29.712 39.637 ;
     RECT  25.536 39.637 26.184 44.387 ;
     RECT  34.8 36.563 35.64 44.771 ;
     RECT  66.144 22.645 66.168 44.773 ;
     RECT  67.2 2.151 67.512 44.773 ;
     RECT  66.144 44.773 67.512 44.963 ;
     RECT  66.384 44.963 67.512 50.195 ;
     RECT  4.032 6.323 4.056 50.387 ;
     RECT  28.464 39.637 29.712 58.163 ;
     RECT  24 39.347 24.312 75.157 ;
     RECT  26.16 44.387 26.184 75.157 ;
     RECT  28.368 58.645 28.392 75.781 ;
     RECT  29.4 58.163 29.712 76.357 ;
     RECT  24 75.157 26.184 76.789 ;
     RECT  22.464 76.837 22.488 76.885 ;
     RECT  24 76.789 26.856 76.979 ;
     RECT  28.176 75.781 28.392 76.979 ;
     RECT  28.176 76.979 28.2 77.027 ;
     RECT  34.8 44.771 35.592 77.699 ;
     RECT  22.128 76.885 22.488 77.795 ;
     RECT  24 76.979 25.704 78.131 ;
     RECT  21.072 77.509 21.096 78.613 ;
     RECT  22.128 77.795 22.152 78.613 ;
     RECT  26.832 76.979 26.856 78.613 ;
     RECT  21.072 78.613 22.152 78.659 ;
     RECT  24 78.131 25.032 78.755 ;
     RECT  21.264 78.659 22.152 79.285 ;
     RECT  26.832 78.613 27.768 79.765 ;
     RECT  24 78.755 24.888 79.813 ;
     RECT  26.064 79.765 27.768 79.813 ;
     RECT  31.248 78.229 31.272 79.909 ;
     RECT  30.912 79.909 31.272 79.955 ;
     RECT  29.4 76.357 29.88 80.341 ;
     RECT  30.912 79.955 30.936 80.341 ;
     RECT  21.264 79.285 22.344 80.389 ;
     RECT  24 79.813 28.296 80.389 ;
     RECT  29.4 80.341 30.936 80.531 ;
     RECT  21.264 80.389 28.296 81.539 ;
     RECT  21.264 81.539 28.104 82.931 ;
     RECT  21.264 82.931 27.96 83.221 ;
     RECT  20.544 83.221 27.96 83.461 ;
     RECT  20.256 83.461 27.96 83.653 ;
     RECT  29.4 80.531 30.216 83.797 ;
     RECT  29.4 83.797 31.128 83.843 ;
     RECT  2.4 27.347 2.712 84.249 ;
     RECT  7.8 30.563 8.112 84.249 ;
     RECT  13.2 29.795 13.512 84.249 ;
     RECT  18.6 28.211 18.912 84.249 ;
     RECT  34.8 77.699 35.112 84.249 ;
     RECT  40.2 35.459 40.512 84.249 ;
     RECT  45.6 35.603 45.912 84.249 ;
     RECT  51 26.003 51.312 84.249 ;
     RECT  56.4 29.123 56.712 84.249 ;
     RECT  61.8 2.151 62.112 84.249 ;
     RECT  67.2 50.195 67.512 84.249 ;
     RECT  72.6 2.151 72.912 84.249 ;
     RECT  78 2.151 78.312 84.249 ;
     RECT  83.4 2.151 83.712 84.249 ;
     RECT  88.8 2.151 89.112 84.249 ;
     RECT  94.2 2.151 94.512 84.249 ;
     RECT  99.6 2.151 99.912 84.249 ;
     RECT  105 2.151 105.312 84.249 ;
     RECT  110.4 2.151 110.712 84.249 ;
     RECT  115.8 29.123 116.112 84.249 ;
     RECT  121.2 2.151 121.512 84.249 ;
     RECT  126.6 2.151 126.912 84.249 ;
     RECT  2.4 84.249 2.52 84.263 ;
     RECT  7.8 84.249 7.92 84.263 ;
     RECT  13.2 84.249 13.32 84.263 ;
     RECT  18.6 84.249 18.72 84.263 ;
     RECT  34.8 84.249 34.92 84.263 ;
     RECT  40.2 84.249 40.32 84.263 ;
     RECT  45.6 84.249 45.72 84.263 ;
     RECT  51 84.249 51.12 84.263 ;
     RECT  56.4 84.249 56.52 84.263 ;
     RECT  61.8 84.249 61.92 84.263 ;
     RECT  67.2 84.249 67.32 84.263 ;
     RECT  72.6 84.249 72.72 84.263 ;
     RECT  78 84.249 78.12 84.263 ;
     RECT  83.4 84.249 83.52 84.263 ;
     RECT  88.8 84.249 88.92 84.263 ;
     RECT  94.2 84.249 94.32 84.263 ;
     RECT  99.6 84.249 99.72 84.263 ;
     RECT  105 84.249 105.12 84.263 ;
     RECT  110.4 84.249 110.52 84.263 ;
     RECT  115.8 84.249 115.92 84.263 ;
     RECT  121.2 84.249 121.32 84.263 ;
     RECT  126.6 84.249 126.72 84.263 ;
     RECT  20.16 83.653 27.96 84.325 ;
     RECT  29.4 83.843 29.976 84.373 ;
     RECT  29.376 84.373 29.976 85.477 ;
     RECT  20.16 84.325 28.152 86.245 ;
     RECT  29.28 85.477 29.976 86.245 ;
     RECT  20.064 86.245 28.152 86.316 ;
     RECT  20.088 86.316 20.16 86.352 ;
     RECT  20.184 86.316 20.256 86.352 ;
     RECT  20.28 86.316 20.352 86.352 ;
     RECT  20.376 86.316 20.448 86.352 ;
     RECT  20.472 86.316 20.544 86.352 ;
     RECT  20.568 86.316 20.64 86.352 ;
     RECT  20.664 86.316 20.736 86.352 ;
     RECT  20.76 86.316 20.832 86.352 ;
     RECT  20.856 86.316 20.928 86.352 ;
     RECT  20.952 86.316 21.024 86.352 ;
     RECT  21.048 86.316 21.12 86.352 ;
     RECT  21.144 86.316 21.216 86.352 ;
     RECT  21.24 86.316 21.312 86.352 ;
     RECT  21.336 86.316 21.408 86.352 ;
     RECT  21.432 86.316 21.504 86.352 ;
     RECT  21.528 86.316 21.6 86.352 ;
     RECT  21.624 86.316 21.696 86.352 ;
     RECT  21.72 86.316 21.792 86.352 ;
     RECT  21.816 86.316 21.888 86.352 ;
     RECT  21.912 86.316 21.984 86.352 ;
     RECT  22.008 86.316 22.08 86.352 ;
     RECT  22.104 86.316 22.176 86.352 ;
     RECT  22.2 86.316 22.272 86.352 ;
     RECT  22.296 86.316 22.368 86.352 ;
     RECT  22.392 86.316 22.464 86.352 ;
     RECT  22.488 86.316 22.56 86.352 ;
     RECT  22.584 86.316 22.656 86.352 ;
     RECT  22.68 86.316 22.752 86.352 ;
     RECT  22.776 86.316 22.848 86.352 ;
     RECT  22.872 86.316 22.944 86.352 ;
     RECT  22.968 86.316 23.04 86.352 ;
     RECT  23.064 86.316 23.136 86.352 ;
     RECT  23.16 86.316 23.232 86.352 ;
     RECT  23.256 86.316 23.328 86.352 ;
     RECT  23.352 86.316 23.424 86.352 ;
     RECT  23.448 86.316 23.52 86.352 ;
     RECT  23.544 86.316 23.616 86.352 ;
     RECT  23.64 86.316 23.712 86.352 ;
     RECT  23.736 86.316 23.808 86.352 ;
     RECT  23.832 86.316 23.904 86.352 ;
     RECT  23.928 86.316 24 86.352 ;
     RECT  24.024 86.316 24.096 86.352 ;
     RECT  24.12 86.316 24.192 86.352 ;
     RECT  24.216 86.316 24.288 86.352 ;
     RECT  24.312 86.316 24.384 86.352 ;
     RECT  24.408 86.316 24.48 86.352 ;
     RECT  24.504 86.316 24.576 86.352 ;
     RECT  24.6 86.316 24.672 86.352 ;
     RECT  24.696 86.316 24.768 86.352 ;
     RECT  24.792 86.316 24.864 86.352 ;
     RECT  24.888 86.316 24.96 86.352 ;
     RECT  24.984 86.316 25.056 86.352 ;
     RECT  25.08 86.316 25.152 86.352 ;
     RECT  25.176 86.316 25.248 86.352 ;
     RECT  25.272 86.316 25.344 86.352 ;
     RECT  25.368 86.316 25.44 86.352 ;
     RECT  25.464 86.316 25.536 86.352 ;
     RECT  25.56 86.316 25.632 86.352 ;
     RECT  25.656 86.316 25.728 86.352 ;
     RECT  25.752 86.316 25.824 86.352 ;
     RECT  25.848 86.316 25.92 86.352 ;
     RECT  25.944 86.316 26.016 86.352 ;
     RECT  26.04 86.316 26.112 86.352 ;
     RECT  26.136 86.316 26.208 86.352 ;
     RECT  26.232 86.316 26.304 86.352 ;
     RECT  26.328 86.316 26.4 86.352 ;
     RECT  26.424 86.316 26.496 86.352 ;
     RECT  26.52 86.316 26.592 86.352 ;
     RECT  26.616 86.316 26.688 86.352 ;
     RECT  26.712 86.316 26.784 86.352 ;
     RECT  26.808 86.316 26.88 86.352 ;
     RECT  26.904 86.316 26.976 86.352 ;
     RECT  27 86.316 27.072 86.352 ;
     RECT  27.096 86.316 27.168 86.352 ;
     RECT  27.192 86.316 27.264 86.352 ;
     RECT  27.288 86.316 27.36 86.352 ;
     RECT  27.384 86.316 27.456 86.352 ;
     RECT  27.48 86.316 27.552 86.352 ;
     RECT  27.576 86.316 27.648 86.352 ;
     RECT  27.672 86.316 27.744 86.352 ;
     RECT  27.768 86.316 27.84 86.352 ;
     RECT  27.864 86.316 27.936 86.352 ;
     RECT  27.96 86.316 28.032 86.352 ;
     RECT  28.056 86.316 28.128 86.352 ;
     RECT  29.184 86.245 29.976 86.316 ;
     RECT  29.208 86.316 29.28 86.352 ;
     RECT  29.304 86.316 29.376 86.352 ;
     RECT  29.4 86.316 29.472 86.352 ;
     RECT  29.496 86.316 29.568 86.352 ;
     RECT  29.592 86.316 29.664 86.352 ;
     RECT  29.688 86.316 29.76 86.352 ;
     RECT  29.784 86.316 29.856 86.352 ;
     RECT  29.88 86.316 29.952 86.352 ;
     RECT  31.008 83.843 31.128 86.316 ;
     RECT  31.032 86.316 31.104 86.352 ;
     RECT  2.52 2.137 4.032 2.151 ;
     RECT  2.712 2.151 4.032 27.109 ;
     RECT  17.304 20.341 18.6 21.539 ;
     RECT  27.912 20.341 29.28 20.389 ;
     RECT  28.056 20.389 29.28 21.251 ;
     RECT  28.056 21.251 29.4 22.499 ;
     RECT  51.312 22.453 52.752 25.285 ;
     RECT  27.912 22.499 29.4 23.411 ;
     RECT  66.168 22.645 67.2 44.773 ;
     RECT  14.376 22.741 15.696 24.995 ;
     RECT  26.76 23.173 27.888 23.411 ;
     RECT  29.88 23.317 30.912 23.939 ;
     RECT  23.328 23.411 24 24.277 ;
     RECT  0.168 23.557 1.152 23.891 ;
     RECT  1.176 23.557 2.4 23.891 ;
     RECT  0.168 23.891 2.4 23.939 ;
     RECT  1.248 23.939 2.4 24.373 ;
     RECT  29.712 23.939 30.912 25.715 ;
     RECT  22.824 24.277 24 24.467 ;
     RECT  1.272 24.373 2.4 24.515 ;
     RECT  22.8 24.467 24 25.189 ;
     RECT  33.672 24.469 34.8 25.715 ;
     RECT  40.632 24.947 41.16 25.813 ;
     RECT  14.376 24.995 14.664 25.957 ;
     RECT  18.912 24.995 19.032 26.149 ;
     RECT  22.008 25.189 24 25.427 ;
     RECT  48.744 25.285 50.112 25.957 ;
     RECT  22.704 25.427 24 25.909 ;
     RECT  35.112 25.621 36.432 26.243 ;
     RECT  40.632 25.813 41.712 26.099 ;
     RECT  22.728 25.909 24 25.957 ;
     RECT  22.728 25.957 23.904 26.099 ;
     RECT  49.944 26.003 51 26.723 ;
     RECT  22.704 26.099 24 27.013 ;
     RECT  40.632 26.099 40.776 26.245 ;
     RECT  60.456 26.197 61.8 26.819 ;
     RECT  38.448 26.243 38.472 26.725 ;
     RECT  48.744 26.483 49.92 26.723 ;
     RECT  17.16 26.485 18.6 26.627 ;
     RECT  28.104 26.581 29.4 27.491 ;
     RECT  17.664 26.627 18.6 27.157 ;
     RECT  13.512 26.675 14.64 27.443 ;
     RECT  48.744 26.723 51 26.819 ;
     RECT  37.32 26.725 38.472 27.493 ;
     RECT  40.032 26.819 40.08 27.493 ;
     RECT  48.816 26.819 51 27.541 ;
     RECT  22.68 27.013 24 27.061 ;
     RECT  2.808 27.109 4.032 27.347 ;
     RECT  53.568 27.251 53.808 28.405 ;
     RECT  2.712 27.347 4.032 50.387 ;
     RECT  37.32 27.493 38.784 27.731 ;
     RECT  38.808 27.493 40.08 27.731 ;
     RECT  48.936 27.541 51 27.827 ;
     RECT  38.88 27.731 40.08 27.829 ;
     RECT  57.528 27.733 58.704 28.931 ;
     RECT  49.584 27.827 51 27.973 ;
     RECT  49.608 27.973 51 30.227 ;
     RECT  51.312 28.405 52.464 29.651 ;
     RECT  52.488 28.405 53.808 28.835 ;
     RECT  53.832 28.789 55.296 28.835 ;
     RECT  55.32 28.835 56.4 30.275 ;
     RECT  33.384 30.181 34.8 36.947 ;
     RECT  22.968 30.949 24 31.045 ;
     RECT  24.408 31.331 25.536 36.325 ;
     RECT  43.272 31.621 44.592 34.165 ;
     RECT  37.128 31.861 38.304 32.773 ;
     RECT  44.616 31.907 45.6 35.267 ;
     RECT  46.776 32.483 46.872 33.541 ;
     RECT  46.776 33.541 48.24 34.501 ;
     RECT  46.824 34.501 48.24 34.883 ;
     RECT  43.368 34.835 44.592 35.267 ;
     RECT  35.976 35.269 37.104 35.363 ;
     RECT  24.312 36.947 25.536 38.725 ;
     RECT  24.552 38.725 25.536 39.347 ;
     RECT  24.312 39.347 25.536 44.387 ;
     RECT  28.464 58.163 29.4 58.645 ;
     RECT  28.392 58.645 29.4 76.979 ;
     RECT  26.856 76.789 28.176 77.027 ;
     RECT  22.488 76.837 24 77.795 ;
     RECT  25.704 76.979 26.832 78.131 ;
     RECT  28.2 76.979 29.4 77.027 ;
     RECT  21.096 77.509 22.128 78.613 ;
     RECT  22.152 77.795 22.344 79.285 ;
     RECT  29.88 78.229 31.248 79.909 ;
     RECT  24.888 78.755 25.032 79.765 ;
     RECT  24.888 79.765 26.064 79.813 ;
     RECT  28.296 79.813 29.4 81.539 ;
     RECT  29.88 79.909 30.912 80.341 ;
     RECT  28.104 81.539 29.4 82.931 ;
     RECT  27.96 82.931 29.4 84.325 ;
     RECT  18.912 83.461 20.256 83.653 ;
     RECT  18.912 83.653 20.16 84.249 ;
     RECT  29.976 83.843 31.008 86.268 ;
     RECT  18.72 84.249 20.16 84.263 ;
     RECT  28.152 84.325 29.4 84.373 ;
     RECT  28.152 84.373 29.376 85.477 ;
     RECT  28.152 85.477 29.28 86.245 ;
     RECT  28.152 86.245 29.184 86.268 ;
     RECT  28.2 86.268 29.136 86.352 ;
     RECT  30.024 86.268 30.96 86.352 ;
  END
END ot_s81_engram_dispatch
END LIBRARY
